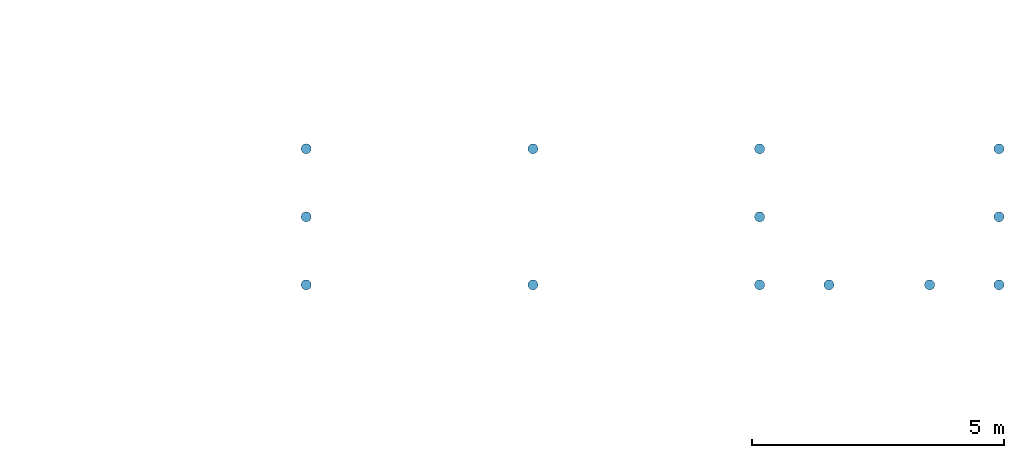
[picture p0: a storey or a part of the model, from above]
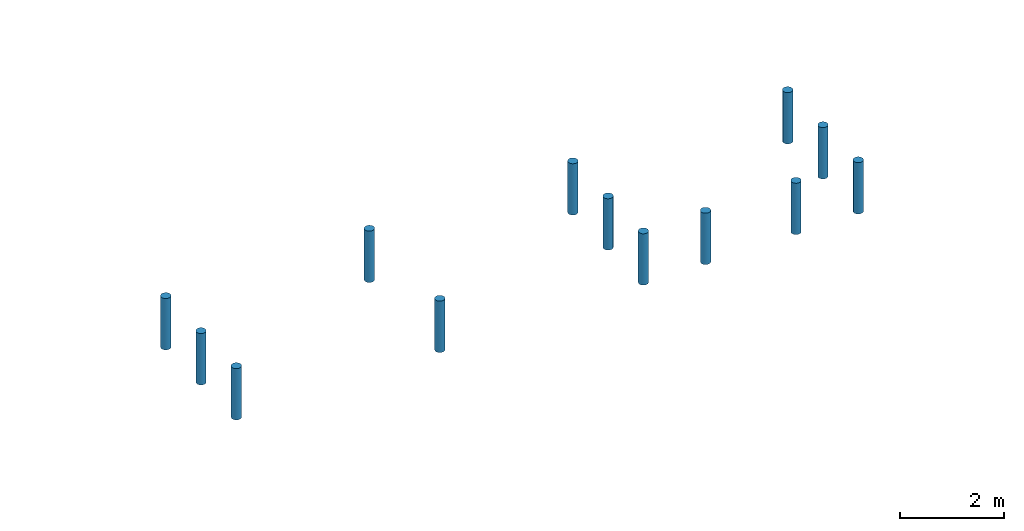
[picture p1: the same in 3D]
Properties of the parts of a building model (IFC2X3), part 1 of 5

# File
Description: ViewDefinition [CoordinationView_V2.0, SpaceBoundary2ndLevelAddOnView], Option [Drawing Scale: 100.000000], Option [Elements to export: Visible elements (on all stories)], Option [Partial Structure Display: Entire Model], Option [IFC Domain: All], Option [Structural Function: All Elements], Option [Convert Grid elements: On], Option [Convert IFC Annotations and ARCHICAD 2D elements: Off], Option [Convert 2D symbols of Doors and Windows: Off], Option [Export geometries that Participates in Collision Detection only: Off], Option [Split complex elements: On], Option [IFC Domain For Space Containment: Custom], Option [Elements in Solid Element Operations: Extruded/revolved], Option [Elements with junctions: Extruded/revolved without junctions], Option [Slabs with slanted edge(s): Extruded], Option [IFC Site Location: At Project Origin], Option [Curtain Wall export mode: Container Element], Option [Railing export mode: Container Element], Option [Stair export mode: Container Element], Option [Properties To Export: All properties], Option [Space containment: Off], Option [Bounding Box: Off], Option [Geometry to type objects: Off], Option [Element Properties: Visible Only], Option [Building Material Properties: Off], Option [Element Parameters: Off], Option [Component Parameters: Off], Option [IFC Base Quantities: Off], Option [Door Window Parameters: On], Option [IFC Space boundaries: On], Option [ARCHICAD Zone Categories as IFC Space classification data: Off], Option [Element Classifications: On]
File name: Z:\03. EHITUSPROJEKTID\2023_355_Paldiski mnt 245 projekteerimine\09-Projektid\3_PÕHIPROJEKT\02-Arhitektuur-TP\IFC\355_TP_AR.ifc
Time: 2023-11-21T12:02:21
Author: Raido Roosnurm (allikirjastatud digitaalselt)
Organization: Building Designer Office
Written by: The EXPRESS Data Manager Version 5.02.0100.09 : 26 Sep 2013
Made in: IFC file generated by GRAPHISOFT ARCHICAD 23.0.0 INT FULL Windows version (IFC add-on version: 7000 INT FULL).
Authorization: Raido Roosnurm (allikirjastatud digitaalselt)

# IfcProject, Ilmavaatlusjaama peahoone rekonstrueerimine
Description: Arhitektuur; Phase: Tööprojekt

# IfcSite, Paldiski mnt 245/1, Tallinn, Harjumaa
Description: Ühiskondlike ehitiste maa 100%; RefLatitude: 59, 26, 0, 0; RefLongitude: 24, 45, 0, 0; RefElevation: 0 mm; Classification: 1.0.1 IfcSite (kinnistu); C Existing site/buildings/services (CAWS)
AR_Kinnistu - 010_Katastritunnus: 78406:605:0160; 020_Pindala: 24079 m2; 025_Max_kõrgus: 8600 mm; 015_Ehitatav_pindala: 1045.7 m2

# IfcBuilding, RKAS Hoone üldnimetus (kasutust iseloomustav) -> IFC Project Manager -> SOLIBRI
Classification: 1.0.2 IfcBuilding (hoone)
AR_Hoone - 035_Sprinkler: no; 001_Nimetus: 12201 Büroohoone; 030_Hoone_aadress: Paldiski mnt 245/1 (katastriüksuse tunnus 78406:605:0160 ), Haabersti linnaosa, Tallinn, Eesti Vabariik; 040_Kõrgus: 8600 mm; ?: 1004.1 m2; 050_Neto_pindala: 1090.4 m2; 055_Neto_ruumala: 5563.9 m3

# IfcBuildingStorey (4)
In: RKAS Hoone üldnimetus (kasutust iseloomustav) -> IFC Project Manager -> SOLIBRI
Name | Elevation (mm) | Classification
Vundament | -1200 | 1.0.3 IfcBuildingStorey (korrus) (RKAS BIM + ARCHICAD Classification 25 + v 2.0)
Esimene korrus | 0 | 1.0.3 IfcBuildingStorey (korrus) (RKAS BIM + ARCHICAD Classification 25 + v 2.0)
Teine korrus | 3300 | 1.0.3 IfcBuildingStorey (korrus) (RKAS BIM + ARCHICAD Classification 25 + v 2.0)
Katusekorrus | 6240

# IfcSpace: Elamise ja puhkealad (2)
In: Teine korrus
InteriorOrExteriorSpace: INTERNAL; Classification: 1.21 IfcSpaceType (ruum) (RKAS BIM + ARCHICAD Classification)
Pset_SpaceCommon - Reference: Korruse avatud netopind; Category: Elamise ja puhkealad
AR_Ruum - 115_Kategooria: Elamise ja puhkealad; 110_Tüüp: Korruse avatud netopind; 125_Turvatsoon: Undefined
AC_Pset_RenovationAndPhasing - Renovation Status: New
Name | LongName = 100_Nimi | 105_Number | 120_Pindala (m2)
204 | PUHKERUUM | 204 | 33.1481
208 | MAGAMISRUUM | 208 | 26.2499

# IfcSpace: Haridus & Kultuur (2)
In: Esimene korrus
LongName: VÄLJAPANEKUD; InteriorOrExteriorSpace: INTERNAL; Classification: 1.21 IfcSpaceType (ruum) (RKAS BIM + ARCHICAD Classification)
Pset_SpaceCommon - Reference: Korruse avatud netopind; Category: Haridus & Kultuur
AR_Ruum - 100_Nimi: VÄLJAPANEKUD; 115_Kategooria: Haridus & Kultuur; 110_Tüüp: Korruse avatud netopind; 125_Turvatsoon: Undefined
AC_Pset_RenovationAndPhasing - Renovation Status: New
Name | 105_Number | 120_Pindala (m2)
127 | 127 | 66.1922
128 | 128 | 32.1546

# IfcSpace: Kontor (10)
InteriorOrExteriorSpace: INTERNAL; Classification: 1.21 IfcSpaceType (ruum) (RKAS BIM + ARCHICAD Classification)
Pset_SpaceCommon - Reference: Korruse avatud netopind; Category: Kontor
AR_Ruum - 115_Kategooria: Kontor; 110_Tüüp: Korruse avatud netopind; 125_Turvatsoon: Undefined
Name | In | LongName = 100_Nimi | 105_Number | 120_Pindala (m2) | Renovation Status
106 | Esimene korrus | KABINET | 106 | 12.4553 | New
105 | Esimene korrus | KABINET | 105 | 12.3328 | New
104 | Esimene korrus | KABINET | 104 | 12.8259 | New
137 | Esimene korrus | KABINET | 137 | 12.2724 | Existing
136 | Esimene korrus | KABINET | 136 | 12.5438 | Existing
214 | Teine korrus | KABINET | 214 | 22.6734 | New
213 | Teine korrus | KABINET | 213 | 23.5477 | New
212 | Teine korrus | KABINET | 212 | 23.9219 | New
211 | Teine korrus | KABINET | 211 | 50.2572 | New
207 | Teine korrus | NÕUPIDAMINE (30 in.) | 207 | 60.7451 | New

# IfcSpace: Ladustamine & Müük (6)
In: Esimene korrus
InteriorOrExteriorSpace: INTERNAL; Classification: 1.21 IfcSpaceType (ruum) (RKAS BIM + ARCHICAD Classification)
Pset_SpaceCommon - Reference: Korruse avatud netopind; Category: Ladustamine & Müük
AR_Ruum - 115_Kategooria: Ladustamine & Müük; 110_Tüüp: Korruse avatud netopind; 125_Turvatsoon: Undefined
AC_Pset_RenovationAndPhasing - Renovation Status: New
Name | LongName = 100_Nimi | 105_Number | 120_Pindala (m2)
107 | LADU | 107 | 36.1465
126 | GARAAZ | 126 | 68.6563
125 | GARAAZ | 125 | 68.3974
121 | LADU (AKUD) | 121 | 7.95556
108 | LADU | 108 | 75.1071
109 | LADU | 109 | 35.0688

# IfcSpace: Muu kasutus (17)
InteriorOrExteriorSpace: INTERNAL; Classification: 1.21 IfcSpaceType (ruum) (RKAS BIM + ARCHICAD Classification)
Pset_SpaceCommon - Category: Muu kasutus
AR_Ruum - 115_Kategooria: Muu kasutus; 125_Turvatsoon: Undefined
Name | In | LongName = 100_Nimi | Reference = 110_Tüüp | 105_Number | 120_Pindala (m2) | Renovation Status
118 | Esimene korrus | WC | Undefined | 118 | 1.76756 | New
111 | Esimene korrus | KORISTAJA | Korruse avatud netopind | 111 | 6.391 | New
132 | Esimene korrus | GARDEROOB | Korruse avatud netopind | 132 | 6.45011 | New
116 | Esimene korrus | DUŠIRUUM | Korruse avatud netopind | 116 | 8.84436 | New
114.1 | Esimene korrus | RIIETUS/HOOLDUSRUUM | Korruse avatud netopind | 114.1 | 30.479 | New
110 | Esimene korrus | INVA WC | Korruse avatud netopind | 110 | 6.38677 | New
130.1 | Esimene korrus | WC | Korruse avatud netopind | 130.1 | 3.36477 | New
130.3 | Esimene korrus | WC | Korruse avatud netopind | 130.3 | 1.12567 | Existing
130.2 | Esimene korrus | WC | Korruse avatud netopind | 130.2 | 1.14087 | Existing
 | Esimene korrus | PRÜGIMAJA | Undefined |  | 11.8508 | New
 | Esimene korrus | JALGRATASTE HOIDLA | Undefined |  | 24.1807 | New
114.3 | Esimene korrus | RIIETUSBOKS | Korruse avatud netopind | 114.3 | 1.35 | Existing
114.2 | Esimene korrus | RIIETUSBOKS | Korruse avatud netopind | 114.2 | 1.25 | Existing
209 | Teine korrus | DUSS/WC | Korruse avatud netopind | 209 | 5.80168 | New
206 | Teine korrus | WC | Korruse avatud netopind | 206 | 3.17635 | New
205 | Teine korrus | WC | Korruse avatud netopind | 205 | 3.04617 | New
210 | Teine korrus | KORISTAJA | Korruse avatud netopind | 210 | 2.58193 | New

# IfcSpace: Tehnoseadmed (3)
InteriorOrExteriorSpace: INTERNAL; Classification: 1.21 IfcSpaceType (ruum) (RKAS BIM + ARCHICAD Classification)
Pset_SpaceCommon - Reference: Tehnopind; Category: Tehnoseadmed
AR_Ruum - 115_Kategooria: Tehnoseadmed; 110_Tüüp: Tehnopind; 125_Turvatsoon: Undefined
AC_Pset_RenovationAndPhasing - Renovation Status: New
Name | In | LongName = 100_Nimi | 105_Number | 120_Pindala (m2)
129 | Esimene korrus | GENERAATOR | 129 | 8.20989
119 | Esimene korrus | TEH. RUUM (el.kilp, vent, sooja- ja veesõlm) | 119 | 43.453
203 | Teine korrus | RADAR | 203 | 16.8812

# IfcSpace: Tootmine & Teadus (3)
In: Esimene korrus
LongName: KALIBREERIMISLABOR; InteriorOrExteriorSpace: INTERNAL; Classification: 1.21 IfcSpaceType (ruum) (RKAS BIM + ARCHICAD Classification)
Pset_SpaceCommon - Reference: Tehnopind; Category: Tootmine & Teadus
AR_Ruum - 100_Nimi: KALIBREERIMISLABOR; 115_Kategooria: Tootmine & Teadus; 110_Tüüp: Tehnopind; 125_Turvatsoon: Undefined
AC_Pset_RenovationAndPhasing - Renovation Status: New
Name | 105_Number | 120_Pindala (m2)
123 | 123 | 5.81406
122 | 122 | 9.8359
124 | 124 | 31.0494

# IfcSpace: Üldine (14)
InteriorOrExteriorSpace: INTERNAL; Classification: 1.21 IfcSpaceType (ruum) (RKAS BIM + ARCHICAD Classification)
Pset_SpaceCommon - Category: Üldine
AR_Ruum - 115_Kategooria: Üldine; 125_Turvatsoon: Undefined
Name | In | LongName = 100_Nimi | Reference = 110_Tüüp | 105_Number | 120_Pindala (m2) | Renovation Status
101 | Esimene korrus | FUAJEE | Korruse avatud netopind | 101 | 34.5309 | New
133 | Esimene korrus | TUULEKODA | Korruse avatud netopind | 133 | 7.69125 | New
120 | Esimene korrus | TUULEKODA | Undefined | 120 | 6.195 | New
117 | Esimene korrus | LEILIRUUM | Undefined | 117 | 4.89433 | New
112 | Esimene korrus | PANIPAIK | Undefined | 112 | 4.02908 | New
103 | Esimene korrus | KORIDOR | Korruse avatud netopind | 103 | 21.3865 | New
113 | Esimene korrus | KORIDOR | Korruse avatud netopind | 113 | 12.2933 | New
115 | Esimene korrus | TUULEKODA | Korruse avatud netopind | 115 | 3.75255 | New
131 | Esimene korrus | KORISTAJA | Korruse avatud netopind | 131 | 3.29858 | New
102 | Esimene korrus | TREPIKODA | Vertikaalsete ühendusteede pind | 102 | 11.8965 | New
135 | Esimene korrus | GARDEROOB | Undefined | 135 | 4.71122 | Existing
134 | Esimene korrus | ÕHUVÕTUKAMBER | Undefined | 134 | 1.53 | New
201 | Teine korrus | TREPIKODA | Vertikaalsete ühendusteede pind | 201 | 18.1173 | New
202 | Teine korrus | KORIDOR | Korruse avatud netopind | 202 | 44.7589 | New

# IfcBeam: CFRHS50X50X5 50 x 50 (7)
In: Esimene korrus
Type - PredefinedType: BEAM
Classification: 1.01 IfcBeamType (tala) (RKAS BIM + ARCHICAD Classification); Material: VKR-04_Tellis
Pset_BeamCommon - Slope: 0 deg; LoadBearing: yes; IsExternal: no; Reference: CFRHS50X50X5 50 x 50
AC_Pset_RenovationAndPhasing - Renovation Status: Existing

# IfcBeam: Laudis esiprofiil_01 21 x 622 (2)
In: Esimene korrus
Type - PredefinedType: BEAM
Classification: 1.01 IfcBeamType (tala) (RKAS BIM + ARCHICAD Classification)
Pset_BeamCommon - Slope: 0 deg; LoadBearing: no; IsExternal: yes; Reference: Laudis esiprofiil_01 21 x 622
AC_Pset_RenovationAndPhasing - Renovation Status: New

# IfcBeam: Laudis kaldprofiil_01 895 x 903 (2)
In: Esimene korrus
Type - PredefinedType: BEAM
Classification: 1.01 IfcBeamType (tala) (RKAS BIM + ARCHICAD Classification)
Pset_BeamCommon - Slope: 0 deg; LoadBearing: no; IsExternal: yes; Reference: Laudis kaldprofiil_01 895 x 903
AC_Pset_RenovationAndPhasing - Renovation Status: New

# IfcBeam: Olemasolev raudbetoontala 320 x 280 (3)
In: Esimene korrus
Type - PredefinedType: BEAM
Classification: 1.01 IfcBeamType (tala) (RKAS BIM + ARCHICAD Classification); Material: Olemasolev raudbetoontala
Pset_BeamCommon - Slope: 0 deg; LoadBearing: yes; IsExternal: no; Reference: Olemasolev raudbetoontala 320 x 280
AC_Pset_RenovationAndPhasing - Renovation Status: Existing

# IfcBeam: Olemasolev raudbetoontala 400 x 260 (7)
In: Teine korrus
Type - PredefinedType: BEAM
Classification: 1.01 IfcBeamType (tala) (RKAS BIM + ARCHICAD Classification); Material: Olemasolev raudbetoontala
Pset_BeamCommon - Slope: 0 deg; LoadBearing: yes; IsExternal: no; Reference: Olemasolev raudbetoontala 400 x 260
AC_Pset_RenovationAndPhasing - Renovation Status: Existing

# IfcBeam: Olemasolev raudbetoontala 400 x 280 (4)
In: Esimene korrus
Type - PredefinedType: BEAM
Classification: 1.01 IfcBeamType (tala) (RKAS BIM + ARCHICAD Classification); Material: Olemasolev raudbetoontala
Pset_BeamCommon - Slope: 0 deg; LoadBearing: yes; IsExternal: no; Reference: Olemasolev raudbetoontala 400 x 280
AC_Pset_RenovationAndPhasing - Renovation Status: Existing

# IfcBeam: Olemasolev raudbetoontala 430 x 310, TALA
In: Esimene korrus
Type - PredefinedType: BEAM
Classification: 1.01 IfcBeamType (tala) (RKAS BIM + ARCHICAD Classification); Material: Olemasolev raudbetoontala
Pset_BeamCommon - Slope: 0 deg; LoadBearing: yes; IsExternal: no; Reference: Olemasolev raudbetoontala 430 x 310
AC_Pset_RenovationAndPhasing - Renovation Status: Existing

# IfcBeam: Olemasolev raudbetoontala 440 x 310, TALA
In: Teine korrus
Type - PredefinedType: BEAM
Classification: 1.01 IfcBeamType (tala) (RKAS BIM + ARCHICAD Classification); Material: Olemasolev raudbetoontala
Pset_BeamCommon - Slope: 0 deg; LoadBearing: yes; IsExternal: no; Reference: Olemasolev raudbetoontala 440 x 310
AC_Pset_RenovationAndPhasing - Renovation Status: Existing

# IfcBeam: Olemasolev raudbetoontala 480 x 370, TALA
In: Teine korrus
Type - PredefinedType: BEAM
Classification: 1.01 IfcBeamType (tala) (RKAS BIM + ARCHICAD Classification); Material: Olemasolev raudbetoontala
Pset_BeamCommon - Slope: 0 deg; LoadBearing: yes; IsExternal: no; Reference: Olemasolev raudbetoontala 480 x 370
AC_Pset_RenovationAndPhasing - Renovation Status: Existing

# IfcBeam: Olemasolev raudbetoontala 530 x 300, TALA
In: Teine korrus
Type - PredefinedType: BEAM
Classification: 1.01 IfcBeamType (tala) (RKAS BIM + ARCHICAD Classification); Material: Olemasolev raudbetoontala
Pset_BeamCommon - Slope: 0 deg; LoadBearing: yes; IsExternal: no; Reference: Olemasolev raudbetoontala 530 x 300
AC_Pset_RenovationAndPhasing - Renovation Status: Existing

# IfcBeam: Olemasolev raudbetoontala 550, Tala
In: Esimene korrus
Type - PredefinedType: BEAM
Classification: 1.01 IfcBeamType (tala) (RKAS BIM + ARCHICAD Classification); Material: Olemasolev raudbetoontala
AC_Pset_RenovationAndPhasing - Renovation Status: Existing
Pset_BeamCommon - LoadBearing: yes; IsExternal: no

# IfcBeam: Olemasolev raudbetoontala 550 x 370, TALA
In: Teine korrus
Type - PredefinedType: BEAM
Classification: 1.01 IfcBeamType (tala) (RKAS BIM + ARCHICAD Classification); Material: Olemasolev raudbetoontala
Pset_BeamCommon - Slope: 0 deg; LoadBearing: yes; IsExternal: no; Reference: Olemasolev raudbetoontala 550 x 370
AC_Pset_RenovationAndPhasing - Renovation Status: Existing

# IfcBeam: TORN_KONST_2 136 x 130 (12)
In: Katusekorrus
Type - PredefinedType: BEAM
Classification: 1.01 IfcBeamType (tala) (RKAS BIM + ARCHICAD Classification); Material: SV-03_Plaat - Põrand
Pset_BeamCommon - Slope: 0 deg; Reference: TORN_KONST_2 136 x 130
AC_Pset_RenovationAndPhasing - Renovation Status: Existing

# IfcBeam: TORN_KONST_3 155 x 165 (4)
In: Katusekorrus
Type - PredefinedType: BEAM
Classification: 1.01 IfcBeamType (tala) (RKAS BIM + ARCHICAD Classification); Material: SV-03_Plaat - Põrand
Pset_BeamCommon - Slope: 0 deg; Reference: TORN_KONST_3 155 x 165
AC_Pset_RenovationAndPhasing - Renovation Status: Existing

# IfcBeam: TORN_KONST_4 175 x 155 (4)
In: Katusekorrus
Type - PredefinedType: BEAM
Classification: 1.01 IfcBeamType (tala) (RKAS BIM + ARCHICAD Classification); Material: SV-03_Plaat - Põrand
Pset_BeamCommon - Slope: 0 deg; Reference: TORN_KONST_4 175 x 155
AC_Pset_RenovationAndPhasing - Renovation Status: Existing

# IfcBeam: TORN_KONST_5 70 x 70 (31)
Type - PredefinedType: BEAM
Classification: 1.01 IfcBeamType (tala) (RKAS BIM + ARCHICAD Classification); Material: SV-03_Plaat - Põrand
Pset_BeamCommon - Reference: TORN_KONST_5 70 x 70
AC_Pset_RenovationAndPhasing - Renovation Status: Existing
Name | In | Slope (deg)
7 x TALA | Esimene korrus | 27.3757
4 x TALA | Teine korrus | 32.8702
4 x TALA | Teine korrus | 32.6354
4 x TALA | Katusekorrus | 39.1421
4 x TALA | Katusekorrus | 36.9819
4 x TALA | Katusekorrus | 37.0505
4 x TALA | Katusekorrus | 39.1317

# IfcBeam: TORN_KONST_6 60 x 130 (4)
In: Teine korrus
Type - PredefinedType: BEAM
Classification: 1.01 IfcBeamType (tala) (RKAS BIM + ARCHICAD Classification); Material: SV-03_Plaat - Põrand
Pset_BeamCommon - Slope: 0 deg; LoadBearing: yes; IsExternal: yes; Reference: TORN_KONST_6 60 x 130
AC_Pset_RenovationAndPhasing - Renovation Status: Existing

# IfcBuildingElementPart (1711)
Name | In | Material
28 x Võõphüdroisolatsioon | Vundament | Võõphüdroisolatsioon
28 x EPS 120 Perimeeter | Vundament | EPS 120 Perimeeter
28 x Krohvisüsteem Weber vms | Vundament | Krohvisüsteem Weber vms
43 x Cembrit_C040 | Esimene korrus | Cembrit_C040
88 x VKR-06_Õhkvahe | Esimene korrus | VKR-06_Õhkvahe
90 x Kingspan Kooltherm | Esimene korrus | Kingspan Kooltherm
26 x EPS 200 | Esimene korrus | EPS 200
13 x Visqueen radoonikile | Esimene korrus | Visqueen radoonikile
13 x Kiudbetoon | Esimene korrus | Kiudbetoon
6 x SOJ-04_Soojustus - Mineraal Kõva | Esimene korrus | SOJ-04_Soojustus - Mineraal Kõva
38 x SKR-01_Õhkvahe - Raam | Esimene korrus | SKR-01_Õhkvahe - Raam
19 x Cembrit_C060 | Esimene korrus | Cembrit_C060
9 x Tasanduskrohv | Esimene korrus | Tasanduskrohv
21 x Cembrit_C020 | Esimene korrus | Cembrit_C020
6 x BAUROC CLASSIC 3 MPa kergplokk | Esimene korrus | BAUROC CLASSIC 3 MPa kergplokk
54 x Krohv | Esimene korrus | Krohv
27 x FIBO 5 | Esimene korrus | FIBO 5
6 x Isover Premium 33 | Esimene korrus | Isover Premium 33
6 x Isover Sauna | Esimene korrus | Isover Sauna
6 x Õhkvahe/horisontpuitroov | Esimene korrus | Õhkvahe/horisontpuitroov
6 x Õhkvahe/vertpuitroov | Esimene korrus | Õhkvahe/vertpuitroov
6 x Sauna puitlaudis | Esimene korrus | Sauna puitlaudis
8 x SKR-04_Puitplaat | Esimene korrus | SKR-04_Puitplaat
2 x SOJ-03_Soojustus - Mineraal Pehme | Esimene korrus | SOJ-03_Soojustus - Mineraal Pehme
16 x Kipsplaat Knauf GKF vm | Esimene korrus | Kipsplaat Knauf GKF vm
SV-05_Plaat - Sein | Esimene korrus | SV-05_Plaat - Sein
169 x Laudis 5072 Honka 45 horisontaalne raastas | Esimene korrus | Laudis 5072 Honka 45 horisontaalne raastas
4 x OSB plaat | Esimene korrus | OSB plaat
3 x Isover Acoustic | Esimene korrus | Isover Acoustic
5 x Kaldu lõigatud soojustus, EPS60 Silver | Esimene korrus | Kaldu lõigatud soojustus, EPS60 Silver
5 x Põhisoojustus, Eurothane Silver E 120 mm | Esimene korrus | Põhisoojustus, Eurothane Silver E 120 mm
5 x Katusekate PVC 1,6 mm, PROTAN SE | Esimene korrus | Katusekate PVC 1,6 mm, PROTAN SE
5 x Puit - Konstruktsioon | Esimene korrus | Puit - Konstruktsioon
16 x RAL7016 | Esimene korrus | RAL7016
5 x PVC | Esimene korrus | PVC
5 x Veekindel vineer 24 mm | Esimene korrus | Veekindel vineer 24 mm
88 x Laudis 5072 Honka 45 horisontaalne | Esimene korrus | Laudis 5072 Honka 45 horisontaalne
10 x Teras - Konstruktsioon | Esimene korrus | Teras - Konstruktsioon
4 x VV-00_GENEERILINE - VÄLINE VOODER | Esimene korrus | VV-00_GENEERILINE - VÄLINE VOODER
4 x ET-03_Raud | Esimene korrus | ET-03_Raud
6 x Voodrilaud UYS 21x120mm | Esimene korrus | Voodrilaud UYS 21x120mm
3 x Puitkarkass 150x150 ja 50x150 mm/õhuvahe | Esimene korrus | Puitkarkass 150x150 ja 50x150 mm/õhuvahe
2 x VKK-02_Liiv | Esimene korrus | VKK-02_Liiv
VKK-03_Killustik | Esimene korrus | VKK-03_Killustik
VKR-03_Betoon Plokk - Krunt | Esimene korrus | VKR-03_Betoon Plokk - Krunt
Aurutõke SBS | Esimene korrus | Aurutõke SBS
EPS 60 Silver | Esimene korrus | EPS 60 Silver
VKR-05_Klaas | Esimene korrus | VKR-05_Klaas
2 x Jäik vahtpolüstüreenplaat, EPS80 | Teine korrus | Jäik vahtpolüstüreenplaat, EPS80
2 x Sammumüra isolatsioon (Isover FLO, Paroc SSB1 vm) | Teine korrus | Sammumüra isolatsioon (Isover FLO, Paroc SSB1 vm)
2 x Polüetüleenkile | Teine korrus | Polüetüleenkile
2 x Raudbetoon põrandaplaat | Teine korrus | Raudbetoon põrandaplaat
11 x Cembrit_C020 | Teine korrus | Cembrit_C020
54 x VKR-06_Õhkvahe | Teine korrus | VKR-06_Õhkvahe
31 x Kingspan Kooltherm | Teine korrus | Kingspan Kooltherm
33 x Cembrit_C040 | Teine korrus | Cembrit_C040
40 x Kipsplaat Knauf GKF vm | Teine korrus | Kipsplaat Knauf GKF vm
37 x OSB plaat | Teine korrus | OSB plaat
34 x Isover Acoustic | Teine korrus | Isover Acoustic
3 x SKR-01_Õhkvahe - Raam | Teine korrus | SKR-01_Õhkvahe - Raam
3 x SKR-04_Puitplaat | Teine korrus | SKR-04_Puitplaat
5 x Cembrit_C060 | Teine korrus | Cembrit_C060
6 x ET-01_Puit - Konstruktsioon | Teine korrus | ET-01_Puit - Konstruktsioon
3 x Õhkvahe - Raam | Teine korrus | Õhkvahe - Raam
BAUROC CLASSIC 3 MPa kergplokk | Teine korrus | BAUROC CLASSIC 3 MPa kergplokk
2 x SOJ-03_Soojustus - Mineraal Pehme | Teine korrus | SOJ-03_Soojustus - Mineraal Pehme
2 x PVC | Teine korrus | PVC
44 x Laudis 5072 Honka 45 horisontaalne raastas | Teine korrus | Laudis 5072 Honka 45 horisontaalne raastas
VMR-03_Membraan - Veekindel | Teine korrus | VMR-03_Membraan - Veekindel
14 x Kaldu lõigatud soojustus, EPS60 Silver | Teine korrus | Kaldu lõigatud soojustus, EPS60 Silver
13 x Põhisoojustus, Eurothane Silver E 120 mm | Teine korrus | Põhisoojustus, Eurothane Silver E 120 mm
16 x Katusekate PVC 1,6 mm, PROTAN SE | Teine korrus | Katusekate PVC 1,6 mm, PROTAN SE
Veekindel vineer 24 mm | Teine korrus | Veekindel vineer 24 mm
Tasanduskiht tsementmört | Teine korrus | Tasanduskiht tsementmört
Aurutõke SBS | Teine korrus | Aurutõke SBS
4 x EPS 60 Silver | Teine korrus | EPS 60 Silver
Olemasolev silikaltsiitpaneel | Teine korrus | Olemasolev silikaltsiitpaneel
Olemasolev silikaltsiitplokk | Teine korrus | Olemasolev silikaltsiitplokk
35 x Veekindel vineer 24 mm | Katusekorrus | Veekindel vineer 24 mm
207 x Laudis 5072 Honka 45 horisontaalne raastas | Katusekorrus | Laudis 5072 Honka 45 horisontaalne raastas
21 x SOJ-04_Soojustus - Mineraal Kõva | Katusekorrus | SOJ-04_Soojustus - Mineraal Kõva
27 x PVC | Katusekorrus | PVC
24 x RAL7016 | Katusekorrus | RAL7016
14 x ET-01_Puit - Konstruktsioon | Katusekorrus | ET-01_Puit - Konstruktsioon
3 x Õhkvahe - Raam | Katusekorrus | Õhkvahe - Raam
2 x EPS 60 Silver | Katusekorrus | EPS 60 Silver
15 x Katusekate PVC 1,6 mm, PROTAN SE | Katusekorrus | Katusekate PVC 1,6 mm, PROTAN SE
3 x Puit - Konstruktsioon | Katusekorrus | Puit - Konstruktsioon
2 x Raudbetoon kandev 220 mm | Katusekorrus | Raudbetoon kandev 220 mm
3 x Tasanduskiht tsementmört | Katusekorrus | Tasanduskiht tsementmört
3 x Aurutõke SBS | Katusekorrus | Aurutõke SBS
12 x Kaldu lõigatud soojustus, EPS60 Silver | Katusekorrus | Kaldu lõigatud soojustus, EPS60 Silver
9 x Põhisoojustus, Eurothane Silver E 120 mm | Katusekorrus | Põhisoojustus, Eurothane Silver E 120 mm
10 x SKR-05_Vineer | Katusekorrus | SKR-05_Vineer
13 x SOJ-03_Soojustus - Mineraal Pehme | Katusekorrus | SOJ-03_Soojustus - Mineraal Pehme

# IfcBuildingElementProxy: AP-02 pealiskihid 222 (4)
In: Esimene korrus
AC_Pset_RenovationAndPhasing - Renovation Status: New

# IfcBuildingElementProxy: Cembrit_C060 8 (5)
Classification: 1.14 IfcOpeningElement (avaelement) (RKAS BIM + ARCHICAD Classification); Material: Cembrit_C060
Pset_BuildingElementProxyCommon - Reference: Cembrit C060
AC_Pset_RenovationAndPhasing - Renovation Status: New
Name | In
3 x Cembrit C060 | Esimene korrus
2 x Cembrit C060 | Teine korrus

# IfcBuildingElementProxy: Conoid 23 (3)
In: Katusekorrus
Classification: 1.02 IfcBuildingElementProxyType (objekt) (RKAS BIM + ARCHICAD Classification)
Pset_ManufacturerTypeInformation - Manufacturer: LOROWERK K.H. Vahlbrauk GmbH & Co. KG
Pset_DistributionFlowElementCommon - Reference: LOROWERK 01390-100X
Abhängigkeiten - Basisbauteil: Ebene : Ebene 1; Ebene: Ebene: Ebene 1; Versatz: 0 mm
Abmessungen - Fläche: 0.306423 m2; Volumen: 0.0277664 m3; CONNECTOR0_DIAMETER_dZ_0r: 100 mm; CONNECTOR0_dZ_00: 14 mm; CONNECTOR0_dZ_01: 14.7937 mm; CONNECTOR0_ref_dZ: 14.7937 mm; CONNECTOR1_DIAMETER_dNBN0_0r: 100 mm; CONNECTOR1_dNBN0_00: 213.222 mm; CONNECTOR1_dNBN0_01: 287.222 mm; CONNECTOR1_ref_dNBN0: 213.222 mm; CONNECTOR1_ref_dNBN1: 54.042 mm
HLS - Systemklassifizierung: Nicht definiert
ID-Daten - Kennzeichen: 19; Beschreibung: LORO-RAINSTAR Attikaabläufe, Serie 88, Attika-Distant, ohne Aufkantung; DATANORM: 01390.100X; GTIN: 4038088074183; HAN: 01390.100X; Hersteller: LOROWERK K.H. Vahlbrauk GmbH & Co. KG; Typname: LOROWERK 01390-100X; VDIBSN: 0020090000020010000010020010010000000030020000000300000001
Phasen - Phase erstellt: Neue Konstruktion
Sonstige - Familie: LOROWERK 01390-100X: LOROWERK 01390-100X; Familie und Typ: LOROWERK 01390-100X: LOROWERK 01390-100X; Kategorie: Sanitärinstallationen; Typ: LOROWERK 01390-100X: LOROWERK 01390-100X; Typ-ID: LOROWERK 01390-100X: LOROWERK 01390-100X; Familienname: LOROWERK 01390-100X
Allgemein - Abdichtvarianten: mit Klemmflansch; Abflussstutzen Ausführung: waagerecht; Ablaufanschluss: 1; Art der Nenn-/Betriebsspannung: nicht zutreffend; BIM: https://media.stage.bim.site/t/eyJhbGciOiJIUzI1NiIsInR5cCI6IkpXVCJ9.eyJjdCI6MSwidGYiOiJwdWJsaWMvbG9yb3dlcmsta2gtdmFobGJyYXVrLWdtYmgtY28ta2cvZDMwZTRjMS9QQVJUMzhfTG9yb18yMDE5MDcwMV8xLlZESSIsImNpZCI6IjMyNzdjYzIzLTgxYTktNGVlMy1hOTBhLWI0N2JiNGMwYjYxNiIsInJpZCI6IjdkOWE3MDg4NDgxYTBhMzQzMWY0N2FlZTliODFlOTc5IiwicGlkIjoiZTMxM2E5NGFhMTA2ZDA4MmExMTY3YzRlYTMwOTYyMjU2M2I5ZmY5YyIsInNpZCI6IjY2MzI1IiwidXQiOjUsImlhdCI6MTU2NTA5MjQwMSwiaXNzIjoiaHR0cHM6Ly9hcGkubGl2ZS5iaW0uc2l0ZSIsInN1YiI6ImFkbWluQGJpbXNpdGUuZGV2In0.Jl98j6UJM8vCRfjiMgs0gIMvvY09N5LGU-t2YxvX5b0/PART38_Loro_20190701_1.VDI; elektrischer Anschluss: nein; Feuerwiderstandsklasse: keine Feuerwiderstandsklasse; Feuerwiderstandsklasse nachrüstbar: nein; Gehäuseanschlussarten: Ablauf punktförmig; Geruchsverschluss: ohne Geruchsverschluss; Heizung: ohne Heizung; Ist System: no; Ist Zubehör: no; Kommentar: Serie 88, Attika-Distant, ohne Aufkantung; Nenndruck: 422; Nenndrucksystem: 270; Nennweitensystem: PN; Potenzialausgleich (Erdungsanschluss) vorhanden: ja; Produktbezeichnung: LORO-RAINSTAR 88 Attikaablauf, ohne Aufkant., Edelst., Klemmfl., Freispiegel, DN100; Produktklassifikation: Attikaablauf; Produktname: LORO-RAINSTAR 88 Attikaablauf, ohne Aufkant., Edelst., Klemmfl., Freispiegel, DN100; Produktvideo: https://media.stage.bim.site/t/eyJhbGciOiJIUzI1NiIsInR5cCI6IkpXVCJ9.eyJjdCI6MiwidHUiOiJodHRwOi8vd3d3Lmxvcm8uZGUvaW5kZXgucGhwP2lkPTIzM1x1MDAyNmFydGlrZWxucj0wMTM5MC4xMDBYIiwiY2lkIjoiMzI3N2NjMjMtODFhOS00ZWUzLWE5MGEtYjQ3YmI0YzBiNjE2IiwicmlkIjoiN2Q5YTcwODg0ODFhMGEzNDMxZjQ3YWVlOWI4MWU5NzkiLCJwaWQiOiJlMzEzYTk0YWExMDZkMDgyYTExNjdjNGVhMzA5NjIyNTYzYjlmZjljIiwic2lkIjoiNjYzMjUiLCJ1dCI6MiwiaWF0IjoxNTY1MDkyNDAxLCJpc3MiOiJodHRwczovL2FwaS5saXZlLmJpbS5zaXRlIiwic3ViIjoiYWRtaW5AYmltc2l0ZS5kZXYifQ._1ocKl-vpR0muEJ6-8qR1rfxTU_H0VxG05urxzZZrKM; Wärmedämmung: ohne Wärmedämmung; Werkstoff des Ablaufkörpers: nicht rostender Stahl
Daten - 38.710.01.13: seitlich; 38.710.01.5: DN; Bestellmenge (Multiplikator): 1; Einbaubreite [m]: 0.24; Einbautiefe [m]: 0; Sperrwasserhöhe [m]: 0
Pset_BuildingElementProxyCommon - Reference: LOROWERK 01390-100X:LOROWERK 01390-100X:259572
AC_Pset_RenovationAndPhasing - Renovation Status: New

# IfcBuildingElementProxy: Cube 23 (2)
In: Esimene korrus
Classification: 1.02.1 IfcBuildingElementProxyType (reeper) (RKAS BIM + ARCHICAD Classification)
AR_Reeper - 01_X-(L-EST): 3000; 02_Y-(L-EST): 1000; 03_Z-(EH2000): 7000; 04_Nurk(◦): 0
AC_Pset_RenovationAndPhasing - Renovation Status: New

# IfcBuildingElementProxy: Downspout 23 (26)
Classification: 1.02 IfcBuildingElementProxyType (objekt) (RKAS BIM + ARCHICAD Classification)
AC_Pset_RenovationAndPhasing - Renovation Status: New
Name | In | Reference
2 x Vihmaveetoru | Esimene korrus | Vihmaveetoru
12 x Vihmaveetoru 100x100 mm | Teine korrus | Vihmaveetoru 100x100 mm
12 x Vihmaveetoru 100x100 mm | Katusekorrus | Vihmaveetoru 100x100 mm

# IfcBuildingElementProxy: Downspout Elbow 23 (10)
Classification: 1.02 IfcBuildingElementProxyType (objekt) (RKAS BIM + ARCHICAD Classification)
AC_Pset_RenovationAndPhasing - Renovation Status: New
Name | In | Reference
2 x Vihmaveetoru | Esimene korrus | Vihmaveetoru
4 x Vihmaveetoru 100x100 mm | Teine korrus | Vihmaveetoru 100x100 mm
4 x Vihmaveetoru 100x100 mm | Katusekorrus | Vihmaveetoru 100x100 mm

# IfcBuildingElementProxy: ET-01_Puit - Konstruktsioon 1004 (22)
In: Teine korrus
Classification: 1.02 IfcBuildingElementProxyType (objekt) (RKAS BIM + ARCHICAD Classification); Material: ET-01_Puit - Konstruktsioon
Pset_BuildingElementProxyCommon - Reference: Varikatus
AC_Pset_RenovationAndPhasing - Renovation Status: New

# IfcBuildingElementProxy: ET-01_Puit - Konstruktsioon 1005 (22)
In: Teine korrus
Classification: 1.02 IfcBuildingElementProxyType (objekt) (RKAS BIM + ARCHICAD Classification); Material: ET-01_Puit - Konstruktsioon
Pset_BuildingElementProxyCommon - Reference: Varikatus
AC_Pset_RenovationAndPhasing - Renovation Status: New

# IfcBuildingElementProxy: ET-01_Puit - Konstruktsioon 2280 (25)
In: Esimene korrus
Classification: 1.02 IfcBuildingElementProxyType (objekt) (RKAS BIM + ARCHICAD Classification); Material: ET-01_Puit - Konstruktsioon
Pset_BuildingElementProxyCommon - Reference: Varikatus
AC_Pset_RenovationAndPhasing - Renovation Status: New

# IfcBuildingElementProxy: ET-01_Puit - Konstruktsioon 2560 (54)
In: Esimene korrus
Classification: 1.02 IfcBuildingElementProxyType (objekt) (RKAS BIM + ARCHICAD Classification); Material: ET-01_Puit - Konstruktsioon
Pset_BuildingElementProxyCommon - Reference: Varikatus
AC_Pset_RenovationAndPhasing - Renovation Status: New

# IfcBuildingElementProxy: ET-01_Puit - Konstruktsioon 280 (88)
In: Teine korrus
Classification: 1.02 IfcBuildingElementProxyType (objekt) (RKAS BIM + ARCHICAD Classification); Material: ET-01_Puit - Konstruktsioon
Pset_BuildingElementProxyCommon - Reference: Varikatus
AC_Pset_RenovationAndPhasing - Renovation Status: New

# IfcBuildingElementProxy: ET-01_Puit - Konstruktsioon 2982 (2)
In: Esimene korrus
Classification: 1.02 IfcBuildingElementProxyType (objekt) (RKAS BIM + ARCHICAD Classification); Material: ET-01_Puit - Konstruktsioon
Pset_BuildingElementProxyCommon - Reference: Varikatus
AC_Pset_RenovationAndPhasing - Renovation Status: New

# IfcBuildingElementProxy: ET-01_Puit - Konstruktsioon 3222 (40)
In: Esimene korrus
Classification: 1.02 IfcBuildingElementProxyType (objekt) (RKAS BIM + ARCHICAD Classification); Material: ET-01_Puit - Konstruktsioon
Pset_BuildingElementProxyCommon - Reference: Varikatus
AC_Pset_RenovationAndPhasing - Renovation Status: New

# IfcBuildingElementProxy: ET-01_Puit - Konstruktsioon 3284 (2)
In: Esimene korrus
Classification: 1.02 IfcBuildingElementProxyType (objekt) (RKAS BIM + ARCHICAD Classification); Material: ET-01_Puit - Konstruktsioon
Pset_BuildingElementProxyCommon - Reference: Varikatus
AC_Pset_RenovationAndPhasing - Renovation Status: New

# IfcBuildingElementProxy: ET-01_Puit - Konstruktsioon 3285 (2)
In: Esimene korrus
Classification: 1.02 IfcBuildingElementProxyType (objekt) (RKAS BIM + ARCHICAD Classification); Material: ET-01_Puit - Konstruktsioon
Pset_BuildingElementProxyCommon - Reference: Varikatus
AC_Pset_RenovationAndPhasing - Renovation Status: New

# IfcBuildingElementProxy: ET-01_Puit - Konstruktsioon 3460 (48)
In: Esimene korrus
Classification: 1.02 IfcBuildingElementProxyType (objekt) (RKAS BIM + ARCHICAD Classification); Material: ET-01_Puit - Konstruktsioon
Pset_BuildingElementProxyCommon - Reference: Varikatus
AC_Pset_RenovationAndPhasing - Renovation Status: New

# IfcBuildingElementProxy: ET-01_Puit - Konstruktsioon 4084 (56)
In: Esimene korrus
Classification: 1.02 IfcBuildingElementProxyType (objekt) (RKAS BIM + ARCHICAD Classification); Material: ET-01_Puit - Konstruktsioon
Pset_BuildingElementProxyCommon - Reference: Varikatus
AC_Pset_RenovationAndPhasing - Renovation Status: New

# IfcBuildingElementProxy: ET-01_Puit - Konstruktsioon 722 (46)
In: Teine korrus
Classification: 1.02 IfcBuildingElementProxyType (objekt) (RKAS BIM + ARCHICAD Classification); Material: ET-01_Puit - Konstruktsioon
Pset_BuildingElementProxyCommon - Reference: Varikatus
AC_Pset_RenovationAndPhasing - Renovation Status: New

# IfcBuildingElementProxy: ET-03_Raud D100 (3)
In: Esimene korrus
Classification: 1.02 IfcBuildingElementProxyType (objekt) (RKAS BIM + ARCHICAD Classification)
Pset_BuildingElementProxyCommon - Reference: Pollar
AC_Pset_RenovationAndPhasing - Renovation Status: New

# IfcBuildingElementProxy: ET-03_Raud D170, Pollar
In: Esimene korrus
Classification: 1.02 IfcBuildingElementProxyType (objekt) (RKAS BIM + ARCHICAD Classification)
Pset_BuildingElementProxyCommon - Reference: Pollar
AC_Pset_RenovationAndPhasing - Renovation Status: New

# IfcBuildingElementProxy: ET-03_Raud D30 (13)
In: Esimene korrus
Material: ET-03_Raud
AC_Pset_RenovationAndPhasing - Renovation Status: New

# IfcBuildingElementProxy: ET-07_Teras - Roostevaba D10 (68)
In: Esimene korrus
Material: ET-07_Teras - Roostevaba
AC_Pset_RenovationAndPhasing - Renovation Status: New

# IfcBuildingElementProxy: GENERIC - STRUCTURAL 125 x 450 (6)
In: Teine korrus
Material: GENERIC - STRUCTURAL
AC_Pset_RenovationAndPhasing - Renovation Status: New

# IfcBuildingElementProxy: GENERIC - STRUCTURAL 150 x 50 (8)
In: Esimene korrus
Material: GENERIC - STRUCTURAL
AC_Pset_RenovationAndPhasing - Renovation Status: New

# IfcBuildingElementProxy: Gutter 23 (6)
Classification: 1.02 IfcBuildingElementProxyType (objekt) (RKAS BIM + ARCHICAD Classification)
AC_Pset_RenovationAndPhasing - Renovation Status: New
Name | In | Reference
2 x Vihmaveerenn | Teine korrus | Vihmaveerenn
4 x Vihmaveetoru 100x100 mm | Katusekorrus | Vihmaveetoru 100x100 mm

# IfcBuildingElementProxy: IfcBuildingElementProxy (369)
In: Esimene korrus
Name | Material | Renovation Status
13 x HANDRAIL END - 002 | Teras - Konstruktsioon | New
5 x PIIRDE POST - 001 | RAL7016 | New
2 x HANDRAIL CONNECTION - 001 | Teras - Konstruktsioon | New
2 x HANDRAIL CONNECTION - 002 | Teras - Konstruktsioon | New
7 x ÜL PIIRDE ÜHENDUS - 001 | RAL7016 | New
30 x KÄSIPUU - 001 | Teras - Konstruktsioon | New
8 x ÜL PIIRE - 001 | RAL7016 | New
134 x BALUSTER - 001 | RAL7016 | New
6 x HANDRAIL END - 001 | Teras - Konstruktsioon | New
134 x SISEPOST - 001 | RAL7016 | New
2 x HANDRAIL END - 002 | ET-07_Teras - Roostevaba | New
5 x ÜL PIIRDE OTS - 001 | RAL7016 | New
10 x ÜL PIIRE - 001 |  | New
11 x SISEPOST - 001 | RAL7016 | Existing

# IfcBuildingElementProxy: Jalatsipuhastusrest (6)
In: Esimene korrus
Classification: 1.02 IfcBuildingElementProxyType (objekt) (RKAS BIM + ARCHICAD Classification); Material: Raud
Pset_BuildingElementProxyCommon - Reference: Jalatsipuhastusrest
AC_Pset_RenovationAndPhasing - Renovation Status: New

# IfcBuildingElementProxy: KON-00_GENEERILINE - KONSTRUKTSIOON 70 x 70 (16)
In: Katusekorrus
Material: KON-00_GENEERILINE - KONSTRUKTSIOON
AC_Pset_RenovationAndPhasing - Renovation Status: Existing
Name
8 x TALA
8 x POST

# IfcBuildingElementProxy: Katus_vineer+PVC 26, Veekindel vineer 24 mm
In: Teine korrus
AC_Pset_RenovationAndPhasing - Renovation Status: New

# IfcBuildingElementProxy: Laudis 5072 Honka 45 horisontaalne 20 (2)
In: Esimene korrus
Material: Laudis 5072 Honka 45 horisontaalne
AC_Pset_RenovationAndPhasing - Renovation Status: New

# IfcBuildingElementProxy: Laudis UYS 20x120 mm_valge 20 (2)
In: Teine korrus
Material: Laudis UYS 20x120 mm_valge
AC_Pset_RenovationAndPhasing - Renovation Status: New

# IfcBuildingElementProxy: Laudis ava ulemine serv_02 2213 x 21 (2)
In: Esimene korrus
Classification: 1.02 IfcBuildingElementProxyType (objekt) (RKAS BIM + ARCHICAD Classification)
AR_Sein - 500_Kandev: yes
Pset_BuildingElementProxyCommon - Reference: Varikatus
AC_Pset_RenovationAndPhasing - Renovation Status: New

# IfcBuildingElementProxy: Laudis ava ülemine serv_01 2200 x 21 (2)
In: Esimene korrus
Classification: 1.02 IfcBuildingElementProxyType (objekt) (RKAS BIM + ARCHICAD Classification)
AR_Sein - 500_Kandev: yes
Pset_BuildingElementProxyCommon - Reference: Varikatus
AC_Pset_RenovationAndPhasing - Renovation Status: New

# IfcBuildingElementProxy: Laudis esiprofiil_01 21 x 622 (4)
In: Esimene korrus
Classification: 1.02 IfcBuildingElementProxyType (objekt) (RKAS BIM + ARCHICAD Classification)
Pset_BuildingElementProxyCommon - Reference: Varikatus
AC_Pset_RenovationAndPhasing - Renovation Status: New

# IfcBuildingElementProxy: Puit - Konstruktsioon 100 (7)
In: Esimene korrus
Classification: 1.02 IfcBuildingElementProxyType (objekt) (RKAS BIM + ARCHICAD Classification); Material: Puit - Konstruktsioon
AC_Pset_RenovationAndPhasing - Renovation Status: New
Name | Reference
5 x SM-3 | SM-3
SS-63 | SS-63
SS-59 | SS-59

# IfcBuildingElementProxy: Puit konstruktsioon 150 x 150 (3)
In: Esimene korrus
Material: Puit konstruktsioon
AC_Pset_RenovationAndPhasing - Renovation Status: New

# IfcBuildingElementProxy: Puit konstruktsioon 150 x 50, Puitpruss 150x50 mm
In: Esimene korrus
Material: Puit konstruktsioon
AC_Pset_RenovationAndPhasing - Renovation Status: New

# IfcBuildingElementProxy: Puit konstruktsioon 25 x 75 (179)
In: Esimene korrus
Material: Puit konstruktsioon
AC_Pset_RenovationAndPhasing - Renovation Status: New

# IfcBuildingElementProxy: Puit konstruktsioon 50 x 150 (63)
Material: Puit konstruktsioon
AC_Pset_RenovationAndPhasing - Renovation Status: New
Name | In
6 x Puitraam 50x150 mm | Esimene korrus
14 x Puitpruss 150x50 mm | Esimene korrus
10 x Puitpruss 50x150mm | Esimene korrus
4 x Puitraam 50x150mm | Esimene korrus
4 x Puitpruss 50x150 mm | Esimene korrus
25 x Puittala 50x150 mm | Teine korrus

# IfcBuildingElementProxy: Pürgimaja_varjualuse_välissein 190 (3)
In: Esimene korrus
AC_Pset_RenovationAndPhasing - Renovation Status: New

# IfcBuildingElementProxy: RAL 7011 Tumehall 50 (68)
In: Esimene korrus
Material: RAL 7011 Tumehall
AC_Pset_RenovationAndPhasing - Renovation Status: New

# IfcBuildingElementProxy: Railing Type (9)
In: Esimene korrus
Name | Renovation Status
4 x Trepipiire | New
5 x Trepipiire | Existing

# IfcBuildingElementProxy: Solar Photovoltaic Panel 23 (80)
In: Teine korrus
Classification: 1.02 IfcBuildingElementProxyType (objekt) (RKAS BIM + ARCHICAD Classification)
Pset_BuildingElementProxyCommon - Reference: Päikesepaneel
AC_Pset_RenovationAndPhasing - Renovation Status: New

# IfcBuildingElementProxy: Solar Shade Straight 17 (43)
Classification: 1.02 IfcBuildingElementProxyType (objekt) (RKAS BIM + ARCHICAD Classification)
Pset_BuildingElementProxyCommon - Reference: Päikesezalusii
AC_Pset_RenovationAndPhasing - Renovation Status: New
Name | In
30 x Päikesezalusii | Esimene korrus
13 x Päikesezalusii | Teine korrus

# IfcBuildingElementProxy: Tube 23 (8)
Classification: 1.02 IfcBuildingElementProxyType (objekt) (RKAS BIM + ARCHICAD Classification)
Pset_ManufacturerTypeInformation - Manufacturer: LOROWERK K.H. Vahlbrauk GmbH & Co. KG
Pset_DistributionFlowElementCommon - Reference: LOROWERK 01390-100X
Abhängigkeiten - Basisbauteil: Ebene : Ebene 1; Ebene: Ebene: Ebene 1; Versatz: 0 mm
Abmessungen - Fläche: 0.306423 m2; Volumen: 0.0277664 m3; CONNECTOR0_DIAMETER_dZ_0r: 100 mm; CONNECTOR0_dZ_00: 14 mm; CONNECTOR0_dZ_01: 14.7937 mm; CONNECTOR0_ref_dZ: 14.7937 mm; CONNECTOR1_DIAMETER_dNBN0_0r: 100 mm; CONNECTOR1_dNBN0_00: 213.222 mm; CONNECTOR1_dNBN0_01: 287.222 mm; CONNECTOR1_ref_dNBN0: 213.222 mm; CONNECTOR1_ref_dNBN1: 54.042 mm
HLS - Systemklassifizierung: Nicht definiert
ID-Daten - Kennzeichen: 19; Beschreibung: LORO-RAINSTAR Attikaabläufe, Serie 88, Attika-Distant, ohne Aufkantung; DATANORM: 01390.100X; GTIN: 4038088074183; HAN: 01390.100X; Hersteller: LOROWERK K.H. Vahlbrauk GmbH & Co. KG; Typname: LOROWERK 01390-100X; VDIBSN: 0020090000020010000010020010010000000030020000000300000001
Phasen - Phase erstellt: Neue Konstruktion
Sonstige - Familie: LOROWERK 01390-100X: LOROWERK 01390-100X; Familie und Typ: LOROWERK 01390-100X: LOROWERK 01390-100X; Kategorie: Sanitärinstallationen; Typ: LOROWERK 01390-100X: LOROWERK 01390-100X; Typ-ID: LOROWERK 01390-100X: LOROWERK 01390-100X; Familienname: LOROWERK 01390-100X
Allgemein - Abdichtvarianten: mit Klemmflansch; Abflussstutzen Ausführung: waagerecht; Ablaufanschluss: 1; Art der Nenn-/Betriebsspannung: nicht zutreffend; BIM: https://media.stage.bim.site/t/eyJhbGciOiJIUzI1NiIsInR5cCI6IkpXVCJ9.eyJjdCI6MSwidGYiOiJwdWJsaWMvbG9yb3dlcmsta2gtdmFobGJyYXVrLWdtYmgtY28ta2cvZDMwZTRjMS9QQVJUMzhfTG9yb18yMDE5MDcwMV8xLlZESSIsImNpZCI6IjMyNzdjYzIzLTgxYTktNGVlMy1hOTBhLWI0N2JiNGMwYjYxNiIsInJpZCI6IjdkOWE3MDg4NDgxYTBhMzQzMWY0N2FlZTliODFlOTc5IiwicGlkIjoiZTMxM2E5NGFhMTA2ZDA4MmExMTY3YzRlYTMwOTYyMjU2M2I5ZmY5YyIsInNpZCI6IjY2MzI1IiwidXQiOjUsImlhdCI6MTU2NTA5MjQwMSwiaXNzIjoiaHR0cHM6Ly9hcGkubGl2ZS5iaW0uc2l0ZSIsInN1YiI6ImFkbWluQGJpbXNpdGUuZGV2In0.Jl98j6UJM8vCRfjiMgs0gIMvvY09N5LGU-t2YxvX5b0/PART38_Loro_20190701_1.VDI; elektrischer Anschluss: nein; Feuerwiderstandsklasse: keine Feuerwiderstandsklasse; Feuerwiderstandsklasse nachrüstbar: nein; Gehäuseanschlussarten: Ablauf punktförmig; Geruchsverschluss: ohne Geruchsverschluss; Heizung: ohne Heizung; Ist System: no; Ist Zubehör: no; Kommentar: Serie 88, Attika-Distant, ohne Aufkantung; Nenndruck: 422; Nenndrucksystem: 270; Nennweitensystem: PN; Potenzialausgleich (Erdungsanschluss) vorhanden: ja; Produktbezeichnung: LORO-RAINSTAR 88 Attikaablauf, ohne Aufkant., Edelst., Klemmfl., Freispiegel, DN100; Produktklassifikation: Attikaablauf; Produktname: LORO-RAINSTAR 88 Attikaablauf, ohne Aufkant., Edelst., Klemmfl., Freispiegel, DN100; Produktvideo: https://media.stage.bim.site/t/eyJhbGciOiJIUzI1NiIsInR5cCI6IkpXVCJ9.eyJjdCI6MiwidHUiOiJodHRwOi8vd3d3Lmxvcm8uZGUvaW5kZXgucGhwP2lkPTIzM1x1MDAyNmFydGlrZWxucj0wMTM5MC4xMDBYIiwiY2lkIjoiMzI3N2NjMjMtODFhOS00ZWUzLWE5MGEtYjQ3YmI0YzBiNjE2IiwicmlkIjoiN2Q5YTcwODg0ODFhMGEzNDMxZjQ3YWVlOWI4MWU5NzkiLCJwaWQiOiJlMzEzYTk0YWExMDZkMDgyYTExNjdjNGVhMzA5NjIyNTYzYjlmZjljIiwic2lkIjoiNjYzMjUiLCJ1dCI6MiwiaWF0IjoxNTY1MDkyNDAxLCJpc3MiOiJodHRwczovL2FwaS5saXZlLmJpbS5zaXRlIiwic3ViIjoiYWRtaW5AYmltc2l0ZS5kZXYifQ._1ocKl-vpR0muEJ6-8qR1rfxTU_H0VxG05urxzZZrKM; Wärmedämmung: ohne Wärmedämmung; Werkstoff des Ablaufkörpers: nicht rostender Stahl
Daten - 38.710.01.13: seitlich; 38.710.01.5: DN; Bestellmenge (Multiplikator): 1; Einbaubreite [m]: 0.24; Einbautiefe [m]: 0; Sperrwasserhöhe [m]: 0
Pset_BuildingElementProxyCommon - Reference: LOROWERK 01390-100X:LOROWERK 01390-100X:259572
AC_Pset_RenovationAndPhasing - Renovation Status: New
Name (LOROWERK 01390-100X:LOROWERK 01390-100X:...) | In
4 x 259572 | Teine korrus
4 x 259572 | Katusekorrus

# IfcBuildingElementProxy: Varikatus_01_02_03_raastas_01_02_03 463 x 518 (8)
Classification: 1.02 IfcBuildingElementProxyType (objekt) (RKAS BIM + ARCHICAD Classification)
AR_Sein - 500_Kandev: yes
Pset_BuildingElementProxyCommon - Reference: Varikatus
AC_Pset_RenovationAndPhasing - Renovation Status: New
Name | In
5 x Varikatus | Esimene korrus
3 x Varikatus | Katusekorrus

# IfcBuildingElementProxy: Varikatus_01_lagi laudis_01 2220 x 21, Varikatus
In: Esimene korrus
Classification: 1.02 IfcBuildingElementProxyType (objekt) (RKAS BIM + ARCHICAD Classification)
AR_Sein - 500_Kandev: yes
Pset_BuildingElementProxyCommon - Reference: Varikatus
AC_Pset_RenovationAndPhasing - Renovation Status: New

# IfcBuildingElementProxy: Varikatus_02_03_lagi laudis_02_03 1800 x 21 (2)
In: Esimene korrus
Classification: 1.02 IfcBuildingElementProxyType (objekt) (RKAS BIM + ARCHICAD Classification)
AR_Sein - 500_Kandev: yes
Pset_BuildingElementProxyCommon - Reference: Varikatus
AC_Pset_RenovationAndPhasing - Renovation Status: New

# IfcBuildingElementProxy: Varikatus_ees_lagi laudis_01 4680 x 21, Varikatus
In: Teine korrus
Classification: 1.02 IfcBuildingElementProxyType (objekt) (RKAS BIM + ARCHICAD Classification)
AR_Sein - 500_Kandev: yes
Pset_BuildingElementProxyCommon - Reference: Varikatus
AC_Pset_RenovationAndPhasing - Renovation Status: New

# IfcBuildingElementProxy: Varikatus_taga_ lagi laudis_01 2517 x 21, Varikatus
In: Esimene korrus
Classification: 1.02 IfcBuildingElementProxyType (objekt) (RKAS BIM + ARCHICAD Classification)
AR_Sein - 500_Kandev: yes
Pset_BuildingElementProxyCommon - Reference: Varikatus
AC_Pset_RenovationAndPhasing - Renovation Status: New

# IfcBuildingElementProxy: Varikatuse_sein 400 (8)
In: Esimene korrus
Classification: 1.02 IfcBuildingElementProxyType (objekt) (RKAS BIM + ARCHICAD Classification)
AR_Sein - 500_Kandev: yes
Pset_BuildingElementProxyCommon - Reference: Varikatus
AC_Pset_RenovationAndPhasing - Renovation Status: New

# IfcBuildingElementProxy: Varikatuse_sein ots 50 (8)
In: Esimene korrus
Classification: 1.02 IfcBuildingElementProxyType (objekt) (RKAS BIM + ARCHICAD Classification); Material: SKR-01_Õhkvahe - Raam
AR_Sein - 500_Kandev: yes
Pset_BuildingElementProxyCommon - Reference: Varikatus
AC_Pset_RenovationAndPhasing - Renovation Status: New

# IfcBuildingElementProxy: Varikatuse_sein ots soojustatud 75 (6)
In: Esimene korrus
Classification: 1.02 IfcBuildingElementProxyType (objekt) (RKAS BIM + ARCHICAD Classification)
AR_Sein - 500_Kandev: yes
Pset_BuildingElementProxyCommon - Reference: Varikatus
AC_Pset_RenovationAndPhasing - Renovation Status: New

# IfcBuildingElementProxy: Varikatuse_sein_olemasolev_300mm plokk 300 (2)
In: Esimene korrus
Classification: 1.02 IfcBuildingElementProxyType (objekt) (RKAS BIM + ARCHICAD Classification); Material: Olemasolev silikaltsiitplokk
AR_Sein - 500_Kandev: yes
Pset_BuildingElementProxyCommon - Reference: Varikatus
AC_Pset_RenovationAndPhasing - Renovation Status: Existing

# IfcBuildingElementProxy: Voodrilaud UYS 21x120mm 20 (8)
In: Esimene korrus
Material: Voodrilaud UYS 21x120mm
AC_Pset_RenovationAndPhasing - Renovation Status: New
Name
6 x Välissein_1
2 x Puitlaudis UYS 20x120mm

# IfcBuildingElementProxy: WC-tagasein 68 (7)
Classification: 1.02 IfcBuildingElementProxyType (objekt) (RKAS BIM + ARCHICAD Classification)
AC_Pset_RenovationAndPhasing - Renovation Status: Existing
Name | In | Reference
AP-02 | Esimene korrus | AP-02 | AR - 001_Nimetus: Aluspõrand
AP-05 | Esimene korrus | AP-05 | AR - 001_Nimetus: Aluspõrand
WC-tagasein | Esimene korrus | WC-tagasein
AP-03 | Esimene korrus | AP-03 | AR - 001_Nimetus: Aluspõrand
2 x SM-2_tagasein | Teine korrus | SM-2_tagasein
WC_tagasein | Teine korrus | WC_tagasein

# IfcColumn: CFRHS50X50X5 50 x 50 (7)
In: Esimene korrus
Type - PredefinedType: COLUMN
Classification: 1.03 IfcColumnType (post) (RKAS BIM + ARCHICAD Classification); Material: VKR-04_Tellis
Pset_ColumnCommon - Slope: 90 deg; LoadBearing: yes; IsExternal: yes; Reference: CFRHS50X50X5 50 x 50
AC_Pset_RenovationAndPhasing - Renovation Status: New

# IfcColumn: ET-02_Raudbetoon - Toode D200 (13)
In: Vundament
Type - PredefinedType: COLUMN
Classification: 1.03 IfcColumnType (post) (RKAS BIM + ARCHICAD Classification); Material: ET-02_Raudbetoon - Toode
Pset_ColumnCommon - Slope: 90 deg; LoadBearing: yes; IsExternal: yes; Reference: ET-02_Raudbetoon - Toode D200
AC_Pset_RenovationAndPhasing - Renovation Status: New

# IfcColumn: ET-05_Teras 100 x 100 (5)
In: Esimene korrus
Type - PredefinedType: COLUMN
Classification: 1.03 IfcColumnType (post) (RKAS BIM + ARCHICAD Classification); Material: ET-05_Teras
Pset_ColumnCommon - Slope: 80 deg; LoadBearing: yes; IsExternal: yes; Reference: ET-05_Teras 100 x 100
AC_Pset_RenovationAndPhasing - Renovation Status: New

# IfcColumn: KON-00_GENEERILINE - KONSTRUKTSIOON 260 x 360, POST
In: Esimene korrus
Type - PredefinedType: COLUMN
Classification: 1.03 IfcColumnType (post) (RKAS BIM + ARCHICAD Classification); Material: KON-00_GENEERILINE - KONSTRUKTSIOON
Pset_ColumnCommon - Slope: 90 deg; LoadBearing: yes; IsExternal: yes; Reference: KON-00_GENEERILINE - KONSTRUKTSIOON 260 x 360
AC_Pset_RenovationAndPhasing - Renovation Status: Existing

# IfcColumn: KON-00_GENEERILINE - KONSTRUKTSIOON 300 x 300 (6)
In: Esimene korrus
Type - PredefinedType: COLUMN
Classification: 1.03 IfcColumnType (post) (RKAS BIM + ARCHICAD Classification); Material: KON-00_GENEERILINE - KONSTRUKTSIOON
Pset_ColumnCommon - Slope: 90 deg; LoadBearing: yes; IsExternal: yes; Reference: KON-00_GENEERILINE - KONSTRUKTSIOON 300 x 300
AC_Pset_RenovationAndPhasing - Renovation Status: Existing

# IfcColumn: KON-00_GENEERILINE - KONSTRUKTSIOON 300 x 360 (10)
In: Esimene korrus
Type - PredefinedType: COLUMN
Classification: 1.03 IfcColumnType (post) (RKAS BIM + ARCHICAD Classification); Material: KON-00_GENEERILINE - KONSTRUKTSIOON
Pset_ColumnCommon - Slope: 90 deg; LoadBearing: yes; IsExternal: yes; Reference: KON-00_GENEERILINE - KONSTRUKTSIOON 300 x 360
AC_Pset_RenovationAndPhasing - Renovation Status: Existing

# IfcColumn: KON-00_GENEERILINE - KONSTRUKTSIOON 360 x 300, POST
In: Esimene korrus
Type - PredefinedType: COLUMN
Classification: 1.03 IfcColumnType (post) (RKAS BIM + ARCHICAD Classification); Material: KON-00_GENEERILINE - KONSTRUKTSIOON
Pset_ColumnCommon - Slope: 90 deg; LoadBearing: yes; IsExternal: yes; Reference: KON-00_GENEERILINE - KONSTRUKTSIOON 360 x 300
AC_Pset_RenovationAndPhasing - Renovation Status: Existing

# IfcColumn: KON-00_GENEERILINE - KONSTRUKTSIOON 360 x 360 (2)
In: Esimene korrus
Type - PredefinedType: COLUMN
Classification: 1.03 IfcColumnType (post) (RKAS BIM + ARCHICAD Classification); Material: KON-00_GENEERILINE - KONSTRUKTSIOON
Pset_ColumnCommon - Slope: 90 deg; LoadBearing: yes; IsExternal: yes; Reference: KON-00_GENEERILINE - KONSTRUKTSIOON 360 x 360
AC_Pset_RenovationAndPhasing - Renovation Status: Existing

# IfcColumn: Olemasolev raudbetoonpost 260 x 360, POST
In: Teine korrus
Type - PredefinedType: COLUMN
Classification: 1.03 IfcColumnType (post) (RKAS BIM + ARCHICAD Classification); Material: Olemasolev raudbetoonpost
Pset_ColumnCommon - Slope: 90 deg; LoadBearing: yes; IsExternal: yes; Reference: Olemasolev raudbetoonpost 260 x 360
AC_Pset_RenovationAndPhasing - Renovation Status: Existing

# IfcColumn: Olemasolev raudbetoonpost 300 x 300 (6)
In: Teine korrus
Type - PredefinedType: COLUMN
Classification: 1.03 IfcColumnType (post) (RKAS BIM + ARCHICAD Classification); Material: Olemasolev raudbetoonpost
Pset_ColumnCommon - Slope: 90 deg; LoadBearing: yes; IsExternal: yes; Reference: Olemasolev raudbetoonpost 300 x 300
AC_Pset_RenovationAndPhasing - Renovation Status: Existing

# IfcColumn: Olemasolev raudbetoonpost 300 x 360 (10)
In: Teine korrus
Type - PredefinedType: COLUMN
Classification: 1.03 IfcColumnType (post) (RKAS BIM + ARCHICAD Classification); Material: Olemasolev raudbetoonpost
Pset_ColumnCommon - Slope: 90 deg; LoadBearing: yes; IsExternal: yes; Reference: Olemasolev raudbetoonpost 300 x 360
AC_Pset_RenovationAndPhasing - Renovation Status: Existing

# IfcColumn: Olemasolev raudbetoonpost 360 x 300, POST
In: Teine korrus
Type - PredefinedType: COLUMN
Classification: 1.03 IfcColumnType (post) (RKAS BIM + ARCHICAD Classification); Material: Olemasolev raudbetoonpost
Pset_ColumnCommon - Slope: 90 deg; LoadBearing: yes; IsExternal: yes; Reference: Olemasolev raudbetoonpost 360 x 300
AC_Pset_RenovationAndPhasing - Renovation Status: Existing

# IfcColumn: Olemasolev raudbetoonpost 360 x 360 (2)
In: Teine korrus
Type - PredefinedType: COLUMN
Classification: 1.03 IfcColumnType (post) (RKAS BIM + ARCHICAD Classification); Material: Olemasolev raudbetoonpost
Pset_ColumnCommon - Slope: 90 deg; LoadBearing: yes; IsExternal: yes; Reference: Olemasolev raudbetoonpost 360 x 360
AC_Pset_RenovationAndPhasing - Renovation Status: Existing

# IfcColumn: Puit konstruktsioon 50 x 25 (2)
In: Esimene korrus
Type - PredefinedType: COLUMN
Classification: 1.03 IfcColumnType (post) (RKAS BIM + ARCHICAD Classification); Material: Puit konstruktsioon
Pset_ColumnCommon - Slope: 90 deg; LoadBearing: yes; IsExternal: yes; Reference: Puit konstruktsioon 50 x 25
AC_Pset_RenovationAndPhasing - Renovation Status: Existing

# IfcColumn: Puit konstruktsioon 50 x 50 (6)
In: Esimene korrus
Type - PredefinedType: COLUMN
Classification: 1.03 IfcColumnType (post) (RKAS BIM + ARCHICAD Classification); Material: Puit konstruktsioon
Pset_ColumnCommon - Slope: 90 deg; LoadBearing: yes; IsExternal: yes; Reference: Puit konstruktsioon 50 x 50
AC_Pset_RenovationAndPhasing - Renovation Status: Existing

# IfcColumn: RHS90X50X5 50 x 90 (6)
In: Esimene korrus
Type - PredefinedType: COLUMN
Classification: 1.03 IfcColumnType (post) (RKAS BIM + ARCHICAD Classification); Material: VKR-04_Tellis
Pset_ColumnCommon - Slope: 90 deg; LoadBearing: yes; IsExternal: yes; Reference: RHS90X50X5 50 x 90
AC_Pset_RenovationAndPhasing - Renovation Status: Existing

# IfcColumn: TORN-KONST 283 x 163 (4)
In: Esimene korrus
Type - PredefinedType: COLUMN
Classification: 1.03 IfcColumnType (post) (RKAS BIM + ARCHICAD Classification); Material: SV-03_Plaat - Põrand
Pset_ColumnCommon - Slope: 82 deg; Reference: TORN-KONST 283 x 163
AC_Pset_RenovationAndPhasing - Renovation Status: Existing

# IfcCovering: VS-02_Cembrit_c040 50 (65)
Classification: 1.07 IfcCoveringType (pinnadetailid) (RKAS BIM + ARCHICAD Classification)
AR_Viimistlus - 200_Materjal (MUDELIS): VKR-06_Õhkvahe; Cembrit_C040
AC_Pset_RenovationAndPhasing - Renovation Status: New
Name | In | 500_Kandev
11 x VS-02 | Esimene korrus | yes
21 x VS-02 | Esimene korrus
11 x VS-02 | Teine korrus
22 x VS-02 | Teine korrus | yes

# IfcCurtainWall: Curtain Wall Type, KLF-01
In: Esimene korrus
Classification: 1.08 IfcCurtainWallType (rippfassaad) (RKAS BIM + ARCHICAD Classification)
AR_Rippfassaad - 001_Nimetus: klaasfassaad
AC_Pset_RenovationAndPhasing - Renovation Status: Existing
Pset_CurtainWallCommon - IsExternal: yes

# IfcDiscreteAccessory: Elbow Tube 23 (3)
In: Esimene korrus
Classification: 1.09 IfcDiscreteAccessoryType (tarvik) (RKAS BIM + ARCHICAD Classification)
AR_001-002 - 002_Tüüp: Päikesepaneel
Pset_QuantityTakeOff - Reference: Päikesepaneel
AC_Pset_RenovationAndPhasing - Renovation Status: Existing

# IfcDiscreteAccessory: Fasaadi logo_valgus_taust_valge 100, Logo valguskast
In: Teine korrus
Classification: 1.09 IfcDiscreteAccessoryType (tarvik) (RKAS BIM + ARCHICAD Classification); Material: Fasaadi logo_valgus_taust_valge
AR_Sein - 500_Kandev: yes
AR_001-002 - 002_Tüüp: Logo valguskast
Pset_QuantityTakeOff - Reference: Logo valguskast
AC_Pset_RenovationAndPhasing - Renovation Status: New

# IfcDiscreteAccessory: Fassaadi infotabloo 1007 x 872, Elektrooniline tabloo
In: Teine korrus
Classification: 1.09 IfcDiscreteAccessoryType (tarvik) (RKAS BIM + ARCHICAD Classification); Material: Hoiatuskiri
AR_Sein - 500_Kandev: yes
AR_001-002 - 002_Tüüp: Elektrooniline tabloo
Pset_QuantityTakeOff - Reference: Elektrooniline tabloo
AC_Pset_RenovationAndPhasing - Renovation Status: New

# IfcDiscreteAccessory: Fassaadi logo_1 995 x 1474, Logo
In: Teine korrus
Classification: 1.09 IfcDiscreteAccessoryType (tarvik) (RKAS BIM + ARCHICAD Classification); Material: Uus_fasaadi logo_valgus_taust_RAL9017 copy (16)
AR_Sein - 500_Kandev: yes
AR_001-002 - 002_Tüüp: Logo
Pset_QuantityTakeOff - Reference: Logo
AC_Pset_RenovationAndPhasing - Renovation Status: New

# IfcDiscreteAccessory: Grid 23 (12)
Classification: 1.09 IfcDiscreteAccessoryType (tarvik) (RKAS BIM + ARCHICAD Classification)
AR_001-002 - 002_Tüüp: Trapp
Pset_QuantityTakeOff - Reference: Trapp
Name | In | Renovation Status
9 x Trapp | Esimene korrus | Existing
Trapp | Esimene korrus | New
2 x Trapp | Teine korrus | Existing

# IfcDiscreteAccessory: RAL7016 100, Elektrooniline tabloo
In: Teine korrus
Classification: 1.09 IfcDiscreteAccessoryType (tarvik) (RKAS BIM + ARCHICAD Classification); Material: RAL7016
AR_Sein - 500_Kandev: yes
AR_001-002 - 002_Tüüp: Elektrooniline tabloo
Pset_QuantityTakeOff - Reference: Elektrooniline tabloo
AC_Pset_RenovationAndPhasing - Renovation Status: New

# IfcDiscreteAccessory: Teras 10 (17)
In: Esimene korrus
Classification: 1.09 IfcDiscreteAccessoryType (tarvik) (RKAS BIM + ARCHICAD Classification); Material: Teras
AR_001-002 - 001_Nimetus: katuslagi; 002_Tüüp: Kinnitus
Pset_QuantityTakeOff - Reference: Kinnitus
AC_Pset_RenovationAndPhasing - Renovation Status: Existing

# IfcDiscreteAccessory: Text 3D 23 (6)
In: Teine korrus
Classification: 1.09 IfcDiscreteAccessoryType (tarvik) (RKAS BIM + ARCHICAD Classification)
AC_Pset_RenovationAndPhasing - Renovation Status: New
Name | 002_Tüüp = Reference
4 x Elektrooniline tabloo | Elektrooniline tabloo
2 x Logo | Logo

# IfcDiscreteAccessory: Tube 23 (2)
In: Esimene korrus
Classification: 1.09 IfcDiscreteAccessoryType (tarvik) (RKAS BIM + ARCHICAD Classification)
AR_001-002 - 002_Tüüp: Päikesepaneel
Pset_QuantityTakeOff - Reference: Päikesepaneel
AC_Pset_RenovationAndPhasing - Renovation Status: Existing

# IfcDistributionFlowElement: Rest_1 (7)
In: Esimene korrus
Type - ElementType: Distribution Flow Element; PredefinedType: USERDEFINED
Classification: Distribution Flow Element (RKAS BIM + ARCHICAD Classification); Material: Teras, ET-05_Teras
AC_Pset_RenovationAndPhasing - Renovation Status: Existing

# IfcDistributionFlowElement: Rest_2, Trapp
In: Esimene korrus
Type - ElementType: Distribution Flow Element; PredefinedType: USERDEFINED
Classification: Distribution Flow Element (RKAS BIM + ARCHICAD Classification); Material: Teras
AC_Pset_RenovationAndPhasing - Renovation Status: Existing

# IfcDoor: Door 23, SU-05p
In: Esimene korrus
Type - OperationType: SINGLE_SWING_LEFT; ParameterTakesPrecedence: no; Sizeable: no
Type - Door Lining Properties - LiningDepth: 115 mm; LiningThickness: 40 mm; LiningOffset: 0 mm; CasingThickness: 50 mm; CasingDepth: 19 mm
Type - Door Panel Properties - Panel 1 - PanelDepth: 40 mm; PanelOperation: SWINGING; PanelWidth: 1; PanelPosition: MIDDLE
OverallHeight: 2100 mm; OverallWidth: 1000 mm; Classification: 1.10 IfcDoorStyle (uks) (RKAS BIM + ARCHICAD Classification)
AR_Uks - 340_Soojusläbivus: 0; 001_Nimetus: siseuks; 002_Tähis: SU-05p; 310_Materjal: puit; 315_Avanemine: ; ARCHICAD tüüp: Side Hung; 320_Klaas: klaasistus puudub; 325_Helipidavus: nõudeid ei esitata; 330_Tulekindlus: nõudeid ei esitata; 335_Välispiire: no; 350_Klaaspakett: klaasistus puudub; 355_Pindala: 2.1 m2; 360_Ratastooliga: no; 365_Isesulguv: no; 370_Evakuatsiooniväljapääs: no; 375_Viimistlus_seest: MUDELIS: RAL 7016; RAL 7016; MÄRKUS: RAL 7016; 376_Viimistlus_väljast: MUDELIS: RAL 7016; RAL 7016; MÄRKUS: RAL 7016; 380_Lukustus: ASSA 565; 900_Tootja: Haapsalu uksetehas; 905_Mudel: Sile spoonitud; 910_Tooteinfo: Undefined; 915_Kasutus-ja_hooldusjuhend: Undefined; 379_Käepide: Assa Abloy Scanflex Iceland; 307_Ava_kõrgus: 2 100; 306_Ava_laius: 1 000; 305_Ava_mõõt: 1 000x2 100
Pset_DoorCommon - ThermalTransmittance: 0; IsExternal: no
AC_Pset_RenovationAndPhasing - Renovation Status: New

# IfcDoor: Door 23, TSU-04p
In: Esimene korrus
Type - OperationType: SINGLE_SWING_LEFT; ParameterTakesPrecedence: no; Sizeable: no
Type - Door Lining Properties - LiningDepth: 115 mm; LiningThickness: 40 mm; LiningOffset: 0 mm
Type - Door Panel Properties - Panel 1 - PanelDepth: 40 mm; PanelOperation: SWINGING; PanelWidth: 1; PanelPosition: MIDDLE
OverallHeight: 2150 mm; OverallWidth: 900 mm; Classification: 1.10 IfcDoorStyle (uks) (RKAS BIM + ARCHICAD Classification)
AR_Uks - 340_Soojusläbivus: 0; 001_Nimetus: tuletõkke siseuks; 002_Tähis: TSU-04p; 310_Materjal: teras; 315_Avanemine: ; ARCHICAD tüüp: Side Hung; 320_Klaas: klaasistus puudub; 325_Helipidavus: 30 dB; 330_Tulekindlus: EI30/Sa; 335_Välispiire: no; 350_Klaaspakett: klaasistus puudub; 355_Pindala: 1.935 m2; 360_Ratastooliga: no; 365_Isesulguv: no; 370_Evakuatsiooniväljapääs: no; 375_Viimistlus_seest: MUDELIS: RAL 7016; RAL 7016; MÄRKUS: vt. SA-osa; 376_Viimistlus_väljast: MUDELIS: RAL 7016; RAL 7016; MÄRKUS: vt. SA-osa; 380_Lukustus: ASSA 565; 900_Tootja: Tammer; 905_Mudel: SMU101; 910_Tooteinfo: Undefined; 915_Kasutus-ja_hooldusjuhend: Undefined; 379_Käepide: Assa Abloy Scanflex Iceland; 307_Ava_kõrgus: 2 150; 306_Ava_laius: 900; 305_Ava_mõõt: 900x2 150
Pset_DoorCommon - ThermalTransmittance: 0; IsExternal: no
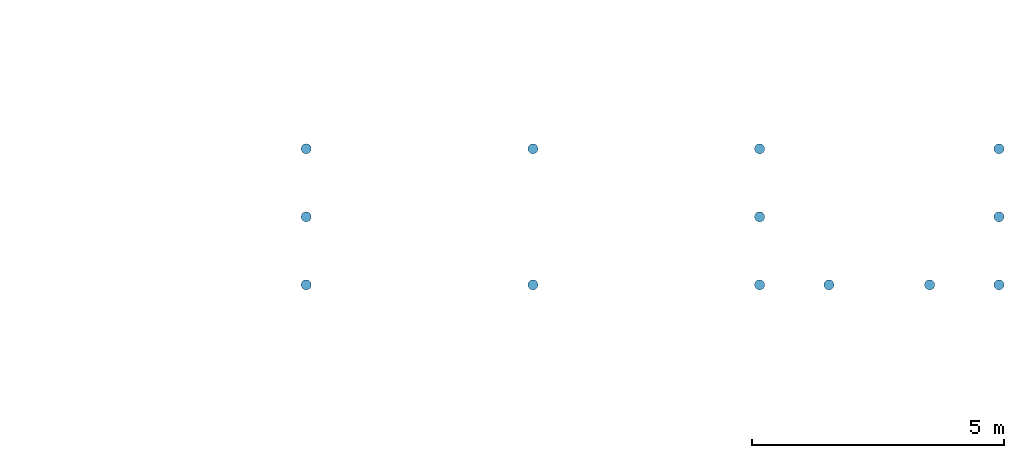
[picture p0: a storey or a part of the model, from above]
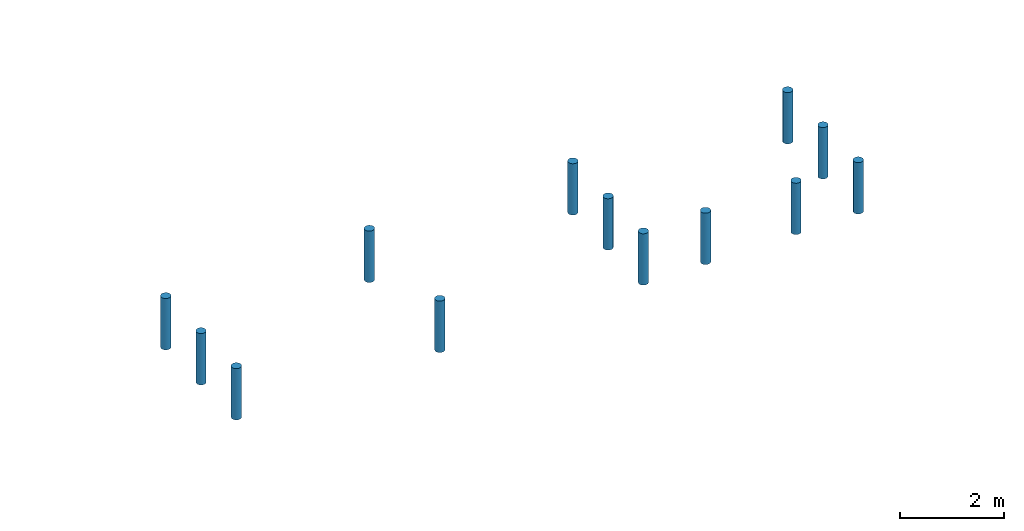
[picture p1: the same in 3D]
Properties of the parts of a building model (IFC2X3), part 2 of 5

# IfcDoor: Door 23, TSU-04p
AC_Pset_RenovationAndPhasing - Renovation Status: New

# IfcDoor: Door 23, SU-05p
In: Teine korrus
Type - OperationType: SINGLE_SWING_LEFT; ParameterTakesPrecedence: no; Sizeable: no
Type - Door Lining Properties - LiningDepth: 115 mm; LiningThickness: 40 mm; LiningOffset: 101 mm; CasingThickness: 50 mm; CasingDepth: 19 mm
Type - Door Panel Properties - Panel 1 - PanelDepth: 40 mm; PanelOperation: SWINGING; PanelWidth: 1; PanelPosition: MIDDLE
OverallHeight: 2100 mm; OverallWidth: 1000 mm; Classification: 1.10 IfcDoorStyle (uks) (RKAS BIM + ARCHICAD Classification)
AR_Uks - 340_Soojusläbivus: 0; 001_Nimetus: siseuks; 002_Tähis: SU-05p; 310_Materjal: puit; 315_Avanemine: ; ARCHICAD tüüp: Side Hung; 320_Klaas: klaasistus puudub; 325_Helipidavus: nõudeid ei esitata; 330_Tulekindlus: nõudeid ei esitata; 335_Välispiire: no; 350_Klaaspakett: klaasistus puudub; 355_Pindala: 2.1 m2; 360_Ratastooliga: no; 365_Isesulguv: no; 370_Evakuatsiooniväljapääs: no; 375_Viimistlus_seest: MUDELIS: RAL 7016; RAL 7016; MÄRKUS: RAL 7016; 376_Viimistlus_väljast: MUDELIS: RAL 7016; RAL 7016; MÄRKUS: RAL 7016; 380_Lukustus: ASSA 565; 900_Tootja: Haapsalu uksetehas; 905_Mudel: Sile spoonitud; 910_Tooteinfo: Undefined; 915_Kasutus-ja_hooldusjuhend: Undefined; 379_Käepide: Assa Abloy Scanflex Iceland; 307_Ava_kõrgus: 2 100; 306_Ava_laius: 1 000; 305_Ava_mõõt: 1 000x2 100
Pset_DoorCommon - ThermalTransmittance: 0; IsExternal: no
AC_Pset_RenovationAndPhasing - Renovation Status: New

# IfcDoor: Door 23, SU-16v
In: Esimene korrus
Type - OperationType: SINGLE_SWING_LEFT; ParameterTakesPrecedence: no; Sizeable: no
Type - Door Lining Properties - LiningDepth: 115 mm; LiningThickness: 40 mm; ThresholdDepth: 75 mm; ThresholdThickness: 20 mm; LiningOffset: 0 mm; ThresholdOffset: 40 mm; CasingThickness: 50 mm; CasingDepth: 19 mm
Type - Door Panel Properties - Panel 1 - PanelDepth: 40 mm; PanelOperation: SWINGING; PanelWidth: 1; PanelPosition: MIDDLE
OverallHeight: 1800 mm; OverallWidth: 600 mm; Classification: 1.10 IfcDoorStyle (uks) (RKAS BIM + ARCHICAD Classification)
AR_Uks - 340_Soojusläbivus: 0; 001_Nimetus: siseuks; 002_Tähis: SU-16v; 310_Materjal: teras soojustatud, U=1,6; 315_Avanemine: ; ARCHICAD tüüp: Side Hung; 320_Klaas: klaasistus puudub; 325_Helipidavus: nõudeid ei esitata; 330_Tulekindlus: nõudeid ei esitata; 335_Välispiire: no; 350_Klaaspakett: klaasistus puudub; 355_Pindala: 1.08 m2; 360_Ratastooliga: no; 365_Isesulguv: no; 370_Evakuatsiooniväljapääs: no; 375_Viimistlus_seest: MUDELIS: RAL 7016; RAL 7016; MÄRKUS: RAL 7016; 376_Viimistlus_väljast: MUDELIS: RAL 7016; RAL 7016; MÄRKUS: RAL 7016; 380_Lukustus: ASSA 565; 900_Tootja: Tammer; 905_Mudel: SMU101; 910_Tooteinfo: Undefined; 915_Kasutus-ja_hooldusjuhend: Undefined; 379_Käepide: Assa Abloy Scanflex Iceland; 307_Ava_kõrgus: 1 800; 306_Ava_laius: 600; 305_Ava_mõõt: 600x1 800
Pset_DoorCommon - ThermalTransmittance: 0; IsExternal: no
AC_Pset_RenovationAndPhasing - Renovation Status: New

# IfcDoor: Door 23 (2)
In: Esimene korrus
Type - OperationType: SINGLE_SWING_LEFT; ParameterTakesPrecedence: no; Sizeable: no
Type - Door Lining Properties - LiningDepth: 115 mm; LiningThickness: 40 mm; ThresholdDepth: 75 mm; ThresholdThickness: 20 mm; LiningOffset: 120 mm; ThresholdOffset: 160 mm
Type - Door Panel Properties - Panel 1 - PanelDepth: 40 mm; PanelOperation: SWINGING; PanelWidth: 1; PanelPosition: MIDDLE
OverallHeight: 2100 mm; OverallWidth: 1250 mm; Classification: 1.10 IfcDoorStyle (uks) (RKAS BIM + ARCHICAD Classification)
AR_Uks - 340_Soojusläbivus: 0; 001_Nimetus: välisuks; 002_Tähis: VU-02p; 310_Materjal: soojustatud teras; 315_Avanemine: ; ARCHICAD tüüp: Side Hung; 320_Klaas: klaasistus puudub; 325_Helipidavus: 34 dB; 330_Tulekindlus: nõudeid ei esitata; 335_Välispiire: yes; 350_Klaaspakett: puudub; 355_Pindala: 2.625 m2; 360_Ratastooliga: no; 365_Isesulguv: no; 370_Evakuatsiooniväljapääs: no; 375_Viimistlus_seest: MUDELIS: RAL 7016; RAL 7016; MÄRKUS: pulbervärvitud RAL7016; 376_Viimistlus_väljast: MUDELIS: RAL 7016; RAL 7016; MÄRKUS: pulbervärvitud RAL7016; 380_Lukustus: EL582 + 411-50; 900_Tootja: Tammer; 905_Mudel: SMU101; 910_Tooteinfo: https://tammer.ee/en/products/smooth-metal-door-smu101-smu201/; 915_Kasutus-ja_hooldusjuhend: Undefined; 379_Käepide: Undefined; 345_Päikesekiirgus_tegur: 0; 307_Ava_kõrgus: 2 100; 306_Ava_laius: 1 250; 305_Ava_mõõt: 1 250x2 100
Pset_DoorCommon - ThermalTransmittance: 0; IsExternal: yes
AC_Pset_RenovationAndPhasing - Renovation Status: New

# IfcDoor: Door 23, TSU-08v
In: Esimene korrus
Type - OperationType: SINGLE_SWING_LEFT; ParameterTakesPrecedence: no; Sizeable: no
Type - Door Lining Properties - LiningDepth: 115 mm; LiningThickness: 40 mm; ThresholdDepth: 75 mm; ThresholdThickness: 20 mm; LiningOffset: 140 mm; ThresholdOffset: 140 mm; CasingThickness: 50 mm; CasingDepth: 19 mm
Type - Door Panel Properties - Panel 1 - PanelDepth: 40 mm; PanelOperation: SWINGING; PanelWidth: 1; PanelPosition: MIDDLE
OverallHeight: 2100 mm; OverallWidth: 800 mm; Classification: 1.10 IfcDoorStyle (uks) (RKAS BIM + ARCHICAD Classification)
AR_Uks - 340_Soojusläbivus: 0; 001_Nimetus: tuletõkke siseuks; 002_Tähis: TSU-08v; 310_Materjal: klaasitud alumiinium; 315_Avanemine: ; ARCHICAD tüüp: Side Hung; 320_Klaas: karastatud; 325_Helipidavus: nõudeid ei esitata; 330_Tulekindlus: EI30/S200; 335_Välispiire: no; 350_Klaaspakett: Polflam 20 EI30 (20 mm); 355_Pindala: 1.68 m2; 360_Ratastooliga: yes; 365_Isesulguv: yes; 370_Evakuatsiooniväljapääs: no; 375_Viimistlus_seest: MUDELIS: RAL 7016; RAL 7016; MÄRKUS: vt. SA-osa; 376_Viimistlus_väljast: MUDELIS: RAL 7016; RAL 7016; MÄRKUS: vt. SA-osa; 380_Lukustus: EL582 + ASSA 851C-50; 900_Tootja: Schüco; 905_Mudel: ADS 80 FR 30; 910_Tooteinfo: Undefined; 915_Kasutus-ja_hooldusjuhend: Undefined; 379_Käepide: Assa Abloy Scanflex Iceland; 307_Ava_kõrgus: 2 100; 306_Ava_laius: 800; 305_Ava_mõõt: 800x2 100
Pset_DoorCommon - ThermalTransmittance: 0; GlazingAreaFraction: 0.963968; IsExternal: no
AC_Pset_RenovationAndPhasing - Renovation Status: New

# IfcDoor: Door 23, SU-11p
In: Esimene korrus
Type - OperationType: SINGLE_SWING_LEFT; ParameterTakesPrecedence: no; Sizeable: no
Type - Door Lining Properties - LiningDepth: 115 mm; LiningThickness: 40 mm; ThresholdDepth: 75 mm; ThresholdThickness: 20 mm; LiningOffset: 170 mm; ThresholdOffset: 210 mm; CasingThickness: 50 mm; CasingDepth: 19 mm
Type - Door Panel Properties - Panel 1 - PanelDepth: 40 mm; PanelOperation: SWINGING; PanelWidth: 1; PanelPosition: MIDDLE
OverallHeight: 2100 mm; OverallWidth: 1000 mm; Classification: 1.10 IfcDoorStyle (uks) (RKAS BIM + ARCHICAD Classification)
AR_Uks - 340_Soojusläbivus: 0; 001_Nimetus: siseuks; 002_Tähis: SU-11p; 310_Materjal: teras; 315_Avanemine: ; ARCHICAD tüüp: Side Hung; 320_Klaas: klaasistus puudub; 325_Helipidavus: 30 dB; 330_Tulekindlus: nõudeid ei esitata; 335_Välispiire: no; 350_Klaaspakett: klaasistus puudub; 355_Pindala: 2.1 m2; 360_Ratastooliga: no; 365_Isesulguv: no; 370_Evakuatsiooniväljapääs: no; 375_Viimistlus_seest: MUDELIS: RAL 7016; RAL 7016; MÄRKUS: RAL 7016; 376_Viimistlus_väljast: MUDELIS: RAL 7016; RAL 7016; MÄRKUS: RAL 7016; 380_Lukustus: EL580; 900_Tootja: Tammer; 905_Mudel: SMU101; 910_Tooteinfo: Undefined; 915_Kasutus-ja_hooldusjuhend: Undefined; 379_Käepide: Assa Abloy Scanflex Iceland; 307_Ava_kõrgus: 2 100; 306_Ava_laius: 1 000; 305_Ava_mõõt: 1 000x2 100
Pset_DoorCommon - ThermalTransmittance: 0; IsExternal: no
AC_Pset_RenovationAndPhasing - Renovation Status: New

# IfcDoor: Door 23, SU-14p
In: Teine korrus
Type - OperationType: SINGLE_SWING_LEFT; ParameterTakesPrecedence: no; Sizeable: no
Type - Door Lining Properties - LiningDepth: 115 mm; LiningThickness: 40 mm; ThresholdDepth: 75 mm; ThresholdThickness: 20 mm; LiningOffset: 200 mm; ThresholdOffset: 240 mm; CasingThickness: 50 mm; CasingDepth: 19 mm
Type - Door Panel Properties - Panel 1 - PanelDepth: 40 mm; PanelOperation: SWINGING; PanelWidth: 1; PanelPosition: MIDDLE
OverallHeight: 2200 mm; OverallWidth: 800 mm; Classification: 1.10 IfcDoorStyle (uks) (RKAS BIM + ARCHICAD Classification)
AR_Uks - 340_Soojusläbivus: 0; 001_Nimetus: siseuks; 002_Tähis: SU-14p; 310_Materjal: puit niiskuskindel; 315_Avanemine: ; ARCHICAD tüüp: Side Hung; 320_Klaas: klaasistus puudub; 325_Helipidavus: 30dB; 330_Tulekindlus: nõudeid ei esitata; 335_Välispiire: no; 350_Klaaspakett: klaasistus puudub; 355_Pindala: 1.76 m2; 360_Ratastooliga: no; 365_Isesulguv: no; 370_Evakuatsiooniväljapääs: no; 375_Viimistlus_seest: MUDELIS: RAL 7016; RAL 7016; MÄRKUS: Abet laminati 1801 giallo ocra; 376_Viimistlus_väljast: MUDELIS: RAL 7016; RAL 7016; MÄRKUS: Abet laminati 1801 giallo ocra; 380_Lukustus: ASSA 565; 900_Tootja: Haaplsau uksetehas; 905_Mudel: Niiskuskindel siseuks; 910_Tooteinfo: Undefined; 915_Kasutus-ja_hooldusjuhend: Undefined; 379_Käepide: Assa Abloy Scanflex Iceland; 307_Ava_kõrgus: 2 200; 306_Ava_laius: 800; 305_Ava_mõõt: 800x2 200
Pset_DoorCommon - ThermalTransmittance: 0; IsExternal: no
AC_Pset_RenovationAndPhasing - Renovation Status: New

# IfcDoor: Door 23, TSU-05p
In: Esimene korrus
Type - OperationType: SINGLE_SWING_LEFT; ParameterTakesPrecedence: no; Sizeable: no
Type - Door Lining Properties - LiningDepth: 115 mm; LiningThickness: 40 mm; ThresholdDepth: 75 mm; ThresholdThickness: 20 mm; LiningOffset: 380 mm; ThresholdOffset: 420 mm
Type - Door Panel Properties - Panel 1 - PanelDepth: 40 mm; PanelOperation: SWINGING; PanelWidth: 1; PanelPosition: MIDDLE
OverallHeight: 2150 mm; OverallWidth: 850 mm; Classification: 1.10 IfcDoorStyle (uks) (RKAS BIM + ARCHICAD Classification)
AR_Uks - 340_Soojusläbivus: 0; 001_Nimetus: tuletõkke siseuks; 002_Tähis: TSU-05p; 310_Materjal: teras; 315_Avanemine: ; ARCHICAD tüüp: Side Hung; 320_Klaas: klaasistus puudub; 325_Helipidavus: 30 dB; 330_Tulekindlus: EI30/Sa; 335_Välispiire: no; 350_Klaaspakett: klaasistus puudub; 355_Pindala: 1.8275 m2; 360_Ratastooliga: no; 365_Isesulguv: no; 370_Evakuatsiooniväljapääs: no; 375_Viimistlus_seest: MUDELIS: RAL 7016; RAL 7016; MÄRKUS: vt. SA-osa; 376_Viimistlus_väljast: MUDELIS: RAL 7016; RAL 7016; MÄRKUS: vt. SA-osa; 380_Lukustus: ASSA 565; 900_Tootja: Tammer; 905_Mudel: SMU101; 910_Tooteinfo: Undefined; 915_Kasutus-ja_hooldusjuhend: Undefined; 379_Käepide: Assa Abloy Scanflex Iceland; 307_Ava_kõrgus: 2 150; 306_Ava_laius: 850; 305_Ava_mõõt: 850x2 150
Pset_DoorCommon - ThermalTransmittance: 0; IsExternal: no
AC_Pset_RenovationAndPhasing - Renovation Status: New

# IfcDoor: Door 23, SU-05p
In: Esimene korrus
Type - OperationType: SINGLE_SWING_LEFT; ParameterTakesPrecedence: no; Sizeable: no
Type - Door Lining Properties - LiningDepth: 95 mm; LiningThickness: 40 mm; LiningOffset: -65 mm; CasingThickness: 50 mm; CasingDepth: 19 mm
Type - Door Panel Properties - Panel 1 - PanelDepth: 40 mm; PanelOperation: SWINGING; PanelWidth: 1; PanelPosition: MIDDLE
OverallHeight: 2100 mm; OverallWidth: 1000 mm; Classification: 1.10 IfcDoorStyle (uks) (RKAS BIM + ARCHICAD Classification)
AR_Uks - 340_Soojusläbivus: 0; 001_Nimetus: siseuks; 002_Tähis: SU-05p; 310_Materjal: puit; 315_Avanemine: ; ARCHICAD tüüp: Side Hung; 320_Klaas: klaasistus puudub; 325_Helipidavus: nõudeid ei esitata; 330_Tulekindlus: nõudeid ei esitata; 335_Välispiire: no; 350_Klaaspakett: klaasistus puudub; 355_Pindala: 2.1 m2; 360_Ratastooliga: no; 365_Isesulguv: no; 370_Evakuatsiooniväljapääs: no; 375_Viimistlus_seest: MUDELIS: RAL 7016; RAL 7016; MÄRKUS: RAL 7016; 376_Viimistlus_väljast: MUDELIS: RAL 7016; RAL 7016; MÄRKUS: RAL 7016; 380_Lukustus: ASSA 565; 900_Tootja: Haapsalu uksetehas; 905_Mudel: Sile spoonitud; 910_Tooteinfo: Undefined; 915_Kasutus-ja_hooldusjuhend: Undefined; 379_Käepide: Assa Abloy Scanflex Iceland; 307_Ava_kõrgus: 2 100; 306_Ava_laius: 1 000; 305_Ava_mõõt: 1 000x2 100
Pset_DoorCommon - ThermalTransmittance: 0; IsExternal: no
AC_Pset_RenovationAndPhasing - Renovation Status: New

# IfcDoor: Door 23, TSU-07p
In: Teine korrus
Type - OperationType: SINGLE_SWING_LEFT; ParameterTakesPrecedence: no; Sizeable: no
Type - Door Lining Properties - LiningDepth: 95 mm; LiningThickness: 40 mm; ThresholdDepth: 33 mm; ThresholdThickness: 20 mm; LiningOffset: 101 mm; ThresholdOffset: 101 mm; CasingThickness: 70 mm; CasingDepth: 19 mm
Type - Door Panel Properties - Panel 1 - PanelDepth: 62 mm; PanelOperation: SWINGING; PanelWidth: 1; PanelPosition: MIDDLE
OverallHeight: 2100 mm; OverallWidth: 1000 mm; Classification: 1.10 IfcDoorStyle (uks) (RKAS BIM + ARCHICAD Classification)
AR_Uks - 340_Soojusläbivus: 0; 001_Nimetus: tuletõkke siseuks; 002_Tähis: TSU-07p; 310_Materjal: teras; 315_Avanemine: ; ARCHICAD tüüp: Side Hung; 320_Klaas: klaasistus puudub; 325_Helipidavus: 30 dB; 330_Tulekindlus: EI30/Sa; 335_Välispiire: no; 350_Klaaspakett: klaaistus puudub; 355_Pindala: 2.1 m2; 360_Ratastooliga: no; 365_Isesulguv: yes; 370_Evakuatsiooniväljapääs: no; 375_Viimistlus_seest: MUDELIS: RAL 7016; RAL 7016; MÄRKUS: vt. SA-osa; 376_Viimistlus_väljast: MUDELIS: RAL 7016; RAL 7016; MÄRKUS: vt. SA-osa; 380_Lukustus: EL480; 900_Tootja: Tammer; 905_Mudel: SMU101; 910_Tooteinfo: Undefined; 915_Kasutus-ja_hooldusjuhend: Undefined; 379_Käepide: Assa Abloy Scanflex Iceland; 307_Ava_kõrgus: 2 100; 306_Ava_laius: 1 000; 305_Ava_mõõt: 1 000x2 100
Pset_DoorCommon - ThermalTransmittance: 0; IsExternal: no
AC_Pset_RenovationAndPhasing - Renovation Status: New

# IfcDoor: Door 23, SU-01p
In: Esimene korrus
Type - OperationType: SINGLE_SWING_LEFT; ParameterTakesPrecedence: no; Sizeable: no
Type - Door Lining Properties - LiningDepth: 95 mm; LiningThickness: 40 mm; ThresholdDepth: 55 mm; ThresholdThickness: 20 mm; LiningOffset: -10 mm; ThresholdOffset: -10 mm
Type - Door Panel Properties - Panel 1 - PanelDepth: 40 mm; PanelOperation: SWINGING; PanelWidth: 1; PanelPosition: MIDDLE
OverallHeight: 2100 mm; OverallWidth: 1250 mm; Classification: 1.10 IfcDoorStyle (uks) (RKAS BIM + ARCHICAD Classification)
AR_Uks - 340_Soojusläbivus: 0; 001_Nimetus: Siseuks; 002_Tähis: SU-01p; 310_Materjal: klaasitud alumiinium; 315_Avanemine: ; ARCHICAD tüüp: Side Hung; 320_Klaas: karastatud; 325_Helipidavus: 30 dB; 330_Tulekindlus: nõudeid ei esitata; 335_Välispiire: no; 350_Klaaspakett: SGG SECURIT 4; 355_Pindala: 2.625 m2; 360_Ratastooliga: no; 365_Isesulguv: yes; 370_Evakuatsiooniväljapääs: no; 375_Viimistlus_seest: MUDELIS: RAL 7016; RAL 7016; MÄRKUS: RAL 7016; 376_Viimistlus_väljast: MUDELIS: RAL 7016; RAL 7016; MÄRKUS: RAL 7016; 380_Lukustus: EL580; 900_Tootja: Schüco; 905_Mudel: ADS 65.NI; 910_Tooteinfo: Undefined; 915_Kasutus-ja_hooldusjuhend: Undefined; 379_Käepide: Assa Abloy Scanflex Iceland; 307_Ava_kõrgus: 2 100; 306_Ava_laius: 1 250; 305_Ava_mõõt: 1 250x2 100
Pset_DoorCommon - ThermalTransmittance: 0; GlazingAreaFraction: 1.71619; IsExternal: no
AC_Pset_RenovationAndPhasing - Renovation Status: New

# IfcDoor: Door 23, SU-17p
In: Esimene korrus
Type - OperationType: SINGLE_SWING_LEFT; ParameterTakesPrecedence: no; Sizeable: no
Type - Door Lining Properties - LiningDepth: 95 mm; LiningThickness: 40 mm; ThresholdDepth: 55 mm; ThresholdThickness: 20 mm; LiningOffset: -5 mm; ThresholdOffset: -5 mm; CasingThickness: 50 mm; CasingDepth: 19 mm
Type - Door Panel Properties - Panel 1 - PanelDepth: 40 mm; PanelOperation: SWINGING; PanelWidth: 1; PanelPosition: MIDDLE
OverallHeight: 2100 mm; OverallWidth: 700 mm; Classification: 1.10 IfcDoorStyle (uks) (RKAS BIM + ARCHICAD Classification)
AR_Uks - 340_Soojusläbivus: 0; 001_Nimetus: siseuks; 002_Tähis: SU-17p; 310_Materjal: puit; 315_Avanemine: ; ARCHICAD tüüp: Side Hung; 320_Klaas: klaasistus puudub; 325_Helipidavus: 30dB; 330_Tulekindlus: nõudeid ei esitata; 335_Välispiire: no; 350_Klaaspakett: klaasistus puudub; 355_Pindala: 1.47 m2; 360_Ratastooliga: no; 365_Isesulguv: no; 370_Evakuatsiooniväljapääs: no; 375_Viimistlus_seest: MUDELIS: Abet Laminati 478; Abet Laminati 478; MÄRKUS: Abet laminati 478 grigio chiaro; 376_Viimistlus_väljast: MUDELIS: Abet Laminati 478; Abet Laminati 478; MÄRKUS: Abet laminati 478 grigio chiaro; 380_Lukustus: ASSA 565; 900_Tootja: Haapsalu uksetehas; 905_Mudel: Sile spoonitud; 910_Tooteinfo: Undefined; 915_Kasutus-ja_hooldusjuhend: Undefined; 379_Käepide: Assa Abloy Scanflex Iceland; 307_Ava_kõrgus: 2 100; 306_Ava_laius: 700; 305_Ava_mõõt: 700x2 100
Pset_DoorCommon - ThermalTransmittance: 0; IsExternal: no
AC_Pset_RenovationAndPhasing - Renovation Status: New

# IfcDoor: Door 23, SU-04p
In: Esimene korrus
Type - OperationType: SINGLE_SWING_LEFT; ParameterTakesPrecedence: no; Sizeable: no
Type - Door Lining Properties - LiningDepth: 95 mm; LiningThickness: 40 mm; ThresholdDepth: 55 mm; ThresholdThickness: 20 mm; LiningOffset: -65 mm; ThresholdOffset: -25 mm; CasingThickness: 50 mm; CasingDepth: 19 mm
Type - Door Panel Properties - Panel 1 - PanelDepth: 40 mm; PanelOperation: SWINGING; PanelWidth: 1; PanelPosition: MIDDLE
OverallHeight: 2100 mm; OverallWidth: 1200 mm; Classification: 1.10 IfcDoorStyle (uks) (RKAS BIM + ARCHICAD Classification)
AR_Uks - 340_Soojusläbivus: 0; 001_Nimetus: siseuks inva; 002_Tähis: SU-04p; 310_Materjal: puit; 315_Avanemine: ; ARCHICAD tüüp: Side Hung; 320_Klaas: klaasistus puudub; 325_Helipidavus: 30dB; 330_Tulekindlus: nõudeid ei esitata; 335_Välispiire: no; 350_Klaaspakett: klaasistus puudub; 355_Pindala: 2.52 m2; 360_Ratastooliga: yes; 365_Isesulguv: no; 370_Evakuatsiooniväljapääs: no; 375_Viimistlus_seest: MUDELIS: RAL 7016; RAL 7016; MÄRKUS: RAL 7016; 376_Viimistlus_väljast: MUDELIS: RAL 7016; RAL 7016; MÄRKUS: RAL 7016; 380_Lukustus: ASSA 565; 900_Tootja: Haapsalu uksetehas; 905_Mudel: Sile spoonitud; 910_Tooteinfo: Undefined; 915_Kasutus-ja_hooldusjuhend: Undefined; 379_Käepide: Assa Abloy Scanflex Iceland; 307_Ava_kõrgus: 2 100; 306_Ava_laius: 1 200; 305_Ava_mõõt: 1 200x2 100
Pset_DoorCommon - ThermalTransmittance: 0; IsExternal: no
AC_Pset_RenovationAndPhasing - Renovation Status: New

# IfcDoor: Door 23 (5)
In: Teine korrus
Type - OperationType: SINGLE_SWING_LEFT; ParameterTakesPrecedence: no; Sizeable: no
Type - Door Lining Properties - LiningDepth: 95 mm; LiningThickness: 40 mm; ThresholdDepth: 55 mm; ThresholdThickness: 20 mm; LiningOffset: 101 mm; ThresholdOffset: 101 mm; CasingThickness: 70 mm; CasingDepth: 19 mm
Type - Door Panel Properties - Panel 1 - PanelDepth: 40 mm; PanelOperation: SWINGING; PanelWidth: 1; PanelPosition: MIDDLE
OverallHeight: 2100 mm; OverallWidth: 1000 mm; Classification: 1.10 IfcDoorStyle (uks) (RKAS BIM + ARCHICAD Classification)
Pset_DoorCommon - ThermalTransmittance: 0; GlazingAreaFraction: 1.31837; IsExternal: no
AR_Uks - 001_Nimetus: siseuks; 002_Tähis: SU-02p; 310_Materjal: klaasitud puit; 315_Avanemine: ; ARCHICAD tüüp: Side Hung; 320_Klaas: karastatud; 325_Helipidavus: 30 dB; 330_Tulekindlus: nõudeid ei esitata; 335_Välispiire: no; 350_Klaaspakett: SGG SECURIT 4; 355_Pindala: 2.1 m2; 360_Ratastooliga: no; 365_Isesulguv: no; 370_Evakuatsiooniväljapääs: no; 375_Viimistlus_seest: MUDELIS: RAL 7016; RAL 7016; MÄRKUS: RAL 7016; 376_Viimistlus_väljast: MUDELIS: RAL 7016; RAL 7016; MÄRKUS: RAL 7016; 380_Lukustus: EL580; 900_Tootja: Haapsalu uksetehas; 905_Mudel: Sile spoonitud 1A; 910_Tooteinfo: Undefined; 915_Kasutus-ja_hooldusjuhend: Undefined; 378_Lävepakk: Tammepuidust, 20mm; 379_Käepide: Assa Abloy Scanflex Iceland; 307_Ava_kõrgus: 2 100; 306_Ava_laius: 1 000; 305_Ava_mõõt: 1 000x2 100
AC_Pset_RenovationAndPhasing - Renovation Status: New

# IfcDoor: Door 23, TSU-01p
In: Esimene korrus
Type - OperationType: SINGLE_SWING_LEFT; ParameterTakesPrecedence: no; Sizeable: no
Type - Door Lining Properties - LiningDepth: 95 mm; LiningThickness: 40 mm; ThresholdDepth: 55 mm; ThresholdThickness: 20 mm; LiningOffset: 105 mm; ThresholdOffset: 145 mm; CasingThickness: 50 mm; CasingDepth: 19 mm
Type - Door Panel Properties - Panel 1 - PanelDepth: 40 mm; PanelOperation: SWINGING; PanelWidth: 1; PanelPosition: MIDDLE
OverallHeight: 2100 mm; OverallWidth: 1250 mm; Classification: 1.10 IfcDoorStyle (uks) (RKAS BIM + ARCHICAD Classification)
AR_Uks - 340_Soojusläbivus: 0; 001_Nimetus: tuletõkke siseuks; 002_Tähis: TSU-01p; 310_Materjal: klaasitud alumiinium; 315_Avanemine: ; ARCHICAD tüüp: Side Hung; 320_Klaas: karastatud; 325_Helipidavus: 30 dB; 330_Tulekindlus: EI30/S200; 335_Välispiire: no; 350_Klaaspakett: Polflam 20 EI30 (20 mm); 355_Pindala: 2.625 m2; 360_Ratastooliga: yes; 365_Isesulguv: yes; 370_Evakuatsiooniväljapääs: no; 375_Viimistlus_seest: MUDELIS: RAL 7016; RAL 7016; MÄRKUS: vt. SA-osa; 376_Viimistlus_väljast: MUDELIS: RAL 7016; RAL 7016; MÄRKUS: vt. SA-osa; 380_Lukustus: EL582 + ASSA 851C-50; 900_Tootja: Schüco; 905_Mudel: ADS 80 FR 30; 910_Tooteinfo: Undefined; 915_Kasutus-ja_hooldusjuhend: Undefined; 379_Käepide: Assa Abloy Scanflex Iceland; 307_Ava_kõrgus: 2 100; 306_Ava_laius: 1 250; 305_Ava_mõõt: 1 250x2 100
Pset_DoorCommon - ThermalTransmittance: 0; GlazingAreaFraction: 1.71619; IsExternal: no
AC_Pset_RenovationAndPhasing - Renovation Status: New

# IfcDoor: Door 23, SU-02v
In: Teine korrus
Type - OperationType: SINGLE_SWING_LEFT; ParameterTakesPrecedence: no; Sizeable: no
Type - Door Lining Properties - LiningDepth: 95 mm; LiningThickness: 40 mm; ThresholdDepth: 55 mm; ThresholdThickness: 20 mm; LiningOffset: 108 mm; ThresholdOffset: 108 mm; CasingThickness: 70 mm; CasingDepth: 19 mm
Type - Door Panel Properties - Panel 1 - PanelDepth: 40 mm; PanelOperation: SWINGING; PanelWidth: 1; PanelPosition: MIDDLE
OverallHeight: 2100 mm; OverallWidth: 1000 mm; Classification: 1.10 IfcDoorStyle (uks) (RKAS BIM + ARCHICAD Classification)
Pset_DoorCommon - ThermalTransmittance: 0; GlazingAreaFraction: 1.31837; IsExternal: no
AR_Uks - 001_Nimetus: siseuks; 002_Tähis: SU-02v; 310_Materjal: klaasitud puit; 315_Avanemine: ; ARCHICAD tüüp: Side Hung; 320_Klaas: karastatud; 325_Helipidavus: 30 dB; 330_Tulekindlus: nõudeid ei esitata; 335_Välispiire: no; 350_Klaaspakett: SGG SECURIT 4; 355_Pindala: 2.1 m2; 360_Ratastooliga: no; 365_Isesulguv: no; 370_Evakuatsiooniväljapääs: no; 375_Viimistlus_seest: MUDELIS: RAL 7016; RAL 7016; MÄRKUS: RAL 7016; 376_Viimistlus_väljast: MUDELIS: RAL 7016; RAL 7016; MÄRKUS: RAL 7016; 380_Lukustus: EL580; 900_Tootja: Haapsalu uksetehas; 905_Mudel: Sile spoonitud 1A; 910_Tooteinfo: Undefined; 915_Kasutus-ja_hooldusjuhend: Undefined; 378_Lävepakk: Tammepuidust, 20mm; 379_Käepide: Assa Abloy Scanflex Iceland; 307_Ava_kõrgus: 2 100; 306_Ava_laius: 1 000; 305_Ava_mõõt: 1 000x2 100
AC_Pset_RenovationAndPhasing - Renovation Status: New

# IfcDoor: Door 23, SU-09v
In: Esimene korrus
Type - OperationType: SINGLE_SWING_RIGHT; ParameterTakesPrecedence: no; Sizeable: no
Type - Door Lining Properties - LiningDepth: 115 mm; LiningThickness: 40 mm; LiningOffset: -180 mm
Type - Door Panel Properties - Panel 1 - PanelDepth: 40 mm; PanelOperation: SWINGING; PanelWidth: 1; PanelPosition: MIDDLE
OverallHeight: 2100 mm; OverallWidth: 800 mm; Classification: 1.10 IfcDoorStyle (uks) (RKAS BIM + ARCHICAD Classification)
AR_Uks - 340_Soojusläbivus: 0; 001_Nimetus: sauna siseuks; 002_Tähis: SU-09v; 310_Materjal: klaas; 315_Avanemine: ; ARCHICAD tüüp: Side Hung; 320_Klaas: kuumakindel karastatud; 325_Helipidavus: nõudeid esitata; 330_Tulekindlus: nõudeid ei esitata; 335_Välispiire: no; 350_Klaaspakett: kuumakindel karastatud; 355_Pindala: 1.68 m2; 360_Ratastooliga: no; 365_Isesulguv: no; 370_Evakuatsiooniväljapääs: no; 375_Viimistlus_seest: MUDELIS: Wood - Pine Grained Horizontal; Glass - Clear Fast; MÄRKUS: RAL 7016; 376_Viimistlus_väljast: MUDELIS: Wood - Pine Grained Horizontal; Glass - Clear Fast; MÄRKUS: RAL 7016; 380_Lukustus: vt. märkused; 900_Tootja: Haapsalu uksetehas; 905_Mudel: Täisklaasuks; 910_Tooteinfo: Undefined; 915_Kasutus-ja_hooldusjuhend: Undefined; 379_Käepide: Assa Abloy Scanflex Iceland; 307_Ava_kõrgus: 2 100; 306_Ava_laius: 800; 305_Ava_mõõt: 800x2 100
Pset_DoorCommon - ThermalTransmittance: 0; IsExternal: no
AC_Pset_RenovationAndPhasing - Renovation Status: New

# IfcDoor: Door 23, SU-12v
In: Esimene korrus
Type - OperationType: SINGLE_SWING_RIGHT; ParameterTakesPrecedence: no; Sizeable: no
Type - Door Lining Properties - LiningDepth: 115 mm; LiningThickness: 40 mm; ThresholdDepth: 75 mm; ThresholdThickness: 20 mm; LiningOffset: 0 mm; ThresholdOffset: 40 mm; CasingThickness: 50 mm; CasingDepth: 19 mm
Type - Door Panel Properties - Panel 1 - PanelDepth: 40 mm; PanelOperation: SWINGING; PanelWidth: 1; PanelPosition: MIDDLE
OverallHeight: 2100 mm; OverallWidth: 1250 mm; Classification: 1.10 IfcDoorStyle (uks) (RKAS BIM + ARCHICAD Classification)
AR_Uks - 340_Soojusläbivus: 0; 001_Nimetus: siseuks; 002_Tähis: SU-12v; 310_Materjal: klaasitud alumiinium; 315_Avanemine: ; ARCHICAD tüüp: Side Hung; 320_Klaas: karastatud; 325_Helipidavus: 30 dB; 330_Tulekindlus: nõudeid ei esitata; 335_Välispiire: no; 350_Klaaspakett: SGG SECURIT 4; 355_Pindala: 2.625 m2; 360_Ratastooliga: yes; 365_Isesulguv: yes; 370_Evakuatsiooniväljapääs: no; 375_Viimistlus_seest: MUDELIS: RAL 7016; RAL 7016; MÄRKUS: RAL 7016; 376_Viimistlus_väljast: MUDELIS: RAL 7016; RAL 7016; MÄRKUS: RAL 7016; 380_Lukustus: EL580; 900_Tootja: Schüco; 905_Mudel: ADS 65.NI; 910_Tooteinfo: Undefined; 915_Kasutus-ja_hooldusjuhend: Undefined; 379_Käepide: Assa Abloy Scanflex Iceland; 307_Ava_kõrgus: 2 100; 306_Ava_laius: 1 250; 305_Ava_mõõt: 1 250x2 100
Pset_DoorCommon - ThermalTransmittance: 0; GlazingAreaFraction: 1.71619; IsExternal: no
AC_Pset_RenovationAndPhasing - Renovation Status: New

# IfcDoor: Door 23, VU-03v
In: Esimene korrus
Type - OperationType: SINGLE_SWING_RIGHT; ParameterTakesPrecedence: no; Sizeable: no
Type - Door Lining Properties - LiningDepth: 115 mm; LiningThickness: 40 mm; ThresholdDepth: 75 mm; ThresholdThickness: 20 mm; LiningOffset: 115 mm; ThresholdOffset: 115 mm
Type - Door Panel Properties - Panel 1 - PanelDepth: 40 mm; PanelOperation: SWINGING; PanelWidth: 1; PanelPosition: MIDDLE
OverallHeight: 2200 mm; OverallWidth: 1250 mm; Classification: 1.10 IfcDoorStyle (uks) (RKAS BIM + ARCHICAD Classification)
AR_Uks - 340_Soojusläbivus: 0; 001_Nimetus: välisuks; 002_Tähis: VU-03v; 310_Materjal: klaasitud alumiinium; 315_Avanemine: ; ARCHICAD tüüp: Side Hung; 320_Klaas: energiasäästu- ja päikesekaitseklaasiga pakett; 325_Helipidavus: 33 dB; 330_Tulekindlus: nõudeid ei esitata; 335_Välispiire: yes; 350_Klaaspakett: SGG CLIMATOP ONE* 4PlthOne-12-4-12-4Plth-One (õhk täidisega); 355_Pindala: 2.75 m2; 360_Ratastooliga: no; 365_Isesulguv: no; 370_Evakuatsiooniväljapääs: no; 375_Viimistlus_seest: MUDELIS: RAL 7016; RAL 7016; MÄRKUS: pulbervärvitud RAL7016; 376_Viimistlus_väljast: MUDELIS: RAL 7016; RAL 7016; MÄRKUS: pulbervärvitud RAL7016; 380_Lukustus: EL582 + ASSA 851C-50; 900_Tootja: Schüco; 905_Mudel: ADS 70.HI; 910_Tooteinfo: https://www.schueco.com/ee/architects/products/doors/aluminium/ads-70-hi#Accordion-173980; 915_Kasutus-ja_hooldusjuhend: Undefined; 379_Käepide: Undefined; 345_Päikesekiirgus_tegur: 0.38; 307_Ava_kõrgus: 2 200; 306_Ava_laius: 1 250; 305_Ava_mõõt: 1 250x2 200
Pset_DoorCommon - ThermalTransmittance: 0; GlazingAreaFraction: 1.86077; IsExternal: yes
AC_Pset_RenovationAndPhasing - Renovation Status: New

# IfcDoor: Door 23 (2)
In: Esimene korrus
Type - OperationType: SINGLE_SWING_RIGHT; ParameterTakesPrecedence: no; Sizeable: no
Type - Door Lining Properties - LiningDepth: 115 mm; LiningThickness: 40 mm; ThresholdDepth: 75 mm; ThresholdThickness: 20 mm; LiningOffset: 115 mm; ThresholdOffset: 155 mm; CasingThickness: 70 mm; CasingDepth: 19 mm
Type - Door Panel Properties - Panel 1 - PanelDepth: 40 mm; PanelOperation: SWINGING; PanelWidth: 1; PanelPosition: MIDDLE
OverallHeight: 2100 mm; OverallWidth: 800 mm; Classification: 1.10 IfcDoorStyle (uks) (RKAS BIM + ARCHICAD Classification)
AR_Uks - 340_Soojusläbivus: 0; 315_Avanemine: ; ARCHICAD tüüp: Side Hung; 320_Klaas: klaasistus puudub; 335_Välispiire: no; 350_Klaaspakett: klaasistus puudub; 355_Pindala: 1.68 m2; 360_Ratastooliga: no; 365_Isesulguv: no; 370_Evakuatsiooniväljapääs: no; 380_Lukustus: ASSA 565; 910_Tooteinfo: Undefined; 915_Kasutus-ja_hooldusjuhend: Undefined; 379_Käepide: Assa Abloy Scanflex Iceland; 307_Ava_kõrgus: 2 100; 306_Ava_laius: 800; 305_Ava_mõõt: 800x2 100
Pset_DoorCommon - ThermalTransmittance: 0; IsExternal: no
AC_Pset_RenovationAndPhasing - Renovation Status: New
Name | 001_Nimetus | 002_Tähis | 310_Materjal | 325_Helipidavus | 330_Tulekindlus | 375_Viimistlus_seest = 376_Viimistlus_väljast | 900_Tootja | 905_Mudel
SU-08v | siseuks | SU-08v | puit | nõudeid ei esitata | nõudeid ei esitata | MUDELIS: RAL 7016; RAL 7016; MÄRKUS: RAL 7016 | Haapsalu uksetehas | Sile spoonitud
TSU-03v | tuletõkke siseuks | TSU-03v | teras niiskuskindel | nõudeid esitata | EI30/Sa | MUDELIS: RAL 7016; RAL 7016; MÄRKUS: vt. SA-osa | Tammer | SMU101

# IfcDoor: Door 23, SU-10v
In: Esimene korrus
Type - OperationType: SINGLE_SWING_RIGHT; ParameterTakesPrecedence: no; Sizeable: no
Type - Door Lining Properties - LiningDepth: 115 mm; LiningThickness: 40 mm; ThresholdDepth: 75 mm; ThresholdThickness: 20 mm; LiningOffset: 170 mm; ThresholdOffset: 210 mm
Type - Door Panel Properties - Panel 1 - PanelDepth: 40 mm; PanelOperation: SWINGING; PanelWidth: 1; PanelPosition: MIDDLE
OverallHeight: 2100 mm; OverallWidth: 1250 mm; Classification: 1.10 IfcDoorStyle (uks) (RKAS BIM + ARCHICAD Classification)
AR_Uks - 340_Soojusläbivus: 0; 001_Nimetus: Siseuks; 002_Tähis: SU-10v; 310_Materjal: klaasitud alumiinium; 315_Avanemine: ; ARCHICAD tüüp: Side Hung; 320_Klaas: karastatud; 325_Helipidavus: 30 dB; 330_Tulekindlus: nõudeid ei esitata; 335_Välispiire: no; 350_Klaaspakett: SGG SECURIT 4; 355_Pindala: 2.625 m2; 360_Ratastooliga: no; 365_Isesulguv: yes; 370_Evakuatsiooniväljapääs: no; 375_Viimistlus_seest: MUDELIS: RAL 7016; RAL 7016; MÄRKUS: RAL 7016; 376_Viimistlus_väljast: MUDELIS: RAL 7016; RAL 7016; MÄRKUS: RAL 7016; 380_Lukustus: EL580; 900_Tootja: Schüco; 905_Mudel: ADS 65.NI; 910_Tooteinfo: Undefined; 915_Kasutus-ja_hooldusjuhend: Undefined; 379_Käepide: Assa Abloy Scanflex Iceland; 307_Ava_kõrgus: 2 100; 306_Ava_laius: 1 250; 305_Ava_mõõt: 1 250x2 100
Pset_DoorCommon - ThermalTransmittance: 0; GlazingAreaFraction: 1.71619; IsExternal: no
AC_Pset_RenovationAndPhasing - Renovation Status: New

# IfcDoor: Door 23, SU-12v
In: Esimene korrus
Type - OperationType: SINGLE_SWING_RIGHT; ParameterTakesPrecedence: no; Sizeable: no
Type - Door Lining Properties - LiningDepth: 115 mm; LiningThickness: 40 mm; ThresholdDepth: 75 mm; ThresholdThickness: 20 mm; LiningOffset: 200 mm; ThresholdOffset: 240 mm; CasingThickness: 50 mm; CasingDepth: 19 mm
Type - Door Panel Properties - Panel 1 - PanelDepth: 40 mm; PanelOperation: SWINGING; PanelWidth: 1; PanelPosition: MIDDLE
OverallHeight: 2100 mm; OverallWidth: 1250 mm; Classification: 1.10 IfcDoorStyle (uks) (RKAS BIM + ARCHICAD Classification)
AR_Uks - 340_Soojusläbivus: 0; 001_Nimetus: siseuks; 002_Tähis: SU-12v; 310_Materjal: klaasitud alumiinium; 315_Avanemine: ; ARCHICAD tüüp: Side Hung; 320_Klaas: karastatud; 325_Helipidavus: 30 dB; 330_Tulekindlus: nõudeid ei esitata; 335_Välispiire: no; 350_Klaaspakett: SGG SECURIT 4; 355_Pindala: 2.625 m2; 360_Ratastooliga: yes; 365_Isesulguv: yes; 370_Evakuatsiooniväljapääs: no; 375_Viimistlus_seest: MUDELIS: RAL 7016; RAL 7016; MÄRKUS: RAL 7016; 376_Viimistlus_väljast: MUDELIS: RAL 7016; RAL 7016; MÄRKUS: RAL 7016; 380_Lukustus: EL580; 900_Tootja: Schüco; 905_Mudel: ADS 65.NI; 910_Tooteinfo: Undefined; 915_Kasutus-ja_hooldusjuhend: Undefined; 379_Käepide: Assa Abloy Scanflex Iceland; 307_Ava_kõrgus: 2 100; 306_Ava_laius: 1 250; 305_Ava_mõõt: 1 250x2 100
Pset_DoorCommon - ThermalTransmittance: 0; GlazingAreaFraction: 1.71619; IsExternal: no
AC_Pset_RenovationAndPhasing - Renovation Status: New

# IfcDoor: Door 23, TSU-02v
In: Esimene korrus
Type - OperationType: SINGLE_SWING_RIGHT; ParameterTakesPrecedence: no; Sizeable: no
Type - Door Lining Properties - LiningDepth: 95 mm; LiningThickness: 40 mm; ThresholdDepth: 55 mm; ThresholdThickness: 20 mm; LiningOffset: -10 mm; ThresholdOffset: -10 mm; CasingThickness: 70 mm; CasingDepth: 19 mm
Type - Door Panel Properties - Panel 1 - PanelDepth: 40 mm; PanelOperation: SWINGING; PanelWidth: 1; PanelPosition: MIDDLE
OverallHeight: 2100 mm; OverallWidth: 1250 mm; Classification: 1.10 IfcDoorStyle (uks) (RKAS BIM + ARCHICAD Classification)
Pset_DoorCommon - ThermalTransmittance: 0; IsExternal: no
AR_Uks - 001_Nimetus: tuletõkke siseuks; 002_Tähis: TSU-02v; 310_Materjal: teras; 315_Avanemine: ; ARCHICAD tüüp: Side Hung; 320_Klaas: klaasistus puudub; 325_Helipidavus: 30 dB; 330_Tulekindlus: EI30/Sa; 335_Välispiire: no; 350_Klaaspakett: klaasistus puudub; 355_Pindala: 2.625 m2; 360_Ratastooliga: no; 365_Isesulguv: yes; 370_Evakuatsiooniväljapääs: no; 375_Viimistlus_seest: MUDELIS: RAL 7016; RAL 7016; MÄRKUS: vt. SA-osa; 376_Viimistlus_väljast: MUDELIS: RAL 7016; RAL 7016; MÄRKUS: vt. SA-osa; 380_Lukustus: EL480; 900_Tootja: Tammer; 905_Mudel: SMU101; 910_Tooteinfo: Undefined; 915_Kasutus-ja_hooldusjuhend: Undefined; 378_Lävepakk: Roostevaba teras, 20mm; 379_Käepide: Assa Abloy Scanflex Iceland; 307_Ava_kõrgus: 2 100; 306_Ava_laius: 1 250; 305_Ava_mõõt: 1 250x2 100
AC_Pset_RenovationAndPhasing - Renovation Status: New

# IfcDoor: Door 23, SU-17v
In: Esimene korrus
Type - OperationType: SINGLE_SWING_RIGHT; ParameterTakesPrecedence: no; Sizeable: no
Type - Door Lining Properties - LiningDepth: 95 mm; LiningThickness: 40 mm; ThresholdDepth: 55 mm; ThresholdThickness: 20 mm; LiningOffset: -5 mm; ThresholdOffset: -5 mm; CasingThickness: 50 mm; CasingDepth: 19 mm
Type - Door Panel Properties - Panel 1 - PanelDepth: 40 mm; PanelOperation: SWINGING; PanelWidth: 1; PanelPosition: MIDDLE
OverallHeight: 2100 mm; OverallWidth: 700 mm; Classification: 1.10 IfcDoorStyle (uks) (RKAS BIM + ARCHICAD Classification)
AR_Uks - 340_Soojusläbivus: 0; 001_Nimetus: siseuks; 002_Tähis: SU-17v; 310_Materjal: puit; 315_Avanemine: ; ARCHICAD tüüp: Side Hung; 320_Klaas: klaasistus puudub; 325_Helipidavus: 30dB; 330_Tulekindlus: nõudeid ei esitata; 335_Välispiire: no; 350_Klaaspakett: klaasistus puudub; 355_Pindala: 1.47 m2; 360_Ratastooliga: no; 365_Isesulguv: no; 370_Evakuatsiooniväljapääs: no; 375_Viimistlus_seest: MUDELIS: Abet Laminati 478; Abet Laminati 478; MÄRKUS: Abet laminati 478 grigio chiaro; 376_Viimistlus_väljast: MUDELIS: Abet Laminati 478; Abet Laminati 478; MÄRKUS: Abet laminati 478 grigio chiaro; 380_Lukustus: ASSA 565; 900_Tootja: Haapsalu uksetehas; 905_Mudel: Sile spoonitud; 910_Tooteinfo: Undefined; 915_Kasutus-ja_hooldusjuhend: Undefined; 379_Käepide: Assa Abloy Scanflex Iceland; 307_Ava_kõrgus: 2 100; 306_Ava_laius: 700; 305_Ava_mõõt: 700x2 100
Pset_DoorCommon - ThermalTransmittance: 0; IsExternal: no
AC_Pset_RenovationAndPhasing - Renovation Status: New

# IfcDoor: Door 23, SU-15v
In: Teine korrus
Type - OperationType: SINGLE_SWING_RIGHT; ParameterTakesPrecedence: no; Sizeable: no
Type - Door Lining Properties - LiningDepth: 95 mm; LiningThickness: 40 mm; ThresholdDepth: 55 mm; ThresholdThickness: 20 mm; LiningOffset: 101 mm; ThresholdOffset: 101 mm; CasingThickness: 70 mm; CasingDepth: 19 mm
Type - Door Panel Properties - Panel 1 - PanelDepth: 40 mm; PanelOperation: SWINGING; PanelWidth: 1; PanelPosition: MIDDLE
OverallHeight: 2100 mm; OverallWidth: 1000 mm; Classification: 1.10 IfcDoorStyle (uks) (RKAS BIM + ARCHICAD Classification)
Pset_DoorCommon - ThermalTransmittance: 0; IsExternal: no
AR_Uks - 001_Nimetus: Siseuks; 002_Tähis: SU-15v; 310_Materjal: puit; 315_Avanemine: ; ARCHICAD tüüp: Side Hung; 320_Klaas: klaasistus puudub; 325_Helipidavus: 30 dB; 330_Tulekindlus: nõudeid ei esitata; 335_Välispiire: no; 350_Klaaspakett: klaasistus puudub; 355_Pindala: 2.1 m2; 360_Ratastooliga: no; 365_Isesulguv: no; 370_Evakuatsiooniväljapääs: no; 375_Viimistlus_seest: MUDELIS: RAL 7016; RAL 7016; MÄRKUS: RAL 7016; 376_Viimistlus_väljast: MUDELIS: RAL 7016; RAL 7016; MÄRKUS: RAL 7016; 380_Lukustus: EL580; 900_Tootja: Haapsalu uksetehas; 905_Mudel: Sile spoonitud; 910_Tooteinfo: Undefined; 915_Kasutus-ja_hooldusjuhend: Undefined; 378_Lävepakk: Tammepuidust, 20mm; 379_Käepide: Assa Abloy Scanflex Iceland; 307_Ava_kõrgus: 2 100; 306_Ava_laius: 1 000; 305_Ava_mõõt: 1 000x2 100
AC_Pset_RenovationAndPhasing - Renovation Status: New

# IfcDoor: Door 23, TSU-01v
In: Esimene korrus
Type - OperationType: SINGLE_SWING_RIGHT; ParameterTakesPrecedence: no; Sizeable: no
Type - Door Lining Properties - LiningDepth: 95 mm; LiningThickness: 40 mm; ThresholdDepth: 55 mm; ThresholdThickness: 20 mm; LiningOffset: 160 mm; ThresholdOffset: 160 mm; CasingThickness: 50 mm; CasingDepth: 19 mm
Type - Door Panel Properties - Panel 1 - PanelDepth: 40 mm; PanelOperation: SWINGING; PanelWidth: 1; PanelPosition: MIDDLE
OverallHeight: 2100 mm; OverallWidth: 1250 mm; Classification: 1.10 IfcDoorStyle (uks) (RKAS BIM + ARCHICAD Classification)
AR_Uks - 340_Soojusläbivus: 0; 001_Nimetus: tuletõkke siseuks; 002_Tähis: TSU-01v; 310_Materjal: klaasitud alumiinium; 315_Avanemine: ; ARCHICAD tüüp: Side Hung; 320_Klaas: karastatud; 325_Helipidavus: 30 dB; 330_Tulekindlus: EI30/S200; 335_Välispiire: no; 350_Klaaspakett: Polflam 20 EI30 (20 mm); 355_Pindala: 2.625 m2; 360_Ratastooliga: yes; 365_Isesulguv: yes; 370_Evakuatsiooniväljapääs: no; 375_Viimistlus_seest: MUDELIS: RAL 7016; RAL 7016; MÄRKUS: vt. SA-osa; 376_Viimistlus_väljast: MUDELIS: RAL 7016; RAL 7016; MÄRKUS: vt. SA-osa; 380_Lukustus: EL582 + ASSA 851C-50; 900_Tootja: Schüco; 905_Mudel: ADS 80 FR 30; 910_Tooteinfo: Undefined; 915_Kasutus-ja_hooldusjuhend: Undefined; 379_Käepide: Assa Abloy Scanflex Iceland; 307_Ava_kõrgus: 2 100; 306_Ava_laius: 1 250; 305_Ava_mõõt: 1 250x2 100
Pset_DoorCommon - ThermalTransmittance: 0; GlazingAreaFraction: 1.71619; IsExternal: no
AC_Pset_RenovationAndPhasing - Renovation Status: New

# IfcDoor: Door 23 (5)
In: Esimene korrus
Type - OperationType: SINGLE_SWING_RIGHT; ParameterTakesPrecedence: no; Sizeable: no
Type - Door Lining Properties - LiningDepth: 95 mm; LiningThickness: 40 mm; ThresholdDepth: 55 mm; ThresholdThickness: 20 mm; LiningOffset: 160 mm; ThresholdOffset: 160 mm; CasingThickness: 70 mm; CasingDepth: 19 mm
Type - Door Panel Properties - Panel 1 - PanelDepth: 40 mm; PanelOperation: SWINGING; PanelWidth: 1; PanelPosition: MIDDLE
OverallHeight: 2100 mm; Classification: 1.10 IfcDoorStyle (uks) (RKAS BIM + ARCHICAD Classification)
AR_Uks - 001_Nimetus: siseuks; 310_Materjal: klaasitud puit; 315_Avanemine: ; ARCHICAD tüüp: Side Hung; 320_Klaas: karastatud; 325_Helipidavus: 30 dB; 330_Tulekindlus: nõudeid ei esitata; 335_Välispiire: no; 350_Klaaspakett: SGG SECURIT 4; 365_Isesulguv: no; 370_Evakuatsiooniväljapääs: no; 375_Viimistlus_seest: MUDELIS: RAL 7016; RAL 7016; MÄRKUS: RAL 7016; 376_Viimistlus_väljast: MUDELIS: RAL 7016; RAL 7016; MÄRKUS: RAL 7016; 380_Lukustus: EL580; 900_Tootja: Haapsalu uksetehas; 905_Mudel: Sile spoonitud 1A; 910_Tooteinfo: Undefined; 915_Kasutus-ja_hooldusjuhend: Undefined; 379_Käepide: Assa Abloy Scanflex Iceland; 307_Ava_kõrgus: 2 100
Pset_DoorCommon - ThermalTransmittance: 0; IsExternal: no
AC_Pset_RenovationAndPhasing - Renovation Status: New
Name | OverallWidth (mm) | 340_Soojusläbivus | 002_Tähis | 355_Pindala (m2) | 360_Ratastooliga | 306_Ava_laius | 305_Ava_mõõt | GlazingAreaFraction
SU-01v | 1200 | 0 | SU-01v | 2.52 | yes | 1 200 | 1 200x2 100 | 1.62809
2 x SU-02v | 1000 | 0 | SU-02v | 2.1 | no | 1 000 | 1 000x2 100 | 1.27569
2 x SU-02v | 1000 |  | SU-02v | 2.1 | no | 1 000 | 1 000x2 100 | 1.27569 | AR_Uks - 378_Lävepakk: Tammepuidust, madaldatud

# IfcDoor: Door 23, SU-07v
In: Esimene korrus
Type - OperationType: SINGLE_SWING_RIGHT; ParameterTakesPrecedence: no; Sizeable: no
Type - Door Lining Properties - LiningDepth: 95 mm; LiningThickness: 40 mm; ThresholdDepth: 55 mm; ThresholdThickness: 20 mm; LiningOffset: 250 mm; ThresholdOffset: 250 mm; CasingThickness: 70 mm; CasingDepth: 19 mm
Type - Door Panel Properties - Panel 1 - PanelDepth: 40 mm; PanelOperation: SWINGING; PanelWidth: 1; PanelPosition: MIDDLE
OverallHeight: 2100 mm; OverallWidth: 950 mm; Classification: 1.10 IfcDoorStyle (uks) (RKAS BIM + ARCHICAD Classification)
AR_Uks - 340_Soojusläbivus: 0; 001_Nimetus: siseuks; 002_Tähis: SU-07v; 310_Materjal: teras; 315_Avanemine: ; ARCHICAD tüüp: Side Hung; 320_Klaas: klaasistus puudub; 325_Helipidavus: nõudeid ei esitata; 330_Tulekindlus: nõudeid ei esitata; 335_Välispiire: no; 350_Klaaspakett: klaasistus puudub; 355_Pindala: 1.995 m2; 360_Ratastooliga: no; 365_Isesulguv: no; 370_Evakuatsiooniväljapääs: no; 375_Viimistlus_seest: MUDELIS: RAL 7016; RAL 7016; MÄRKUS: RAL 7016; 376_Viimistlus_väljast: MUDELIS: RAL 7016; RAL 7016; MÄRKUS: RAL 7016; 380_Lukustus: ASSA 565; 900_Tootja: Tammer; 905_Mudel: SMU101; 910_Tooteinfo: Undefined; 915_Kasutus-ja_hooldusjuhend: Undefined; 379_Käepide: Assa Abloy Scanflex Iceland; 307_Ava_kõrgus: 2 100; 306_Ava_laius: 950; 305_Ava_mõõt: 950x2 100
Pset_DoorCommon - ThermalTransmittance: 0; IsExternal: no
AC_Pset_RenovationAndPhasing - Renovation Status: New

# IfcDoor: Door 23 (2)
In: Teine korrus
Type - OperationType: SINGLE_SWING_RIGHT; ParameterTakesPrecedence: no; Sizeable: no
Type - Door Lining Properties - LiningDepth: 95 mm; LiningThickness: 40 mm; ThresholdDepth: 55 mm; ThresholdThickness: 20 mm; LiningOffset: 305 mm; ThresholdOffset: 345 mm; CasingThickness: 70 mm; CasingDepth: 100 mm
Type - Door Panel Properties - Panel 1 - PanelDepth: 40 mm; PanelOperation: SWINGING; PanelWidth: 1; PanelPosition: MIDDLE
OverallHeight: 2100 mm; OverallWidth: 900 mm; Classification: 1.10 IfcDoorStyle (uks) (RKAS BIM + ARCHICAD Classification)
AR_Uks - 340_Soojusläbivus: 0; 001_Nimetus: siseuks; 310_Materjal: puit; 315_Avanemine: ; ARCHICAD tüüp: Side Hung; 320_Klaas: klaasistus puudub; 325_Helipidavus: 30dB; 330_Tulekindlus: nõudeid ei esitata; 335_Välispiire: no; 350_Klaaspakett: klaasistus puudub; 355_Pindala: 1.89 m2; 360_Ratastooliga: no; 365_Isesulguv: no; 370_Evakuatsiooniväljapääs: no; 380_Lukustus: ASSA 565; 900_Tootja: Haapsalu uksetehas; 905_Mudel: Sile spoonitud; 910_Tooteinfo: Undefined; 915_Kasutus-ja_hooldusjuhend: Undefined; 379_Käepide: Assa Abloy Scanflex Iceland; 307_Ava_kõrgus: 2 100; 306_Ava_laius: 900; 305_Ava_mõõt: 900x2 100
Pset_DoorCommon - ThermalTransmittance: 0; IsExternal: no
AC_Pset_RenovationAndPhasing - Renovation Status: New
Name | 002_Tähis | 375_Viimistlus_seest = 376_Viimistlus_väljast
SU-13p | SU-13p | MUDELIS: Abet Laminati 1801; Abet Laminati 1801; MÄRKUS: RAL 7016
SU-13v | SU-13v | MUDELIS: Abet Laminati 1801; Abet Laminati 1801; MÄRKUS: Abet laminati 1801 giallo ocra

# IfcDoor: Double Door Asymmetric 23, TSU-06p
In: Teine korrus
Type - OperationType: DOUBLE_DOOR_SINGLE_SWING; ParameterTakesPrecedence: no; Sizeable: no
Type - Door Lining Properties - LiningDepth: 115 mm; LiningThickness: 40 mm; ThresholdDepth: 53 mm; ThresholdThickness: 20 mm; LiningOffset: 250 mm; ThresholdOffset: 312 mm; CasingThickness: 70 mm; CasingDepth: 19 mm
Type - Door Panel Properties - Panel 1 - PanelDepth: 62 mm; PanelOperation: SWINGING; PanelWidth: 0.332394; PanelPosition: RIGHT
Type - Door Panel Properties - Panel 2 - PanelDepth: 62 mm; PanelOperation: SWINGING; PanelWidth: 0.684507; PanelPosition: LEFT
OverallHeight: 2100 mm; OverallWidth: 1500 mm; Classification: 1.10 IfcDoorStyle (uks) (RKAS BIM + ARCHICAD Classification)
AR_Uks - 340_Soojusläbivus: 0; 001_Nimetus: tuletõkke siseuks; 002_Tähis: TSU-06p; 310_Materjal: klaasitud alumiinium; 315_Avanemine: ; ARCHICAD tüüp: Side Hung; 320_Klaas: karastatud; 325_Helipidavus: 30 dB; 330_Tulekindlus: EI30/S200; 335_Välispiire: no; 350_Klaaspakett: Polflam 20 EI30 (20 mm); 355_Pindala: 3.15 m2; 360_Ratastooliga: no; 365_Isesulguv: yes; 370_Evakuatsiooniväljapääs: no; 375_Viimistlus_seest: MUDELIS: RAL 7016; RAL 7016; MÄRKUS: vt. SA-osa; 376_Viimistlus_väljast: MUDELIS: RAL 7016; RAL 7016; MÄRKUS: vt. SA-osa; 380_Lukustus: EL582 + ASSA 851C-50; 900_Tootja: Schüco; 905_Mudel: ADS 80 FR 30; 910_Tooteinfo: Undefined; 915_Kasutus-ja_hooldusjuhend: Undefined; 379_Käepide: Assa Abloy Scanflex Iceland; 307_Ava_kõrgus: 2 100; 306_Ava_laius: 1 500; 305_Ava_mõõt: 1 500x2 100
Pset_DoorCommon - ThermalTransmittance: 0; GlazingAreaFraction: 1.84997; IsExternal: no
AC_Pset_RenovationAndPhasing - Renovation Status: New

# IfcDoor: Double Door Asymmetric 23, VU-05v
In: Esimene korrus
Type - OperationType: DOUBLE_DOOR_SINGLE_SWING; ParameterTakesPrecedence: no; Sizeable: no
Type - Door Lining Properties - LiningDepth: 115 mm; LiningThickness: 40 mm; ThresholdDepth: 75 mm; ThresholdThickness: 20 mm; LiningOffset: 115 mm; ThresholdOffset: 115 mm
Type - Door Panel Properties - Panel 1 - PanelDepth: 40 mm; PanelOperation: SWINGING; PanelWidth: 0.332394; PanelPosition: LEFT
Type - Door Panel Properties - Panel 2 - PanelDepth: 40 mm; PanelOperation: SWINGING; PanelWidth: 0.684507; PanelPosition: RIGHT
OverallHeight: 2100 mm; OverallWidth: 1500 mm; Classification: 1.10 IfcDoorStyle (uks) (RKAS BIM + ARCHICAD Classification)
AR_Uks - 340_Soojusläbivus: 0; 001_Nimetus: välisuks; 002_Tähis: VU-05v; 310_Materjal: klaasitud alumiinium; 315_Avanemine: ; ARCHICAD tüüp: Side Hung; 320_Klaas: energiasäästu- ja päikesekaitseklaasiga pakett; 325_Helipidavus: 33 dB; 330_Tulekindlus: nõudeid ei esitata; 335_Välispiire: yes; 350_Klaaspakett: SGG CLIMATOP ONE* 4PlthOne-12-4-12-4Plth-One (õhk täidisega); 355_Pindala: 3.15 m2; 360_Ratastooliga: yes; 365_Isesulguv: no; 370_Evakuatsiooniväljapääs: no; 375_Viimistlus_seest: MUDELIS: RAL 7016; RAL 7016; MÄRKUS: pulbervärvitud RAL7016; 376_Viimistlus_väljast: MUDELIS: RAL 7016; RAL 7016; MÄRKUS: pulbervärvitud RAL7016; 380_Lukustus: EL582 + ASSA 851C-50; 900_Tootja: Schüco; 905_Mudel: ADS 70.HI; 910_Tooteinfo: https://www.schueco.com/ee/architects/products/doors/aluminium/ads-70-hi#Accordion-173980; 915_Kasutus-ja_hooldusjuhend: Undefined; 379_Käepide: Undefined; 345_Päikesekiirgus_tegur: 0.38; 307_Ava_kõrgus: 2 100; 306_Ava_laius: 1 500; 305_Ava_mõõt: 1 500x2 100
Pset_DoorCommon - ThermalTransmittance: 0; GlazingAreaFraction: 1.84997; IsExternal: yes
AC_Pset_RenovationAndPhasing - Renovation Status: New

# IfcDoor: Double Door Asymmetric 23, VU-04p
In: Esimene korrus
Type - OperationType: DOUBLE_DOOR_SINGLE_SWING; ParameterTakesPrecedence: no; Sizeable: no
Type - Door Lining Properties - LiningDepth: 115 mm; LiningThickness: 40 mm; ThresholdDepth: 75 mm; ThresholdThickness: 20 mm; LiningOffset: 115 mm; ThresholdOffset: 115 mm
Type - Door Panel Properties - Panel 1 - PanelDepth: 40 mm; PanelOperation: SWINGING; PanelWidth: 0.332394; PanelPosition: RIGHT
Type - Door Panel Properties - Panel 2 - PanelDepth: 40 mm; PanelOperation: SWINGING; PanelWidth: 0.684507; PanelPosition: LEFT
OverallHeight: 2100 mm; OverallWidth: 1500 mm; Classification: 1.10 IfcDoorStyle (uks) (RKAS BIM + ARCHICAD Classification)
AR_Uks - 340_Soojusläbivus: 0; 001_Nimetus: välisuks; 002_Tähis: VU-04p; 310_Materjal: soojustatud teras; 315_Avanemine: ; ARCHICAD tüüp: Side Hung; 320_Klaas: klaasistus puudub; 325_Helipidavus: 34 dB; 330_Tulekindlus: nõudeid ei esitata; 335_Välispiire: yes; 350_Klaaspakett: puudub; 355_Pindala: 3.15 m2; 360_Ratastooliga: no; 365_Isesulguv: no; 370_Evakuatsiooniväljapääs: no; 375_Viimistlus_seest: MUDELIS: RAL 7016; RAL 7016; MÄRKUS: pulbervärvitud RAL7016; 376_Viimistlus_väljast: MUDELIS: RAL 7016; RAL 7016; MÄRKUS: pulbervärvitud RAL7016; 380_Lukustus: EL582 + 411-50; 900_Tootja: Tammer; 905_Mudel: SMU201; 910_Tooteinfo: https://tammer.ee/en/products/smooth-metal-door-smu101-smu201/; 915_Kasutus-ja_hooldusjuhend: Undefined; 379_Käepide: Undefined; 345_Päikesekiirgus_tegur: 0; 307_Ava_kõrgus: 2 100; 306_Ava_laius: 1 500; 305_Ava_mõõt: 1 500x2 100
Pset_DoorCommon - ThermalTransmittance: 0; IsExternal: yes
AC_Pset_RenovationAndPhasing - Renovation Status: New

# IfcDoor: Double Door Asymmetric 23, SU-03v
In: Esimene korrus
Type - OperationType: DOUBLE_DOOR_SINGLE_SWING; ParameterTakesPrecedence: no; Sizeable: no
Type - Door Lining Properties - LiningDepth: 95 mm; LiningThickness: 40 mm; LiningOffset: -10 mm; CasingThickness: 50 mm; CasingDepth: 19 mm
Type - Door Panel Properties - Panel 1 - PanelDepth: 40 mm; PanelOperation: SWINGING; PanelWidth: 0.421429; PanelPosition: LEFT
Type - Door Panel Properties - Panel 2 - PanelDepth: 40 mm; PanelOperation: SWINGING; PanelWidth: 0.595714; PanelPosition: RIGHT
OverallHeight: 2200 mm; OverallWidth: 1500 mm; Classification: 1.10 IfcDoorStyle (uks) (RKAS BIM + ARCHICAD Classification)
AR_Uks - 340_Soojusläbivus: 0; 001_Nimetus: siseuks; 002_Tähis: SU-03v; 310_Materjal: teras; 315_Avanemine: ; ARCHICAD tüüp: Side Hung; 320_Klaas: klaasistus puudub; 325_Helipidavus: nõudeid ei esitata; 330_Tulekindlus: nõudeid ei esitata; 335_Välispiire: no; 350_Klaaspakett: klaasistus puudub; 355_Pindala: 3.3 m2; 360_Ratastooliga: no; 365_Isesulguv: no; 370_Evakuatsiooniväljapääs: no; 375_Viimistlus_seest: MUDELIS: RAL 7016; RAL 7016; MÄRKUS: vt. SA-osa; 376_Viimistlus_väljast: MUDELIS: RAL 7016; RAL 7016; MÄRKUS: vt. SA-osa; 380_Lukustus: ASSA 565; 900_Tootja: Tammer; 905_Mudel: SMU201; 910_Tooteinfo: Undefined; 915_Kasutus-ja_hooldusjuhend: Undefined; 379_Käepide: Assa Abloy Scanflex Iceland; 307_Ava_kõrgus: 2 200; 306_Ava_laius: 1 500; 305_Ava_mõõt: 1 500x2 200
Pset_DoorCommon - ThermalTransmittance: 0; IsExternal: no
AC_Pset_RenovationAndPhasing - Renovation Status: New

# IfcDoor: Double Door Asymmetric 23, SU-03p
In: Esimene korrus
Type - OperationType: DOUBLE_DOOR_SINGLE_SWING; ParameterTakesPrecedence: no; Sizeable: no
Type - Door Lining Properties - LiningDepth: 95 mm; LiningThickness: 40 mm; LiningOffset: -10 mm; CasingThickness: 50 mm; CasingDepth: 19 mm
Type - Door Panel Properties - Panel 1 - PanelDepth: 40 mm; PanelOperation: SWINGING; PanelWidth: 0.421429; PanelPosition: RIGHT
Type - Door Panel Properties - Panel 2 - PanelDepth: 40 mm; PanelOperation: SWINGING; PanelWidth: 0.595714; PanelPosition: LEFT
OverallHeight: 2200 mm; OverallWidth: 1500 mm; Classification: 1.10 IfcDoorStyle (uks) (RKAS BIM + ARCHICAD Classification)
AR_Uks - 340_Soojusläbivus: 0; 001_Nimetus: siseuks; 002_Tähis: SU-03p; 310_Materjal: teras; 315_Avanemine: ; ARCHICAD tüüp: Side Hung; 320_Klaas: klaasistus puudub; 325_Helipidavus: nõudeid ei esitata; 330_Tulekindlus: nõudeid ei esitata; 335_Välispiire: no; 350_Klaaspakett: klaasistus puudub; 355_Pindala: 3.3 m2; 360_Ratastooliga: no; 365_Isesulguv: no; 370_Evakuatsiooniväljapääs: no; 375_Viimistlus_seest: MUDELIS: RAL 7016; RAL 7016; MÄRKUS: RAL 7016; 376_Viimistlus_väljast: MUDELIS: RAL 7016; RAL 7016; MÄRKUS: RAL 7016; 380_Lukustus: ASSA 565; 900_Tootja: Tammer; 905_Mudel: SMU201; 910_Tooteinfo: Undefined; 915_Kasutus-ja_hooldusjuhend: Undefined; 379_Käepide: Assa Abloy Scanflex Iceland; 307_Ava_kõrgus: 2 200; 306_Ava_laius: 1 500; 305_Ava_mõõt: 1 500x2 200
Pset_DoorCommon - ThermalTransmittance: 0; IsExternal: no
AC_Pset_RenovationAndPhasing - Renovation Status: New

# IfcDoor: Double Door with 2 Sidelights, Transom 23, VU-01
In: Esimene korrus
Type - OperationType: USERDEFINED; ParameterTakesPrecedence: no; Sizeable: no
OverallHeight: 2550 mm; OverallWidth: 2430 mm; Classification: 1.10 IfcDoorStyle (uks) (RKAS BIM + ARCHICAD Classification)
AR_Uks - 340_Soojusläbivus: 0; 001_Nimetus: välisuks; 002_Tähis: VU-01; 310_Materjal: klaasitud alumiinium; 315_Avanemine: ; ARCHICAD tüüp: Side Hung; 320_Klaas: mürasummutus kolmekordne klaaspakett; 325_Helipidavus: 41 dB; 330_Tulekindlus: nõudeid ei esitata; 335_Välispiire: yes; 350_Klaaspakett: SGG CLIMATOP ACOUSTIC 44.2-12Ar-4-15Ar-6PlthXN (argoon 90% täidisega); 355_Pindala: 6.1965 m2; 360_Ratastooliga: yes; 365_Isesulguv: yes; 370_Evakuatsiooniväljapääs: no; 375_Viimistlus_seest: MUDELIS: RAL 7016; RAL 7016; MÄRKUS: pulbervärvitud RAL 7016; 376_Viimistlus_väljast: MUDELIS: RAL 7016; RAL 7016; MÄRKUS: pulbervärvitud RAL 7016; 380_Lukustus: EL582 + ASSA 851C-50; 900_Tootja: Schüco; 905_Mudel: ADS 70.HI; 910_Tooteinfo: https://www.schueco.com/ee/architects/products/doors/aluminium/ads-70-hi#Accordion-173980; 915_Kasutus-ja_hooldusjuhend: Undefined; 379_Käepide: Undefined; 345_Päikesekiirgus_tegur: 0.64; 307_Ava_kõrgus: 2 550; 306_Ava_laius: 2 430; 305_Ava_mõõt: 2 430x2 550
Pset_DoorCommon - ThermalTransmittance: 0; GlazingAreaFraction: 4.3561; IsExternal: yes
AC_Pset_RenovationAndPhasing - Renovation Status: New

# IfcDoor: Double Door with Transom 23, VU-06v
In: Teine korrus
Type - OperationType: DOUBLE_DOOR_SINGLE_SWING; ParameterTakesPrecedence: no; Sizeable: no
Type - Door Lining Properties - LiningDepth: 115 mm; LiningThickness: 40 mm; ThresholdDepth: 75 mm; ThresholdThickness: 20 mm; TransomThickness: 40 mm; TransomOffset: 2100 mm; LiningOffset: 120 mm; ThresholdOffset: 160 mm
Type - Door Panel Properties - Panel 1 - PanelDepth: 40 mm; PanelOperation: SWINGING; PanelWidth: 0.281818; PanelPosition: LEFT
Type - Door Panel Properties - Panel 2 - PanelDepth: 40 mm; PanelOperation: SWINGING; PanelWidth: 0.736364; PanelPosition: RIGHT
OverallHeight: 2580 mm; OverallWidth: 1400 mm; Classification: 1.10 IfcDoorStyle (uks) (RKAS BIM + ARCHICAD Classification)
AR_Uks - 340_Soojusläbivus: 0; 001_Nimetus: välisuks; 002_Tähis: VU-06v; 310_Materjal: klaasitud alumiinium; 315_Avanemine: ; ARCHICAD tüüp: Side Hung; 320_Klaas: energiasäästu- ja päikesekaitseklaasiga pakett; 325_Helipidavus: 33 dB; 330_Tulekindlus: nõudeid ei esitata; 335_Välispiire: yes; 350_Klaaspakett: SGG CLIMATOP ONE* 4PlthOne-12-4-12-4Plth-One (õhk täidisega); 355_Pindala: 3.612 m2; 360_Ratastooliga: no; 365_Isesulguv: yes; 370_Evakuatsiooniväljapääs: no; 375_Viimistlus_seest: MUDELIS: RAL 7016; RAL 7016; MÄRKUS: pulbervärvitud RAL7016; 376_Viimistlus_väljast: MUDELIS: RAL 7016; RAL 7016; MÄRKUS: pulbervärvitud RAL7016; 380_Lukustus: EL582 + ASSA 851C-50; 900_Tootja: Schüco; 905_Mudel: ADS 70.HI; 910_Tooteinfo: https://www.schueco.com/ee/architects/products/doors/aluminium/ads-70-hi#Accordion-173980; 915_Kasutus-ja_hooldusjuhend: Undefined; 379_Käepide: Undefined; 345_Päikesekiirgus_tegur: 0.38; 307_Ava_kõrgus: 2 580; 306_Ava_laius: 1 400; 305_Ava_mõõt: 1 400x2 580
Pset_DoorCommon - ThermalTransmittance: 0; GlazingAreaFraction: 2.23853; IsExternal: yes
AC_Pset_RenovationAndPhasing - Renovation Status: New

# IfcDoor: Nassau 9000 nosto-ovi (3)
In: Esimene korrus
Type - ParameterTakesPrecedence: no; Sizeable: no
Classification: 1.10 IfcDoorStyle (uks) (RKAS BIM + ARCHICAD Classification)
AR_Uks - 340_Soojusläbivus: 0; 001_Nimetus: välis tõstuks; 310_Materjal: soojustatud alumiinium; 320_Klaas: klaasistus puudub; 325_Helipidavus: nõudeid ei esitata; 330_Tulekindlus: nõudeid ei esitata; 335_Välispiire: yes; 350_Klaaspakett: puudub; 360_Ratastooliga: no; 365_Isesulguv: no; 370_Evakuatsiooniväljapääs: no; 375_Viimistlus_seest: pulbervärvitud RAL7016; 376_Viimistlus_väljast: MUDELIS: 0; 0; MÄRKUS: pulbervärvitud RAL7016; 380_Lukustus: vastavalt tootele; 900_Tootja: Nassau; 905_Mudel: Nassau 9000 F; 910_Tooteinfo: https://nassaudoor.com/industrial-doors/sectional-doors/nassau-9000f-2/; 915_Kasutus-ja_hooldusjuhend: Undefined; 379_Käepide: Undefined; 345_Päikesekiirgus_tegur: 0
AC_Pset_RenovationAndPhasing - Renovation Status: New
Pset_DoorCommon - IsExternal: yes
Name | OverallHeight (mm) | OverallWidth (mm) | 002_Tähis | 355_Pindala (m2) | 307_Ava_kõrgus | 306_Ava_laius | 305_Ava_mõõt
2 x VU-08 | 2600 | 2980 | VU-08 | 7.748 | 2 600 | 2 980 | 2 980x2 600
VU-07 | 2560 | 2650 | VU-07 | 6.784 | 2 560 | 2 650 | 2 650x2 560

# IfcDoor: Sliding Door 23, SU-04v
In: Teine korrus
Type - OperationType: USERDEFINED; ParameterTakesPrecedence: no; Sizeable: no
OverallHeight: 2100 mm; OverallWidth: 3102 mm; Classification: 1.10 IfcDoorStyle (uks) (RKAS BIM + ARCHICAD Classification)
Pset_DoorCommon - ThermalTransmittance: 0; GlazingAreaFraction: 3.91072; IsExternal: no
AR_Uks - 001_Nimetus: siseuks; 002_Tähis: SU-04v; 310_Materjal: klaasitud puit; 315_Avanemine: ; ARCHICAD tüüp: 4 Leaves 3 Sliding; 320_Klaas: karastatud; 325_Helipidavus: 30 dB; 330_Tulekindlus: nõudeid ei esitata; 335_Välispiire: no; 350_Klaaspakett: SGG SECURIT 4; 355_Pindala: 6.5142 m2; 360_Ratastooliga: no; 365_Isesulguv: no; 370_Evakuatsiooniväljapääs: no; 375_Viimistlus_seest: MUDELIS: Wood - Pine Grained Horizontal; Wood - Pine Grained Horizontal; MÄRKUS: vt. SA-osa; 376_Viimistlus_väljast: MUDELIS: Wood - Pine Grained Horizontal; Wood - Pine Grained Horizontal; MÄRKUS: vt. SA-osa; 380_Lukustus: EL580; 900_Tootja: Haapsalu uksetehas; 905_Mudel: Sile spoonitud 1A; 910_Tooteinfo: Undefined; 915_Kasutus-ja_hooldusjuhend: Undefined; 378_Lävepakk: Tammepuidust, 20mm; 379_Käepide: Assa Abloy Scanflex Iceland; 307_Ava_kõrgus: 2 100; 306_Ava_laius: 3 102; 305_Ava_mõõt: 3 102x2 100
AC_Pset_RenovationAndPhasing - Renovation Status: New

# IfcFlowTerminal: Model Element 1 (7)
Type - ElementType: Flow Terminal; PredefinedType: USERDEFINED
Classification: Flow Terminal (RKAS BIM + ARCHICAD Classification); Material: IFC Building Material
Pset_ManufacturerTypeInformation - Manufacturer: LOROWERK K.H. Vahlbrauk GmbH & Co. KG
Pset_DistributionFlowElementCommon - Reference: LOROWERK 01390-100X
Abhängigkeiten - Basisbauteil: Ebene : Ebene 1; Ebene: Ebene: Ebene 1; Versatz: 0 mm
Abmessungen - Fläche: 0.306423 m2; Volumen: 0.0277664 m3; CONNECTOR0_DIAMETER_dZ_0r: 100 mm; CONNECTOR0_dZ_00: 14 mm; CONNECTOR0_dZ_01: 14.7937 mm; CONNECTOR0_ref_dZ: 14.7937 mm; CONNECTOR1_DIAMETER_dNBN0_0r: 100 mm; CONNECTOR1_dNBN0_00: 213.222 mm; CONNECTOR1_dNBN0_01: 287.222 mm; CONNECTOR1_ref_dNBN0: 213.222 mm; CONNECTOR1_ref_dNBN1: 54.042 mm
HLS - Systemklassifizierung: Nicht definiert
ID-Daten - Kennzeichen: 19; Beschreibung: LORO-RAINSTAR Attikaabläufe, Serie 88, Attika-Distant, ohne Aufkantung; DATANORM: 01390.100X; GTIN: 4038088074183; HAN: 01390.100X; Hersteller: LOROWERK K.H. Vahlbrauk GmbH & Co. KG; Typname: LOROWERK 01390-100X; VDIBSN: 0020090000020010000010020010010000000030020000000300000001
Phasen - Phase erstellt: Neue Konstruktion
Sonstige - Familie: LOROWERK 01390-100X: LOROWERK 01390-100X; Familie und Typ: LOROWERK 01390-100X: LOROWERK 01390-100X; Kategorie: Sanitärinstallationen; Typ: LOROWERK 01390-100X: LOROWERK 01390-100X; Typ-ID: LOROWERK 01390-100X: LOROWERK 01390-100X; Familienname: LOROWERK 01390-100X
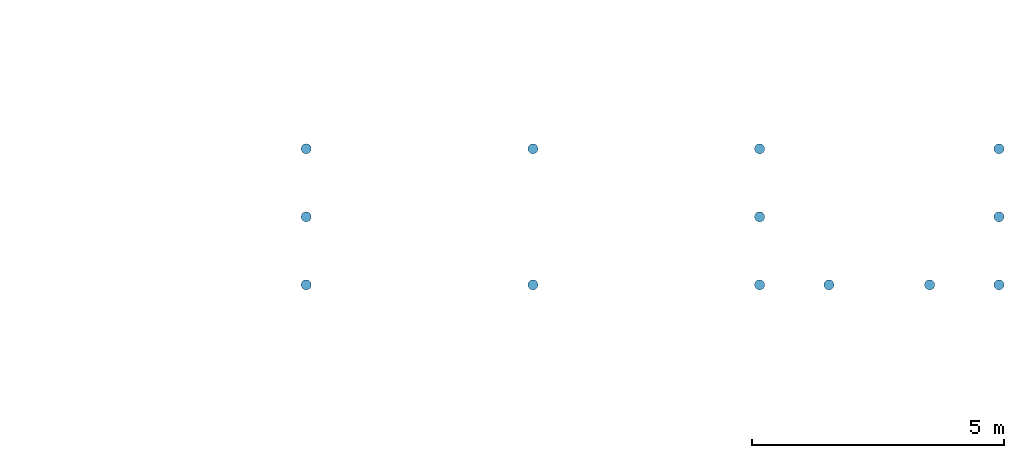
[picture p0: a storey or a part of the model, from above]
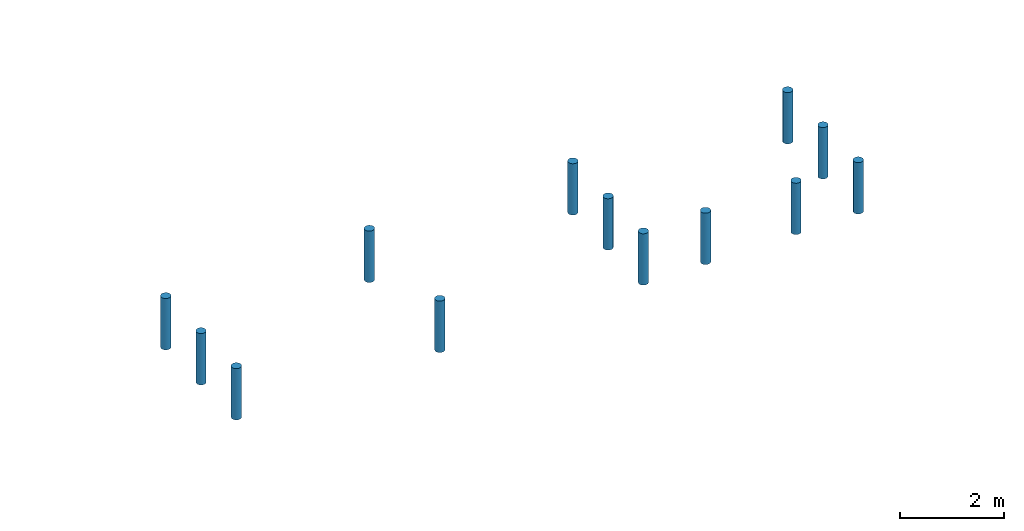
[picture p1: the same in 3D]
Properties of the parts of a building model (IFC2X3), part 3 of 5

# IfcFlowTerminal: Model Element 1 (7)
Allgemein - Abdichtvarianten: mit Klemmflansch; Abflussstutzen Ausführung: waagerecht; Ablaufanschluss: 1; Art der Nenn-/Betriebsspannung: nicht zutreffend; BIM: https://media.stage.bim.site/t/eyJhbGciOiJIUzI1NiIsInR5cCI6IkpXVCJ9.eyJjdCI6MSwidGYiOiJwdWJsaWMvbG9yb3dlcmsta2gtdmFobGJyYXVrLWdtYmgtY28ta2cvZDMwZTRjMS9QQVJUMzhfTG9yb18yMDE5MDcwMV8xLlZESSIsImNpZCI6IjMyNzdjYzIzLTgxYTktNGVlMy1hOTBhLWI0N2JiNGMwYjYxNiIsInJpZCI6IjdkOWE3MDg4NDgxYTBhMzQzMWY0N2FlZTliODFlOTc5IiwicGlkIjoiZTMxM2E5NGFhMTA2ZDA4MmExMTY3YzRlYTMwOTYyMjU2M2I5ZmY5YyIsInNpZCI6IjY2MzI1IiwidXQiOjUsImlhdCI6MTU2NTA5MjQwMSwiaXNzIjoiaHR0cHM6Ly9hcGkubGl2ZS5iaW0uc2l0ZSIsInN1YiI6ImFkbWluQGJpbXNpdGUuZGV2In0.Jl98j6UJM8vCRfjiMgs0gIMvvY09N5LGU-t2YxvX5b0/PART38_Loro_20190701_1.VDI; elektrischer Anschluss: nein; Feuerwiderstandsklasse: keine Feuerwiderstandsklasse; Feuerwiderstandsklasse nachrüstbar: nein; Gehäuseanschlussarten: Ablauf punktförmig; Geruchsverschluss: ohne Geruchsverschluss; Heizung: ohne Heizung; Ist System: no; Ist Zubehör: no; Kommentar: Serie 88, Attika-Distant, ohne Aufkantung; Nenndruck: 422; Nenndrucksystem: 270; Nennweitensystem: PN; Potenzialausgleich (Erdungsanschluss) vorhanden: ja; Produktbezeichnung: LORO-RAINSTAR 88 Attikaablauf, ohne Aufkant., Edelst., Klemmfl., Freispiegel, DN100; Produktklassifikation: Attikaablauf; Produktname: LORO-RAINSTAR 88 Attikaablauf, ohne Aufkant., Edelst., Klemmfl., Freispiegel, DN100; Produktvideo: https://media.stage.bim.site/t/eyJhbGciOiJIUzI1NiIsInR5cCI6IkpXVCJ9.eyJjdCI6MiwidHUiOiJodHRwOi8vd3d3Lmxvcm8uZGUvaW5kZXgucGhwP2lkPTIzM1x1MDAyNmFydGlrZWxucj0wMTM5MC4xMDBYIiwiY2lkIjoiMzI3N2NjMjMtODFhOS00ZWUzLWE5MGEtYjQ3YmI0YzBiNjE2IiwicmlkIjoiN2Q5YTcwODg0ODFhMGEzNDMxZjQ3YWVlOWI4MWU5NzkiLCJwaWQiOiJlMzEzYTk0YWExMDZkMDgyYTExNjdjNGVhMzA5NjIyNTYzYjlmZjljIiwic2lkIjoiNjYzMjUiLCJ1dCI6MiwiaWF0IjoxNTY1MDkyNDAxLCJpc3MiOiJodHRwczovL2FwaS5saXZlLmJpbS5zaXRlIiwic3ViIjoiYWRtaW5AYmltc2l0ZS5kZXYifQ._1ocKl-vpR0muEJ6-8qR1rfxTU_H0VxG05urxzZZrKM; Wärmedämmung: ohne Wärmedämmung; Werkstoff des Ablaufkörpers: nicht rostender Stahl
Daten - 38.710.01.13: seitlich; 38.710.01.5: DN; Bestellmenge (Multiplikator): 1; Einbaubreite [m]: 0.24; Einbautiefe [m]: 0; Sperrwasserhöhe [m]: 0
AR_Valgusti - 002_Tähis: LOROWERK 01390-100X:LOROWERK 01390-100X:259572; 900_Tootja: Undefined; 905_Mudel: Undefined; 910_Tooteinfo: Undefined; 915_Kasutus-ja_hooldusjuhend: Undefined; 400_Võimsus: 0,00; 405_Paigaldusviis: Undefined; 410_IP_Klass: Undefined
AR_Santehnika - 002_Tähis: LOROWERK 01390-100X:LOROWERK 01390-100X:259572; 455_Eriomadused: Undefined; 900_Tootja: Undefined; 905_Mudel: Undefined; 910_Tooteinfo: Undefined; 915_Kasutus-ja_hooldusjuhend: Undefined
AC_Pset_RenovationAndPhasing - Renovation Status: New
Name (LOROWERK 01390-100X:LOROWERK 01390-100X:...) | In
4 x 259572 | Teine korrus
3 x 259572 | Katusekorrus

# IfcFlowTerminal: RAL7016 120 (31)
Type - AR_Valgusti - 400_Võimsus: 60,00; 405_Paigaldusviis: Seina; 410_IP_Klass: 54; 900_Tootja: Ideal; 905_Mudel: GUN AP2 Big Antracite
Classification: 1.12 IfcLightFixtureType (valgusti) (RKAS BIM + ARCHICAD Classification); Material: RAL7016
AR_Valgusti - 002_Tähis: Välisvalgusti; 910_Tooteinfo: Undefined; 915_Kasutus-ja_hooldusjuhend: Undefined
AR_Santehnika - 002_Tähis: Välisvalgusti; 900_Tootja: Ideal; 905_Mudel: GUN AP2 Big Antracite; 910_Tooteinfo: Undefined; 915_Kasutus-ja_hooldusjuhend: Undefined
Pset_DistributionFlowElementCommon - Reference: Välisvalgusti
AC_Pset_RenovationAndPhasing - Renovation Status: New
Name | In
17 x Välisvalgusti | Esimene korrus
14 x Välisvalgusti | Teine korrus

# IfcFlowTerminal: RAL7016 180 (43)
Type - AR_Valgusti - 400_Võimsus: 60,00; 405_Paigaldusviis: Seina; 410_IP_Klass: 54; 900_Tootja: Ideal; 905_Mudel: GUN AP2 Big Antracite
Classification: 1.12 IfcLightFixtureType (valgusti) (RKAS BIM + ARCHICAD Classification); Material: RAL7016
AR_Valgusti - 002_Tähis: Välisvalgusti; 910_Tooteinfo: Undefined; 915_Kasutus-ja_hooldusjuhend: Undefined
AR_Santehnika - 002_Tähis: Välisvalgusti; 900_Tootja: Ideal; 905_Mudel: GUN AP2 Big Antracite; 910_Tooteinfo: Undefined; 915_Kasutus-ja_hooldusjuhend: Undefined
Pset_DistributionFlowElementCommon - Reference: Välisvalgusti
AC_Pset_RenovationAndPhasing - Renovation Status: New
Name | In
29 x Välisvalgusti | Esimene korrus
14 x Välisvalgusti | Teine korrus

# IfcFurnishingElement: KON-00_GENEERILINE - KONSTRUKTSIOON 5 (216)
In: Esimene korrus
Classification: 1.11 IfcFurnitureType (mööbel) (RKAS BIM + ARCHICAD Classification); Material: KON-00_GENEERILINE - KONSTRUKTSIOON
AR_Mööbel - 900_Tootja: Undefined; 905_Mudel: Undefined
AC_Pset_RenovationAndPhasing - Renovation Status: New
Name | 002_Tähis = Reference
2 x SS-04 | SS-04
2 x SS-02 | SS-02
2 x SS-43 | SS-43
2 x SS-38 | SS-38
2 x SS-39 | SS-39
2 x SS-37 | SS-37
2 x SS-07 | SS-07
2 x SS-09 | SS-09
2 x SS-98 | SS-98
2 x SS-08 | SS-08
2 x SS-91 | SS-91
2 x SS-92 | SS-92
2 x SS-93 | SS-93
2 x SS-94 | SS-94
2 x SS-95 | SS-95
2 x SS-96 | SS-96
2 x SS-97 | SS-97
2 x SS-05 | SS-05
2 x SS-12 | SS-12
2 x SS-22 | SS-22
2 x SS-03 | SS-03
2 x SS-90 | SS-90
2 x SS-30 | SS-30
2 x SS-01 | SS-01
2 x SS-10 | SS-10
2 x SS-28 | SS-28
2 x SS-85 | SS-85
2 x SS-86 | SS-86
2 x SS-25 | SS-25
4 x SS-68 | SS-68
2 x SS-06 | SS-06
2 x SS-62 | SS-62
4 x SS-64 | SS-64
2 x SS-63 | SS-63
4 x SS-65 | SS-65
4 x SS-66 | SS-66
2 x SS-00 | SS-00
4 x SS-69 | SS-69
2 x SS-99 | SS-99
2 x SS-58 | SS-58
2 x SS-57 | SS-57
2 x SS-56 | SS-56
2 x SS-55 | SS-55
2 x SS-54 | SS-54
2 x SS-53 | SS-53
2 x SS-52 | SS-52
2 x SS-51 | SS-51
2 x SS-50 | SS-50
2 x SS-49 | SS-49
2 x SS-48 | SS-48
2 x SS-47 | SS-47
2 x SS-46 | SS-46
2 x SS-45 | SS-45
2 x SS-44 | SS-44
2 x SS-59 | SS-59
2 x SS-60 | SS-60
2 x SS-42 | SS-42
2 x SS-41 | SS-41
2 x SS-84 | SS-84
2 x SS-83 | SS-83
2 x SS-40 | SS-40
2 x SS-82 | SS-82
2 x SS-81 | SS-81
2 x SS-36 | SS-36
2 x SS-35 | SS-35
2 x SS-79 | SS-79
2 x SS-80 | SS-80
2 x SS-34 | SS-34
2 x SS-33 | SS-33
2 x SS-32 | SS-32
2 x SS-77 | SS-77
2 x SS-78 | SS-78
2 x SS-31 | SS-31
2 x SS-29 | SS-29
2 x SS-76 | SS-76
2 x SS-75 | SS-75
2 x SS-27 | SS-27
2 x SS-26 | SS-26
2 x SS-74 | SS-74
2 x SS-73 | SS-73
2 x SS-61 | SS-61
2 x SS-24 | SS-24
2 x SS-23 | SS-23
4 x SS-71 | SS-71
2 x SS-72 | SS-72
2 x SS-21 | SS-21
2 x SS-20 | SS-20
2 x SS-19 | SS-19
4 x SS-70 | SS-70
2 x SS-18 | SS-18
2 x SS-17 | SS-17
2 x SS-16 | SS-16
4 x SS-67 | SS-67
2 x SS-15 | SS-15
2 x SS-14 | SS-14
2 x SS-13 | SS-13
2 x SS-11 | SS-11
2 x SS-87 | SS-87
2 x SS-89 | SS-89
2 x SS-88 | SS-88

# IfcFurnishingElement: Sofa 23, MÖÖBEL
In: Esimene korrus
Classification: 1.11 IfcFurnitureType (mööbel) (RKAS BIM + ARCHICAD Classification)
AR_Mööbel - 002_Tähis: MÖÖBEL; 900_Tootja: Undefined; 905_Mudel: Undefined
Pset_QuantityTakeOff - Reference: MÖÖBEL
AC_Pset_RenovationAndPhasing - Renovation Status: Existing

# IfcMember: Boundary Frame 50 x 200 (18)
In: Esimene korrus
Type - PredefinedType: MULLION
Classification: Curtain Wall Frame (RKAS BIM + ARCHICAD Classification); Material: ET-04_Alumiinium
AC_Pset_RenovationAndPhasing - Renovation Status: New
Name | Reference | Slope (deg)
RF RAAM SERV-521 | RF RAAM SERV-521 | 90
RF RAAM SERV-522 | RF RAAM SERV-522 | 90
2 x RF RAAM SERV-512 | RF RAAM SERV-512 | 7.88273e-07
RF RAAM SERV-510 | RF RAAM SERV-510 | 5.04853e-07
RF RAAM SERV-513 | RF RAAM SERV-513 | 0
RF RAAM SERV-517 | RF RAAM SERV-517 | 0.00000106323
RF RAAM SERV-516 | RF RAAM SERV-516 | 90
RF RAAM SERV-520 | RF RAAM SERV-520 | 0
2 x RF RAAM SERV-519 | RF RAAM SERV-519 | 0
RF RAAM SERV-515 | RF RAAM SERV-515 | 90
2 x RF RAAM SERV-518 | RF RAAM SERV-518 | 0
2 x RF RAAM SERV-511 | RF RAAM SERV-511 | 0
RF RAAM SERV-509 | RF RAAM SERV-509 | 90
RF RAAM SERV-514 | RF RAAM SERV-514 | 90

# IfcMember: ET-05_Teras 100 x 200 (9)
Type - ElementType: Stair Structure; PredefinedType: USERDEFINED
Classification: Stair Structure (RKAS BIM + ARCHICAD Classification); Material: ET-05_Teras
Pset_MemberCommon - Reference: Tala; Slope: 0 deg; LoadBearing: yes; IsExternal: yes
AC_Pset_RenovationAndPhasing - Renovation Status: New
Name | In
4 x Tala | Teine korrus
5 x Tala | Katusekorrus

# IfcMember: IfcMember (64)
Type - ElementType: Rail; PredefinedType: USERDEFINED
Classification: Rail (RKAS BIM + ARCHICAD Classification)
Name | In | Material | Reference | Renovation Status
4 x Piirde ülemise osa ots - 001 | Vundament | ET-07_Teras - Roostevaba | Piirde ülemise osa ots - 001 | Existing
12 x Piirde alaosa - 001 | Vundament | ET-07_Teras - Roostevaba | Piirde alaosa - 001 | Existing
8 x Piirde alaosa - 001 | Esimene korrus | ET-07_Teras - Roostevaba | Piirde alaosa - 001 | Existing
9 x  | Esimene korrus | ET-07_Teras - Roostevaba |  | New
4 x  | Esimene korrus | RAL7016 |  | New
2 x RAIL CONNECTION - 001 | Esimene korrus | ET-07_Teras - Roostevaba | RAIL CONNECTION - 001 | Existing
4 x Piirde ülemise osa ühendus - 001 | Esimene korrus | ET-07_Teras - Roostevaba | Piirde ülemise osa ühendus - 001 | Existing
Piirde alaosa - 001 | Teine korrus | RAL7016 | Piirde alaosa - 001 | New
4 x Piirde ülemise osa ots - 001 | Teine korrus | ET-07_Teras - Roostevaba | Piirde ülemise osa ots - 001 | Existing
8 x Piirde alaosa - 001 | Teine korrus | ET-07_Teras - Roostevaba | Piirde alaosa - 001 | Existing
4 x  | Teine korrus | ET-07_Teras - Roostevaba |  | New
4 x  | Teine korrus | RAL7016 |  | New

# IfcMember: IfcMember (10)
Type - ElementType: Stair Structure; PredefinedType: USERDEFINED
Classification: Stair Structure (RKAS BIM + ARCHICAD Classification)
Name | In | Material | Reference | Renovation Status
2 x Trepp | Esimene korrus | KON-00_GENEERILINE - KONSTRUKTSIOON | Trepp | Existing
Tala | Esimene korrus | ET-06_Teras - Konstruktsioon | Tala | New
Tala | Teine korrus | ET-06_Teras - Konstruktsioon | Tala | New
SF LEFT STRINGER - 007 | Teine korrus | ET-06_Teras - Konstruktsioon | SF LEFT STRINGER - 007 | Existing
SF RIGHT STRINGER - 007 | Teine korrus | ET-06_Teras - Konstruktsioon | SF RIGHT STRINGER - 007 | Existing
2 x SF LEFT STRINGER - 008 | Teine korrus | ET-06_Teras - Konstruktsioon | SF LEFT STRINGER - 008 | Existing
2 x SF RIGHT STRINGER - 008 | Teine korrus | ET-06_Teras - Konstruktsioon | SF RIGHT STRINGER - 008 | Existing

# IfcMember: IfcMember (54)
In: Teine korrus
Type - ElementType: Stair Tread; PredefinedType: USERDEFINED
Classification: Stair Tread (RKAS BIM + ARCHICAD Classification); Material: SV-02_Puit - Põrand
AC_Pset_RenovationAndPhasing - Renovation Status: Existing
Name | Reference
TV ASTE - 073 | TV ASTE - 073
TV ASTE - 074 | TV ASTE - 074
TV ASTE - 075 | TV ASTE - 075
TV ASTE - 076 | TV ASTE - 076
TV ASTE - 077 | TV ASTE - 077
TV ASTE - 078 | TV ASTE - 078
TV ASTE - 079 | TV ASTE - 079
TV ASTE - 080 | TV ASTE - 080
TV ASTE - 081 | TV ASTE - 081
TV ASTE - 082 | TV ASTE - 082
TV ASTE - 083 | TV ASTE - 083
TV ASTE - 084 | TV ASTE - 084
TV ASTE - 085 | TV ASTE - 085
TV ASTE - 086 | TV ASTE - 086
TV ASTE - 087 | TV ASTE - 087
TV ASTE - 088 | TV ASTE - 088
TV ASTE - 091 | TV ASTE - 091
TV ASTE - 092 | TV ASTE - 092
TV ASTE - 093 | TV ASTE - 093
2 x TV ASTE - 094 | TV ASTE - 094
2 x TV ASTE - 095 | TV ASTE - 095
2 x TV ASTE - 096 | TV ASTE - 096
2 x TV ASTE - 097 | TV ASTE - 097
2 x TV ASTE - 098 | TV ASTE - 098
2 x TV ASTE - 099 | TV ASTE - 099
2 x TV ASTE - 100 | TV ASTE - 100
2 x TV ASTE - 101 | TV ASTE - 101
2 x TV ASTE - 102 | TV ASTE - 102
2 x TV ASTE - 103 | TV ASTE - 103
2 x TV ASTE - 104 | TV ASTE - 104
2 x TV ASTE - 105 | TV ASTE - 105
2 x TV ASTE - 106 | TV ASTE - 106
2 x TV ASTE - 107 | TV ASTE - 107
2 x TV ASTE - 113 | TV ASTE - 113
TV ASTE - 114 | TV ASTE - 114
TV ASTE - 108 | TV ASTE - 108
TV ASTE - 109 | TV ASTE - 109
TV ASTE - 110 | TV ASTE - 110
TV ASTE - 111 | TV ASTE - 111

# IfcMember: IfcMember (415)
Type - PredefinedType: POST
Classification: Railing Post (RKAS BIM + ARCHICAD Classification)
Name | In | Material | Reference | Renovation Status
6 x PIIRDE POST - 001 | Vundament | ET-06_Teras - Konstruktsioon | PIIRDE POST - 001 | Existing
8 x Piirde Post - 001 | Vundament | ET-07_Teras - Roostevaba | Piirde Post - 001 | Existing
15 x Piirde Post - 001 | Esimene korrus | ET-07_Teras - Roostevaba | Piirde Post - 001 | Existing
5 x  | Esimene korrus | RAL7016 |  | New
126 x Balustraad - 001 | Esimene korrus | RAL7016 | Balustraad - 001 | New
9 x Piirde Post - 001 | Esimene korrus | RAL7016 | Piirde Post - 001 | New
16 x Balustraad - 001 | Esimene korrus | RAL7016 | Balustraad - 001 | Existing
28 x PIIRDE POST - 001 | Esimene korrus | ET-06_Teras - Konstruktsioon | PIIRDE POST - 001 | Existing
11 x  | Teine korrus | RAL7016 |  | New
171 x Balustraad - 001 | Teine korrus | RAL7016 | Balustraad - 001 | New
11 x Piirde Post - 001 | Teine korrus | RAL7016 | Piirde Post - 001 | New
4 x PIIRDE POST - 001 | Teine korrus | ET-06_Teras - Konstruktsioon | PIIRDE POST - 001 | Existing
5 x Piirde Post - 001 | Teine korrus | ET-07_Teras - Roostevaba | Piirde Post - 001 | Existing

# IfcMember: Mullion Frame 50 x 200 (6)
In: Esimene korrus
Type - PredefinedType: MULLION
Classification: Curtain Wall Frame (RKAS BIM + ARCHICAD Classification); Material: ET-04_Alumiinium
Pset_MemberCommon - Slope: 90 deg
Name | Reference | Renovation Status
2 x RF RAAM VERT-344 | RF RAAM VERT-344 | New
RF RAAM VERT-353 | RF RAAM VERT-353 | Existing
RF RAAM VERT-343 | RF RAAM VERT-343 | New
2 x RF RAAM VERT-341 | RF RAAM VERT-341 | New

# IfcOpeningElement: OPENING (50)
Classification: 1.14 IfcOpeningElement (avaelement) (RKAS BIM + ARCHICAD Classification)
Name | In | Reference | Renovation Status
32 x AVA | Esimene korrus | AVA | Existing
5 x VS-03 | Esimene korrus | VS-03 | Existing
2 x AVA | Esimene korrus | AVA | To Be Demolished
8 x AVA | Teine korrus | AVA | Existing
3 x AVA | Teine korrus | AVA | New

# IfcPlate: 800 x 5 x 20, RF PANEEL PEAMINE-029
In: Esimene korrus
Type - PredefinedType: CURTAIN_PANEL
Classification: Curtain Wall Panel (RKAS BIM + ARCHICAD Classification)
Pset_PlateCommon - Reference: RF PANEEL PEAMINE-029
Pset_ManufacturerOccurrence - SerialNumber: Off
AC_Pset_RenovationAndPhasing - Renovation Status: New

# IfcPlate: AP-02 pealiskihid 222, Põranda soojustus
In: Esimene korrus
Classification: 1.15 IfcPlateType (plaat) (RKAS BIM + ARCHICAD Classification)
Pset_PlateCommon - Reference: Põranda soojustus; LoadBearing: no; IsExternal: yes
AC_Pset_RenovationAndPhasing - Renovation Status: New

# IfcPlate: ET-02_Raudbetoon - Toode 300, AP-02
In: Esimene korrus
Classification: 1.15 IfcPlateType (plaat) (RKAS BIM + ARCHICAD Classification); Material: ET-02_Raudbetoon - Toode
Pset_PlateCommon - Reference: AP-02; LoadBearing: no; IsExternal: yes
AR - 001_Nimetus: Aluspõrand
AC_Pset_RenovationAndPhasing - Renovation Status: Existing

# IfcPlate: KON-00_GENEERILINE - KONSTRUKTSIOON 200, PLAAT
In: Esimene korrus
Classification: 1.15 IfcPlateType (plaat) (RKAS BIM + ARCHICAD Classification); Material: KON-00_GENEERILINE - KONSTRUKTSIOON
Pset_PlateCommon - Reference: PLAAT
AC_Pset_RenovationAndPhasing - Renovation Status: Existing

# IfcPlate: KON-00_GENEERILINE - KONSTRUKTSIOON 220, PLAAT
In: Esimene korrus
Classification: 1.15 IfcPlateType (plaat) (RKAS BIM + ARCHICAD Classification); Material: KON-00_GENEERILINE - KONSTRUKTSIOON
Pset_PlateCommon - Reference: PLAAT
AC_Pset_RenovationAndPhasing - Renovation Status: Existing

# IfcPlate: KON-00_GENEERILINE - KONSTRUKTSIOON 360 (2)
In: Esimene korrus
Classification: 1.15 IfcPlateType (plaat) (RKAS BIM + ARCHICAD Classification); Material: KON-00_GENEERILINE - KONSTRUKTSIOON
Pset_PlateCommon - Reference: PLAAT
AC_Pset_RenovationAndPhasing - Renovation Status: Existing

# IfcPlate: Karniis 25, AP-03
In: Esimene korrus
Classification: 1.15 IfcPlateType (plaat) (RKAS BIM + ARCHICAD Classification)
Pset_PlateCommon - Reference: AP-03; LoadBearing: no; IsExternal: yes
AR - 001_Nimetus: Aluspõrand
AC_Pset_RenovationAndPhasing - Renovation Status: Existing

# IfcPlate: Main Panel 720 x 5 x 20, RF PANEEL PEAMINE-030
In: Esimene korrus
Type - PredefinedType: CURTAIN_PANEL
Classification: Curtain Wall Panel (RKAS BIM + ARCHICAD Classification); Material: VKR-05_Klaas
Pset_PlateCommon - Reference: RF PANEEL PEAMINE-030
AC_Pset_RenovationAndPhasing - Renovation Status: New

# IfcPlate: Main Panel 875 x 5 x 20, RF PANEEL PEAMINE-028
In: Esimene korrus
Type - PredefinedType: CURTAIN_PANEL
Classification: Curtain Wall Panel (RKAS BIM + ARCHICAD Classification); Material: VKR-05_Klaas
Pset_PlateCommon - Reference: RF PANEEL PEAMINE-028
AC_Pset_RenovationAndPhasing - Renovation Status: New

# IfcRailing: ET-05_Teras 10 (4)
In: Esimene korrus
Classification: 1.16 IfcRailingType (piire) (RKAS BIM + ARCHICAD Classification); Material: ET-05_Teras
Pset_RailingCommon - Reference: Trepipiire; IsExternal: yes
AR_Piire - 205_Tähis: Trepipiire
AC_Pset_RenovationAndPhasing - Renovation Status: New

# IfcRailing: ET-07_Teras - Roostevaba D10 (86)
In: Esimene korrus
Classification: 1.16 IfcRailingType (piire) (RKAS BIM + ARCHICAD Classification); Material: ET-07_Teras - Roostevaba
Pset_RailingCommon - IsExternal: yes
AC_Pset_RenovationAndPhasing - Renovation Status: New
Name | Reference = 205_Tähis
30 x Trepiire | Trepiire
56 x Trepipiire | Trepipiire

# IfcRailing: IfcRailing (34)
Type - PredefinedType: GUARDRAIL
Classification: Guardrail (RKAS BIM + ARCHICAD Classification)
AR_Piire - 900_Tootja: Undefined; 905_Mudel: Undefined; 910_Tooteinfo: Undefined; 915_Kasutus-ja_hooldusjuhend: Undefined
Name | In | Material | Reference = 205_Tähis | Renovation Status
2 x Piirde Ülaosa - 001 | Vundament | ET-07_Teras - Roostevaba | Piirde Ülaosa - 001 | Existing
6 x  | Esimene korrus | RAL7016 |  | New
16 x Piirde Ülaosa - 001 | Esimene korrus | ET-07_Teras - Roostevaba | Piirde Ülaosa - 001 | Existing
8 x  | Teine korrus | RAL7016 |  | New
2 x Piirde Ülaosa - 001 | Teine korrus | ET-07_Teras - Roostevaba | Piirde Ülaosa - 001 | Existing

# IfcRailing: IfcRailing (20)
Type - PredefinedType: HANDRAIL
Classification: Handrail (RKAS BIM + ARCHICAD Classification); Material: ET-07_Teras - Roostevaba
Pset_RailingCommon - Reference: Piirde Käsipuu - 001
AR_Piire - 205_Tähis: Piirde Käsipuu - 001; 900_Tootja: Undefined; 905_Mudel: Undefined; 910_Tooteinfo: Undefined; 915_Kasutus-ja_hooldusjuhend: Undefined
AC_Pset_RenovationAndPhasing - Renovation Status: New
Name | In
12 x Piirde Käsipuu - 001 | Esimene korrus
8 x Piirde Käsipuu - 001 | Teine korrus

# IfcRailing: RAL 7011 Tumehall 50 (2)
In: Esimene korrus
Classification: 1.16 IfcRailingType (piire) (RKAS BIM + ARCHICAD Classification); Material: RAL 7011 Tumehall
Pset_RailingCommon - Reference: Trepiire; IsExternal: yes
AR_Piire - 205_Tähis: Trepiire
AC_Pset_RenovationAndPhasing - Renovation Status: New

# IfcRailing: RAL 9007 50 (2)
In: Esimene korrus
Classification: 1.16 IfcRailingType (piire) (RKAS BIM + ARCHICAD Classification); Material: RAL 9007
Pset_RailingCommon - Reference: Trepiire; IsExternal: yes
AR_Piire - 205_Tähis: Trepiire
AC_Pset_RenovationAndPhasing - Renovation Status: New

# IfcRailing: RAL7016 10 (5)
In: Esimene korrus
Classification: 1.16 IfcRailingType (piire) (RKAS BIM + ARCHICAD Classification); Material: RAL7016
Pset_RailingCommon - IsExternal: yes
AC_Pset_RenovationAndPhasing - Renovation Status: New
Name | Reference = 205_Tähis
4 x Trepiire | Trepiire
Trepipiire | Trepipiire

# IfcRailing: RAL7016 1000 (2)
In: Esimene korrus
Classification: 1.16 IfcRailingType (piire) (RKAS BIM + ARCHICAD Classification); Material: RAL7016
Pset_RailingCommon - Reference: Trepipiire; IsExternal: yes
AR_Piire - 205_Tähis: Trepipiire
AC_Pset_RenovationAndPhasing - Renovation Status: New

# IfcRailing: RAL7016 38 (7)
Classification: 1.16 IfcRailingType (piire) (RKAS BIM + ARCHICAD Classification); Material: RAL7016
Pset_RailingCommon - Reference: Trepi piire; IsExternal: yes
AR_Piire - 205_Tähis: Trepi piire
AC_Pset_RenovationAndPhasing - Renovation Status: New
Name | In
5 x Trepi piire | Teine korrus
2 x Trepi piire | Katusekorrus

# IfcRailing: RAL7016 41 (2)
In: Esimene korrus
Classification: 1.16 IfcRailingType (piire) (RKAS BIM + ARCHICAD Classification); Material: RAL7016
Pset_RailingCommon - Reference: Trepi piire; IsExternal: yes
AR_Piire - 205_Tähis: Trepi piire
AC_Pset_RenovationAndPhasing - Renovation Status: New

# IfcRailing: RAL7016 50 (82)
In: Esimene korrus
Classification: 1.16 IfcRailingType (piire) (RKAS BIM + ARCHICAD Classification); Material: RAL7016
Pset_RailingCommon - IsExternal: yes
AC_Pset_RenovationAndPhasing - Renovation Status: New
Name | Reference = 205_Tähis
56 x Piire | Piire
26 x Trepiire | Trepiire

# IfcRailing: Railing Type (29)
Classification: 1.16 IfcRailingType (piire) (RKAS BIM + ARCHICAD Classification)
Name | In | Reference = 205_Tähis | IsExternal | Renovation Status
2 x PIIRE | Vundament | PIIRE | no | Existing
PIIRE | Vundament | PIIRE |  | Existing
PIIRE | Esimene korrus | PIIRE | no | Existing
7 x Trepipiire | Esimene korrus | Trepipiire | yes | New
12 x PIIRE | Esimene korrus | PIIRE | yes | Existing
3 x Trepipiire | Teine korrus | Trepipiire | yes | New
PIIRE | Teine korrus | PIIRE |  | Existing
PIIRE | Teine korrus | PIIRE | no | Existing
PIIRE | Teine korrus | PIIRE |  | New

# IfcRamp (6)
In: Esimene korrus
Classification: 1.17 IfcRamp (ramp) (RKAS BIM + ARCHICAD Classification); Material: KON-06_Raudbetoon - Konstruktsioon
AR_Ramp - 335_Välispiire: yes
AC_Pset_RenovationAndPhasing - Renovation Status: New
Pset_RampCommon - IsExternal: yes
Name | 550_Kalle_RAD (deg)
4 x Pandus | 11.4592
2 x Pandus | 5.72958

# IfcSlab: AP-01 350 (12)
In: Esimene korrus
Classification: 1.20 IfcSlabType (vahelagi) (RKAS BIM + ARCHICAD Classification)
AR_Plaat - 001_Nimetus: Aluspõrand; 002_Tähis: AP-01; 325_Helipidavus: nõudeid ei esitata; 330_Tulekindlus: nõudeid ei esitata; 505_Paksus: 350 mm; 500_Kandev: no
AC_Pset_RenovationAndPhasing - Renovation Status: New
Pset_SlabCommon - LoadBearing: no; IsExternal: yes
Name | 515_Neto_pindala (m2)
AP-01 | 66.3262
AP-01 | 43.973
AP-01 | 32.1546
AP-01 | 7.96028
AP-01 | 19.1016
AP-01 | 68.6605
AP-01 | 54.6261
AP-01 | 68.3944
AP-01 | 185.919
AP-01 | 186.039
AP-01 | 18.5351
AP-01 | 14.5817

# IfcSlab: AP-02 551, AP-02
In: Esimene korrus
Classification: 1.20 IfcSlabType (vahelagi) (RKAS BIM + ARCHICAD Classification)
AR_Plaat - 001_Nimetus: Aluspõrand; 002_Tähis: AP-02; 325_Helipidavus: nõudeid ei esitata; 330_Tulekindlus: nõudeid ei esitata; 505_Paksus: 551 mm; 515_Neto_pindala: 1.53 m2; 500_Kandev: no
AC_Pset_RenovationAndPhasing - Renovation Status: New
Pset_SlabCommon - LoadBearing: no; IsExternal: yes

# IfcSlab: AP-04_prugimaja_betoonkivi 490, Alusporand
In: Esimene korrus
Classification: 1.20 IfcSlabType (vahelagi) (RKAS BIM + ARCHICAD Classification)
AR_Plaat - 002_Tähis: Alusporand; 325_Helipidavus: Undefined; 330_Tulekindlus: Undefined; 505_Paksus: 490 mm; 515_Neto_pindala: 39.8857 m2; 500_Kandev: yes
AC_Pset_RenovationAndPhasing - Renovation Status: New
Pset_SlabCommon - LoadBearing: yes; IsExternal: yes

# IfcSlab: ET-00_GENEERILINE - EHITUSTOODE (2)
In: Katusekorrus
Type - PredefinedType: ROOF
Classification: 1.19 IfcSlabType.ROOF (katus) (RKAS BIM + ARCHICAD Classification); Material: ET-00_GENEERILINE - EHITUSTOODE
AR_Plaat - 002_Tähis: KATUS; 325_Helipidavus: Undefined; 330_Tulekindlus: Undefined
AC_Pset_RenovationAndPhasing - Renovation Status: Existing

# IfcSlab: ET-03_Raud 100 (2)
In: Teine korrus
Type - PredefinedType: ROOF
Classification: 1.19 IfcSlabType.ROOF (katus) (RKAS BIM + ARCHICAD Classification); Material: ET-03_Raud
AR_Plaat - 002_Tähis: Varikatus; 325_Helipidavus: Undefined; 330_Tulekindlus: Undefined
AC_Pset_RenovationAndPhasing - Renovation Status: New
Pset_SlabCommon - LoadBearing: no; IsExternal: yes

# IfcSlab: KL-01 _uus soojustus 481, KL-01
In: Katusekorrus
Type - PredefinedType: ROOF
Classification: 1.19 IfcSlabType.ROOF (katus) (RKAS BIM + ARCHICAD Classification)
AR_Plaat - 515_Neto_pindala: 0 m2; 340_Soojusläbivus: 0; 001_Nimetus: katuslagi; 002_Tähis: KL-01; 325_Helipidavus: nõudeid ei esitata; 330_Tulekindlus: R30
AC_Pset_RenovationAndPhasing - Renovation Status: New
Pset_SlabCommon - LoadBearing: yes; IsExternal: yes

# IfcSlab: KL-01 ja KL-01.1 kalde ja pealiskihid 472 (8)
In: Katusekorrus
Type - PredefinedType: ROOF
Classification: 1.19 IfcSlabType.ROOF (katus) (RKAS BIM + ARCHICAD Classification)
AR_Plaat - 515_Neto_pindala: 0 m2; 340_Soojusläbivus: 0; 001_Nimetus: katuslagi; 002_Tähis: KL-01 ja KL-01.1 kalde ja pealiskihid; 325_Helipidavus: nõudeid ei esitata; 330_Tulekindlus: R30
AC_Pset_RenovationAndPhasing - Renovation Status: New
Pset_SlabCommon - LoadBearing: no; IsExternal: yes

# IfcSlab: KL-01 ja KL-01.1 servasoojustus 300, KL-01 ja KL-01.1 servasoojustus
In: Katusekorrus
Type - PredefinedType: ROOF
Classification: 1.19 IfcSlabType.ROOF (katus) (RKAS BIM + ARCHICAD Classification)
AR_Plaat - 515_Neto_pindala: 0 m2; 340_Soojusläbivus: 0; 001_Nimetus: katuslagi; 002_Tähis: KL-01 ja KL-01.1 servasoojustus; 325_Helipidavus: nõudeid ei esitata; 330_Tulekindlus: R30
AC_Pset_RenovationAndPhasing - Renovation Status: New
Pset_SlabCommon - LoadBearing: no; IsExternal: yes

# IfcSlab: KL-01.1 701 (2)
In: Katusekorrus
Type - PredefinedType: ROOF
Classification: 1.19 IfcSlabType.ROOF (katus) (RKAS BIM + ARCHICAD Classification)
AR_Plaat - 515_Neto_pindala: 0 m2; 340_Soojusläbivus: 0; 001_Nimetus: katuslagi; 002_Tähis: KL-01.1; 325_Helipidavus: nõudeid ei esitata; 330_Tulekindlus: R30
AC_Pset_RenovationAndPhasing - Renovation Status: New
Pset_SlabCommon - LoadBearing: yes

# IfcSlab: KL-01_ololpaneel 220, KL-01
In: Katusekorrus
Type - PredefinedType: ROOF
Classification: 1.19 IfcSlabType.ROOF (katus) (RKAS BIM + ARCHICAD Classification); Material: Olemasolev r/b paneel 220 mm
AR_Plaat - 515_Neto_pindala: 0 m2; 340_Soojusläbivus: 0; 001_Nimetus: katuslagi; 002_Tähis: KL-01; 325_Helipidavus: nõudeid ei esitata; 330_Tulekindlus: R30
AC_Pset_RenovationAndPhasing - Renovation Status: Existing
Pset_SlabCommon - LoadBearing: yes; IsExternal: yes

# IfcSlab: KL-02 281, KL-02
In: Teine korrus
Type - PredefinedType: ROOF
Classification: 1.19 IfcSlabType.ROOF (katus) (RKAS BIM + ARCHICAD Classification)
AR_Plaat - 340_Soojusläbivus: 0; 515_Neto_pindala: 0 m2; 001_Nimetus: katuslagi; 002_Tähis: KL-02; 325_Helipidavus: nõudeid ei esitata; 330_Tulekindlus: R30
AC_Pset_RenovationAndPhasing - Renovation Status: New
Pset_SlabCommon - LoadBearing: no; IsExternal: yes

# IfcSlab: KL-02 kalde ja pealiskihid 382 (12)
In: Teine korrus
Type - PredefinedType: ROOF
Classification: 1.19 IfcSlabType.ROOF (katus) (RKAS BIM + ARCHICAD Classification)
AR_Plaat - 340_Soojusläbivus: 0; 515_Neto_pindala: 0 m2; 001_Nimetus: katuslagi; 002_Tähis: KL-02; 325_Helipidavus: nõudeid ei esitata; 330_Tulekindlus: R30
AC_Pset_RenovationAndPhasing - Renovation Status: New
Pset_SlabCommon - LoadBearing: no; IsExternal: yes

# IfcSlab: KL-02 servasoojustus 380, KL-02 servasoojustus
In: Teine korrus
Type - PredefinedType: ROOF
Classification: 1.19 IfcSlabType.ROOF (katus) (RKAS BIM + ARCHICAD Classification)
AR_Plaat - 340_Soojusläbivus: 0; 515_Neto_pindala: 0 m2; 001_Nimetus: katuslagi; 002_Tähis: KL-02 servasoojustus; 325_Helipidavus: nõudeid ei esitata; 330_Tulekindlus: R30
AC_Pset_RenovationAndPhasing - Renovation Status: New
Pset_SlabCommon - LoadBearing: no; IsExternal: yes

# IfcSlab: KL-03 100, KL-03
In: Esimene korrus
Type - PredefinedType: ROOF
Classification: 1.19 IfcSlabType.ROOF (katus) (RKAS BIM + ARCHICAD Classification); Material: SP2B E-PIR 100 mm
AR_Plaat - 340_Soojusläbivus: 0; 515_Neto_pindala: 0 m2; 002_Tähis: KL-03; 325_Helipidavus: Undefined; 330_Tulekindlus: Undefined
AC_Pset_RenovationAndPhasing - Renovation Status: New
Pset_SlabCommon - LoadBearing: no; IsExternal: yes

# IfcSlab: KL-04 sisekihid 207, KL-04
In: Esimene korrus
Type - PredefinedType: ROOF
Classification: 1.19 IfcSlabType.ROOF (katus) (RKAS BIM + ARCHICAD Classification)
AR_Plaat - 340_Soojusläbivus: 0; 515_Neto_pindala: 0 m2; 002_Tähis: KL-04; 325_Helipidavus: Undefined; 330_Tulekindlus: Undefined
AC_Pset_RenovationAndPhasing - Renovation Status: New

# IfcSlab: KON-00_GENEERILINE - KONSTRUKTSIOON 130, KATUS
In: Esimene korrus
Type - PredefinedType: ROOF
Classification: 1.19 IfcSlabType.ROOF (katus) (RKAS BIM + ARCHICAD Classification); Material: KON-00_GENEERILINE - KONSTRUKTSIOON 130.042 mm
AR_Plaat - 002_Tähis: KATUS; 325_Helipidavus: Undefined; 330_Tulekindlus: Undefined
AC_Pset_RenovationAndPhasing - Renovation Status: Existing
Pset_SlabCommon - LoadBearing: no; IsExternal: yes

# IfcSlab: KON-04_Betoon - Konstuktsioon 200, Äärekivi
In: Esimene korrus
Classification: 1.20 IfcSlabType (vahelagi) (RKAS BIM + ARCHICAD Classification); Material: KON-04_Betoon - Konstuktsioon 200 mm
AR_Plaat - 002_Tähis: Äärekivi; 325_Helipidavus: Undefined; 330_Tulekindlus: Undefined; 505_Paksus: 200 mm; 515_Neto_pindala: 1.58863 m2; 500_Kandev: no
AC_Pset_RenovationAndPhasing - Renovation Status: New
Pset_SlabCommon - LoadBearing: no; IsExternal: yes

# IfcSlab: KON-04_Betoon - Konstuktsioon 200 (2)
In: Esimene korrus
Type - PredefinedType: ROOF
Classification: 1.19 IfcSlabType.ROOF (katus) (RKAS BIM + ARCHICAD Classification); Material: KON-04_Betoon - Konstuktsioon 200 mm
AR_Plaat - 002_Tähis: KATUS; 325_Helipidavus: Undefined; 330_Tulekindlus: Undefined
AC_Pset_RenovationAndPhasing - Renovation Status: Existing
Pset_SlabCommon - LoadBearing: yes; IsExternal: yes

# IfcSlab: Katuse äravool 92 (6)
Type - PredefinedType: ROOF
Classification: 1.19 IfcSlabType.ROOF (katus) (RKAS BIM + ARCHICAD Classification)
AR_Plaat - 340_Soojusläbivus: 0; 515_Neto_pindala: 0 m2; 001_Nimetus: katuslagi; 325_Helipidavus: nõudeid ei esitata; 330_Tulekindlus: R30
AC_Pset_RenovationAndPhasing - Renovation Status: New
Pset_SlabCommon - LoadBearing: no; IsExternal: yes
Name | In | 002_Tähis
4 x KL-02 | Teine korrus | KL-02
2 x KL-01 | Katusekorrus | KL-01

# IfcSlab: LADU LAGI 1_puhas paneel 12132 x 300, KL-02
In: Esimene korrus
Type - PredefinedType: ROOF
Classification: 1.19 IfcSlabType.ROOF (katus) (RKAS BIM + ARCHICAD Classification); Material: SV-03_Plaat - Põrand
AR_Sein - 500_Kandev: yes
AR_Plaat - 340_Soojusläbivus: 0; 515_Neto_pindala: 0 m2; 001_Nimetus: katuslagi; 002_Tähis: KL-02; 325_Helipidavus: nõudeid ei esitata; 330_Tulekindlus: R30
AC_Pset_RenovationAndPhasing - Renovation Status: Existing
Pset_SlabCommon - LoadBearing: yes; IsExternal: no

# IfcSlab: LADU LAGI 2_Puhas paneel 12000 x 300, KL-02
In: Teine korrus
Type - PredefinedType: ROOF
Classification: 1.19 IfcSlabType.ROOF (katus) (RKAS BIM + ARCHICAD Classification); Material: SV-03_Plaat - Põrand
AR_Sein - 500_Kandev: yes
AR_Plaat - 340_Soojusläbivus: 0; 515_Neto_pindala: 0 m2; 001_Nimetus: katuslagi; 002_Tähis: KL-02; 325_Helipidavus: nõudeid ei esitata; 330_Tulekindlus: R30
AC_Pset_RenovationAndPhasing - Renovation Status: Existing
Pset_SlabCommon - LoadBearing: yes; IsExternal: yes

# IfcSlab: LADU LAGI 3_Puhas paneel 11829 x 300 (2)
In: Teine korrus
Type - PredefinedType: ROOF
Classification: 1.19 IfcSlabType.ROOF (katus) (RKAS BIM + ARCHICAD Classification); Material: SV-03_Plaat - Põrand
AR_Sein - 500_Kandev: yes
AR_Plaat - 340_Soojusläbivus: 0; 515_Neto_pindala: 0 m2; 001_Nimetus: katuslagi; 002_Tähis: KL-02; 325_Helipidavus: nõudeid ei esitata; 330_Tulekindlus: R30
AC_Pset_RenovationAndPhasing - Renovation Status: Existing
Pset_SlabCommon - LoadBearing: yes; IsExternal: yes

# IfcSlab: Olemasolev raudbetoontala 260, Tala
In: Teine korrus
Classification: 1.20 IfcSlabType (vahelagi) (RKAS BIM + ARCHICAD Classification); Material: Olemasolev raudbetoontala 260 mm
AR_Plaat - 002_Tähis: Tala; 325_Helipidavus: Undefined; 330_Tulekindlus: Undefined; 505_Paksus: 260 mm; 515_Neto_pindala: 1.19268 m2; 500_Kandev: yes
AC_Pset_RenovationAndPhasing - Renovation Status: Existing
Pset_SlabCommon - LoadBearing: yes; IsExternal: no

# IfcSlab: RAL7016 100 (4)
In: Teine korrus
Type - PredefinedType: ROOF
Classification: 1.19 IfcSlabType.ROOF (katus) (RKAS BIM + ARCHICAD Classification); Material: RAL7016
AR_Plaat - 002_Tähis: Varikatus; 325_Helipidavus: Undefined; 330_Tulekindlus: Undefined
AC_Pset_RenovationAndPhasing - Renovation Status: New
Pset_SlabCommon - LoadBearing: no; IsExternal: yes

# IfcSlab: RAL7016 50, Parapetiplekk
In: Teine korrus
Type - PredefinedType: ROOF
Classification: 1.19 IfcSlabType.ROOF (katus) (RKAS BIM + ARCHICAD Classification); Material: RAL7016 50 mm
AR_Plaat - 002_Tähis: Parapetiplekk; 325_Helipidavus: Undefined; 330_Tulekindlus: Undefined
AC_Pset_RenovationAndPhasing - Renovation Status: New
Pset_SlabCommon - LoadBearing: no; IsExternal: yes

# IfcSlab: Räästas 1_2K 1526 x 1052 (3)
In: Katusekorrus
Type - PredefinedType: ROOF
Classification: 1.19 IfcSlabType.ROOF (katus) (RKAS BIM + ARCHICAD Classification)
AR_Sein - 500_Kandev: yes
AR_Plaat - 002_Tähis: Räästas; 325_Helipidavus: Undefined; 330_Tulekindlus: Undefined
AC_Pset_RenovationAndPhasing - Renovation Status: New
Pset_SlabCommon - LoadBearing: no; IsExternal: yes

# IfcSlab: Räästas 2_2K 1556 x 1052 (2)
In: Katusekorrus
Type - PredefinedType: ROOF
Classification: 1.19 IfcSlabType.ROOF (katus) (RKAS BIM + ARCHICAD Classification)
AR_Sein - 500_Kandev: yes
AR_Plaat - 002_Tähis: Räästas; 325_Helipidavus: Undefined; 330_Tulekindlus: Undefined
AC_Pset_RenovationAndPhasing - Renovation Status: New
Pset_SlabCommon - LoadBearing: no; IsExternal: yes

# IfcSlab: Räästas_1_1K 1537 x 742 (16)
In: Katusekorrus
Type - PredefinedType: ROOF
Classification: 1.19 IfcSlabType.ROOF (katus) (RKAS BIM + ARCHICAD Classification)
AR_Sein - 500_Kandev: yes
AR_Plaat - 002_Tähis: Räästas; 325_Helipidavus: Undefined; 330_Tulekindlus: Undefined
AC_Pset_RenovationAndPhasing - Renovation Status: New
Pset_SlabCommon - LoadBearing: no; IsExternal: yes

# IfcSlab: SKR-02_Kipsplaat 13 (2)
In: Esimene korrus
Classification: 1.20 IfcSlabType (vahelagi) (RKAS BIM + ARCHICAD Classification); Material: SKR-02_Kipsplaat 13 mm
AR_Plaat - 001_Nimetus: Vahelagi; 002_Tähis: VL-01; 325_Helipidavus: 55 dB; 330_Tulekindlus: REI30; 505_Paksus: 13 mm; 500_Kandev: yes
AC_Pset_RenovationAndPhasing - Renovation Status: Existing
Pset_SlabCommon - LoadBearing: yes; IsExternal: no
Name | 515_Neto_pindala (m2)
VL-01 | 0.99089
VL-01 | 0.704919

# IfcSlab: SS-14 170, SS-14
In: Esimene korrus
Type - PredefinedType: ROOF
Classification: 1.19 IfcSlabType.ROOF (katus) (RKAS BIM + ARCHICAD Classification)
AR_Plaat - 330_Tulekindlus: EI30; 340_Soojusläbivus: 0; 325_Helipidavus: 52; 001_Nimetus: sisesein; 002_Tähis: SS-14
AC_Pset_RenovationAndPhasing - Renovation Status: New
Pset_SlabCommon - LoadBearing: no; IsExternal: no

# IfcSlab: VL-01_paneel 220, VL-01
In: Teine korrus
Classification: 1.20 IfcSlabType (vahelagi) (RKAS BIM + ARCHICAD Classification); Material: Olemasolev r/b paneel 220 mm 220 mm
AR_Plaat - 001_Nimetus: Vahelagi; 002_Tähis: VL-01; 325_Helipidavus: 55 dB; 330_Tulekindlus: REI30; 505_Paksus: 220 mm; 515_Neto_pindala: 360.995 m2; 500_Kandev: yes
AC_Pset_RenovationAndPhasing - Renovation Status: Existing
Pset_SlabCommon - LoadBearing: yes; IsExternal: no

# IfcSlab: VL-01_pealiskihid 130, VL-01
In: Teine korrus
Classification: 1.20 IfcSlabType (vahelagi) (RKAS BIM + ARCHICAD Classification)
AR_Plaat - 001_Nimetus: Vahelagi; 002_Tähis: VL-01; 325_Helipidavus: 55 dB; 330_Tulekindlus: REI30; 505_Paksus: 130 mm; 515_Neto_pindala: 342.591 m2; 500_Kandev: yes
AC_Pset_RenovationAndPhasing - Renovation Status: New
Pset_SlabCommon - LoadBearing: yes; IsExternal: no

# IfcSlab: VL-01_pealiskihid_dush 120, KL-01 ja KL-01.2 kalde ja pealiskihid
In: Teine korrus
Type - PredefinedType: ROOF
Classification: 1.19 IfcSlabType.ROOF (katus) (RKAS BIM + ARCHICAD Classification)
AR_Plaat - 340_Soojusläbivus: 0; 515_Neto_pindala: 0 m2; 001_Nimetus: katulagi; 002_Tähis: KL-01 ja KL-01.2 kalde ja pealiskihid; 325_Helipidavus: nõudeid ei esitata; 330_Tulekindlus: R60
AC_Pset_RenovationAndPhasing - Renovation Status: Existing
Pset_SlabCommon - LoadBearing: no; IsExternal: yes

# IfcSlab: VMR-01_Puit - Katus 271, Varikatus
In: Esimene korrus
Type - PredefinedType: ROOF
Classification: 1.19 IfcSlabType.ROOF (katus) (RKAS BIM + ARCHICAD Classification); Material: VMR-01_Puit - Katus
AR_Plaat - 002_Tähis: Varikatus; 325_Helipidavus: Undefined; 330_Tulekindlus: Undefined
AC_Pset_RenovationAndPhasing - Renovation Status: New
Pset_SlabCommon - LoadBearing: no; IsExternal: yes

# IfcSlab: Varikatuse aluskihid 271 (4)
Type - PredefinedType: ROOF
Classification: 1.19 IfcSlabType.ROOF (katus) (RKAS BIM + ARCHICAD Classification)
AR_Plaat - 002_Tähis: Varikatus; 325_Helipidavus: Undefined; 330_Tulekindlus: Undefined
AC_Pset_RenovationAndPhasing - Renovation Status: New
Pset_SlabCommon - LoadBearing: no; IsExternal: yes
Name | In
Varikatus | Teine korrus
3 x Varikatus | Katusekorrus

# IfcSlab: Varikatuse esiserv 447, Varikatus
In: Teine korrus
Type - PredefinedType: ROOF
Classification: 1.19 IfcSlabType.ROOF (katus) (RKAS BIM + ARCHICAD Classification)
AR_Plaat - 002_Tähis: Varikatus; 325_Helipidavus: Undefined; 330_Tulekindlus: Undefined
AC_Pset_RenovationAndPhasing - Renovation Status: New
Pset_SlabCommon - LoadBearing: no; IsExternal: yes

# IfcSlab: Varikatuse pealiskihid 423 (6)
Type - PredefinedType: ROOF
Classification: 1.19 IfcSlabType.ROOF (katus) (RKAS BIM + ARCHICAD Classification)
Pset_SlabCommon - LoadBearing: no; IsExternal: yes
Name | In | 340_Soojusläbivus = 515_Neto_pindala (m2) | 001_Nimetus | 002_Tähis | 325_Helipidavus | 330_Tulekindlus | Renovation Status
KL-01 ja KL-01.1 kalde ja pealiskihid | Teine korrus | 0 | katulagi | KL-01 ja KL-01.1 kalde ja pealiskihid | nõudeid ei esitata | R60 | Existing
2 x KL-01 ja KL-01.1 kalde ja pealiskihid | Katusekorrus | 0 | katulagi | KL-01 ja KL-01.1 kalde ja pealiskihid | nõudeid ei esitata | R60 | New
KL-01 | Katusekorrus | 0 | katuslagi | KL-01 | nõudeid ei esitata | R60 | New
KL-01 ja KL-01.2 kalde ja pealiskihid | Katusekorrus | 0 | katulagi | KL-01 ja KL-01.2 kalde ja pealiskihid | nõudeid ei esitata | R60 | Existing
Varikatus | Katusekorrus |  |  | Varikatus | Undefined | Undefined | New

# IfcSlab: Varikatuse pealiskihid_2 223 (3)
In: Katusekorrus
Type - PredefinedType: ROOF
Classification: 1.19 IfcSlabType.ROOF (katus) (RKAS BIM + ARCHICAD Classification)
AR_Plaat - 002_Tähis: Varikatus; 325_Helipidavus: Undefined; 330_Tulekindlus: Undefined
AC_Pset_RenovationAndPhasing - Renovation Status: New
Pset_SlabCommon - LoadBearing: no; IsExternal: yes

# IfcStair (64)
Classification: 1.22 IfcStair (trepp) (RKAS BIM + ARCHICAD Classification)
Name | In | Material | Reference | IsExternal | Renovation Status
11 x Trepp | Vundament | ET-02_Raudbetoon - Toode | Trepp | yes | New | AR_Sein - 500_Kandev: yes
16 x Välistrepp | Esimene korrus | KON-06_Raudbetoon - Konstruktsioon | Välistrepp | yes | New
TREPP | Esimene korrus |  | TREPP | no | Existing | Pset_StairCommon - NumberOfRiser: 11; NumberOfTreads: 10; RiserHeight: 150.909 mm; RequiredHeadroom: 2200 mm
Trepp | Esimene korrus | KON-00_GENEERILINE - KONSTRUKTSIOON | Trepp | no | Existing
TREPP | Esimene korrus |  | TREPP | no | Existing | Pset_StairCommon - NumberOfRiser: 11; NumberOfTreads: 11; RiserHeight: 153.636 mm; RequiredHeadroom: 2200 mm
7 x Vundament | Esimene korrus | KON-06_Raudbetoon - Konstruktsioon | Vundament | yes | New
8 x Teraspost | Esimene korrus | ET-05_Teras | Teraspost | yes | New
2 x Pandus | Esimene korrus | KON-06_Raudbetoon - Konstruktsioon | Pandus | yes | New
2 x Saunalava | Esimene korrus | SV-02_Puit - Põrand | Saunalava | no | New
Trepp | Esimene korrus |  | Trepp | yes | New | Pset_StairCommon - NumberOfRiser: 23; NumberOfTreads: 23; RiserHeight: 179.565 mm; RequiredHeadroom: 2200 mm
Trepp | Esimene korrus | KON-06_Raudbetoon - Konstruktsioon | Trepp | yes | New
2 x Vundament | Esimene korrus | KON-06_Raudbetoon - Konstruktsioon | Vundament | yes | Existing
Trepp | Teine korrus |  | Trepp | yes | New | Pset_StairCommon - NumberOfRiser: 20; NumberOfTreads: 20; RiserHeight: 220 mm; RequiredHeadroom: 2200 mm
Trepp | Teine korrus | ET-06_Teras - Konstruktsioon | Trepp | yes | New
TALA | Teine korrus | ET-05_Teras | TALA | yes | New
2 x TREPP | Teine korrus | KON-00_GENEERILINE - KONSTRUKTSIOON | TREPP | yes | Existing
TREPP | Teine korrus |  | TREPP | yes | Existing | Pset_StairCommon - NumberOfRiser: 19; NumberOfTreads: 19; RiserHeight: 189.474 mm; RequiredHeadroom: 2200 mm
TREPP | Teine korrus |  | TREPP | yes | Existing | Pset_StairCommon - NumberOfRiser: 16; NumberOfTreads: 16; RiserHeight: 192.677 mm; RequiredHeadroom: 2200 mm
TREPP | Teine korrus |  | TREPP | yes | Existing | Pset_StairCommon - NumberOfRiser: 19; NumberOfTreads: 19; RiserHeight: 188.684 mm; RequiredHeadroom: 2200 mm
Trepp | Katusekorrus | ET-06_Teras - Konstruktsioon | Trepp | yes | New
2 x TREPP | Katusekorrus | KON-00_GENEERILINE - KONSTRUKTSIOON | TREPP |  | Existing

# IfcWall: Karniis 25, Sahti sein
In: Esimene korrus
Classification: 1.24 IfcWallType (sein) (RKAS BIM + ARCHICAD Classification)
Pset_WallCommon - Reference: Karniis; LoadBearing: no; IsExternal: no
AR_Sein - 002_Tähis: Sahti sein; 325_Helipidavus: 24 dB; 330_Tulekindlus: nõudeid ei esitata; 335_Välispiire: no; 605_Neto_pindala: 1.17159 m2; 600_Bruto_pindala: 1.22313 m2; 500_Kandev: no; 505_Paksus: 25 mm
AC_Pset_RenovationAndPhasing - Renovation Status: Existing

# IfcWall: Olemasolev silikaltsiitplokk 340 (2)
In: Esimene korrus
Classification: 1.24 IfcWallType (sein) (RKAS BIM + ARCHICAD Classification); Material: Olemasolev silikaltsiitplokk
Pset_WallCommon - Reference: Olemasolev silikaltsiitplokk; LoadBearing: yes; IsExternal: yes
AR_Sein - 001_Nimetus: Ol.olev välissein; 002_Tähis: VS-03; 325_Helipidavus: 48 dB; 330_Tulekindlus: nõudeid ei esitata; 335_Välispiire: yes; 500_Kandev: yes; 505_Paksus: 340 mm; 340_Soojusläbivus: 0,10
AC_Pset_RenovationAndPhasing - Renovation Status: Existing
Name | 605_Neto_pindala (m2) | 600_Bruto_pindala (m2)
VS-03 | 17.5526 | 24.6747
VS-03 | 18.6404 | 25.753

# IfcWall: SS-04 170 (27)
In: Esimene korrus
Classification: 1.24 IfcWallType (sein) (RKAS BIM + ARCHICAD Classification)
AR_Sein - 500_Kandev: no; 335_Välispiire: no; 001_Nimetus: Sisesein; 002_Tähis: SS-04; 325_Helipidavus: 49 dB; 505_Paksus: 170 mm
Pset_WallCommon - Reference: SS-04; LoadBearing: no; IsExternal: no
AC_Pset_RenovationAndPhasing - Renovation Status: New
Name | 330_Tulekindlus | 605_Neto_pindala (m2) | 600_Bruto_pindala (m2)
SS-04 | nõudeid ei esitata | 5.7428 | 10.4807
SS-04 | nõudeid ei esitata | 7.79424 | 10.4742
SS-04 | nõudeid ei esitata | 8.53755 | 9.54895
SS-04 | nõudeid ei esitata | 32.6144 | 45.017
2 x SS-04 | nõudeid ei esitata | 11.9457 | 15.2457
SS-04 | nõudeid ei esitata | 14.3355 | 18.222
SS-04 | nõudeid ei esitata | 4.14085 | 4.44225
SS-04 | nõudeid ei esitata | 8.364 | 8.378
SS-04 | nõudeid ei esitata | 5.37172 | 7.21409
SS-04 | nõudeid ei esitata | 3.82122 | 5.49076
SS-04 | EI30 | 10.8538 | 11.3077
SS-04 | EI30 | 15.267 | 18.482
SS-04 | nõudeid ei esitata | 11.1897 | 12.9535
SS-04 | EI30 | 14.162 | 17.2575
SS-04 | nõudeid ei esitata | 13.0802 | 13.6716
SS-04 | EI30 | 7.9398 | 7.965
SS-04 | EI30 | 15.2457 | 15.4061
SS-04 | nõudeid ei esitata | 10.8538 | 11.3077
SS-04 | nõudeid ei esitata | 3.72145 | 8.79706
SS-04 | nõudeid ei esitata | 15.624 | 21.5034
SS-04 | nõudeid ei esitata | 10.3052 | 12.9603
SS-04 | nõudeid ei esitata | 13.614 | 14.4995
SS-04 | EI30 | 8.40979 | 14.5447
SS-04 | EI30 | 1.56687 | 2.24707
SS-04 | nõudeid ei esitata | 8.8615 | 13.983
SS-04 | nõudeid ei esitata | 5.2965 | 8.437

# IfcWall: SS-05_sisekihid 101 (22)
Classification: 1.24 IfcWallType (sein) (RKAS BIM + ARCHICAD Classification)
AR_Sein - 500_Kandev: no; 335_Välispiire: no; 001_Nimetus: Sisesein; 002_Tähis: SS-05; 325_Helipidavus: 64 dB; 505_Paksus: 101 mm
Pset_WallCommon - Reference: SS-05; LoadBearing: no; IsExternal: no
AC_Pset_RenovationAndPhasing - Renovation Status: New
Name | In | 330_Tulekindlus | 605_Neto_pindala (m2) | 600_Bruto_pindala (m2)
SS-05 | Esimene korrus | EI30 | 16.728 | 18.0949
SS-05 | Esimene korrus | EI30 | 16.728 | 17.1985
SS-05 | Teine korrus | EI30 | 5.812 | 8.21456
SS-05 | Teine korrus | EI30 | 15.7558 | 17.5355
SS-05 | Teine korrus | nõudeid ei esitata | 7.42 | 9.702
SS-05 | Teine korrus | nõudeid ei esitata | 8.17936 | 10.3578
SS-05 | Teine korrus | nõudeid ei esitata | 7.76915 | 7.97619
SS-05 | Teine korrus | nõudeid ei esitata | 11.024 | 12.2592
SS-05 | Teine korrus | nõudeid ei esitata | 11.1466 | 12.409
SS-05 | Teine korrus | nõudeid ei esitata | 9.64311 | 11.9366
SS-05 | Teine korrus | nõudeid ei esitata | 8.66488 | 8.85206
SS-05 | Teine korrus | nõudeid ei esitata | 32.8012 | 35.2762
SS-05 | Teine korrus | nõudeid ei esitata | 14.5581 | 17.0404
SS-05 | Teine korrus | nõudeid ei esitata | 11.1472 | 12.4096
SS-05 | Teine korrus | nõudeid ei esitata | 11.0252 | 12.2604
SS-05 | Teine korrus | EI30 | 15.7558 | 17.5542
SS-05 | Teine korrus | nõudeid ei esitata | 14.3422 | 16.6492
SS-05 | Teine korrus | nõudeid ei esitata | 4.2256 | 8.4378
SS-05 | Teine korrus | nõudeid ei esitata | 6.07852 | 8.3669
SS-05 | Teine korrus | nõudeid ei esitata | 9.16763 | 10.3835
SS-05 | Teine korrus | nõudeid ei esitata | 42.5162 | 53.9755
SS-05 | Teine korrus | nõudeid ei esitata | 80.2061 | 90.4037

# IfcWall: SS-06_sisekihid 101 (3)
In: Teine korrus
Classification: 1.24 IfcWallType (sein) (RKAS BIM + ARCHICAD Classification)
AR_Sein - 500_Kandev: no; 335_Välispiire: no; 001_Nimetus: Sisesein; 002_Tähis: SS-06; 325_Helipidavus: 64 dB; 330_Tulekindlus: nõudeid ei esitata; 505_Paksus: 101 mm
Pset_WallCommon - Reference: SS-06; LoadBearing: no; IsExternal: no
Name | 605_Neto_pindala (m2) | 600_Bruto_pindala (m2) | Renovation Status
SS-06 | 11.1117 | 13.5746 | New
SS-06 | 11.11 | 13.5727 | New
SS-06 | 8.29704 | 8.29704 | Existing

# IfcWall: SS-07_sisekihid 101 (2)
In: Teine korrus
Classification: 1.24 IfcWallType (sein) (RKAS BIM + ARCHICAD Classification)
AR_Sein - 335_Välispiire: no; 500_Kandev: no; 001_Nimetus: Sisesein; 002_Tähis: SS-07; 330_Tulekindlus: nõudeid ei esitata; 505_Paksus: 101 mm
Pset_WallCommon - Reference: SS-07; LoadBearing: no; IsExternal: no
AC_Pset_RenovationAndPhasing - Renovation Status: New
Name | 325_Helipidavus | 605_Neto_pindala (m2) | 600_Bruto_pindala (m2)
SS-07 | 55 dB | 17.1307 | 19.1191
SS-07 | 64 dB | 5.5582 | 9.9666

# IfcWall: SS-08 sisekihid 101 (2)
In: Teine korrus
Classification: 1.24 IfcWallType (sein) (RKAS BIM + ARCHICAD Classification)
AR_Sein - 335_Välispiire: no; 500_Kandev: no; 001_Nimetus: Sisesein; 002_Tähis: SS-08; 325_Helipidavus: 48 dB; 330_Tulekindlus: nõudeid ei esitata; 505_Paksus: 101 mm
Pset_WallCommon - Reference: SS-08 sisekihid; LoadBearing: no; IsExternal: no
AC_Pset_RenovationAndPhasing - Renovation Status: New
Name | 605_Neto_pindala (m2) | 600_Bruto_pindala (m2)
SS-08 | 8.66426 | 9.16381
SS-08 | 11.6903 | 19.0853

# IfcWall: SS-08.1 250, SS-08.1
In: Teine korrus
Classification: 1.24 IfcWallType (sein) (RKAS BIM + ARCHICAD Classification)
AR_Sein - 500_Kandev: no; 335_Välispiire: no; 001_Nimetus: Ol.olev sisesein; 002_Tähis: SS-08.1; 325_Helipidavus: 48 dB; 330_Tulekindlus: nõudeid ei esitata; 605_Neto_pindala: 8.2022 m2; 600_Bruto_pindala: 10.9292 m2; 505_Paksus: 250 mm
Pset_WallCommon - Reference: SS-08.1; LoadBearing: no; IsExternal: no
AC_Pset_RenovationAndPhasing - Renovation Status: Existing

# IfcWall: SS-08.1 sisekihid 108, SS-8.1
In: Teine korrus
Classification: 1.24 IfcWallType (sein) (RKAS BIM + ARCHICAD Classification)
AR_Sein - 500_Kandev: no; 335_Välispiire: no; 002_Tähis: SS-8.1; 325_Helipidavus: 64 dB; 330_Tulekindlus: nõudeid ei esitata; 605_Neto_pindala: 6.62293 m2; 600_Bruto_pindala: 7.36835 m2; 505_Paksus: 108 mm
Pset_WallCommon - Reference: SS-08.1 sisekihid; LoadBearing: no; IsExternal: no
AC_Pset_RenovationAndPhasing - Renovation Status: New

# IfcWall: SS-09_sisekihid 108 (3)
In: Teine korrus
Classification: 1.24 IfcWallType (sein) (RKAS BIM + ARCHICAD Classification)
AR_Sein - 500_Kandev: no; 335_Välispiire: no; 001_Nimetus: Sisesein; 002_Tähis: SS-09; 325_Helipidavus: 64 dB; 330_Tulekindlus: nõudeid ei esitata; 505_Paksus: 108 mm
Pset_WallCommon - Reference: SS-09; LoadBearing: no; IsExternal: no
AC_Pset_RenovationAndPhasing - Renovation Status: New
Name | 605_Neto_pindala (m2) | 600_Bruto_pindala (m2)
SS-09 | 9.14743 | 11.2604
SS-09 | 9.14743 | 11.4782
SS-09 | 1.55774 | 5.49757

# IfcWall: SS-12 sisekihid 207 (2)
In: Esimene korrus
Classification: 1.24 IfcWallType (sein) (RKAS BIM + ARCHICAD Classification)
Pset_WallCommon - Reference: SS-12 sisekihid; LoadBearing: no; IsExternal: yes
AR_Sein - 001_Nimetus: Sisesein; 002_Tähis: SS-12; 325_Helipidavus: 55 dB; 335_Välispiire: no; 500_Kandev: no; 505_Paksus: 207 mm
AC_Pset_RenovationAndPhasing - Renovation Status: New
Name | 330_Tulekindlus | 605_Neto_pindala (m2) | 600_Bruto_pindala (m2)
SS-12 | EI30 | 4.97088 | 6.15848
SS-12 | nõudeid ei esitata | 8.32178 | 11.2459

# IfcWall: SS-14 170 (3)
In: Teine korrus
Classification: 1.24 IfcWallType (sein) (RKAS BIM + ARCHICAD Classification)
AR_Sein - 500_Kandev: no; 335_Välispiire: no; 001_Nimetus: Sisesein; 002_Tähis: SS-14; 325_Helipidavus: 52 dB; 330_Tulekindlus: nõudeid ei esitata; 505_Paksus: 170 mm
Pset_WallCommon - Reference: SS-14; LoadBearing: no; IsExternal: no
AC_Pset_RenovationAndPhasing - Renovation Status: New
Name | 605_Neto_pindala (m2) | 600_Bruto_pindala (m2)
SS-14 | 4.7524 | 8.4378
SS-14 | 1.68781 | 2.00533
SS-14 | 5.6762 | 6.03194

# IfcWall: Sahti sein 75 (2)
In: Esimene korrus
Classification: 1.24 IfcWallType (sein) (RKAS BIM + ARCHICAD Classification)
Pset_WallCommon - Reference: Sahti sein; LoadBearing: no; IsExternal: no
AR_Sein - 002_Tähis: Sahti sein; 325_Helipidavus: 24 dB; 330_Tulekindlus: nõudeid ei esitata; 335_Välispiire: no; 500_Kandev: no; 505_Paksus: 75 mm
AC_Pset_RenovationAndPhasing - Renovation Status: New
Name | 605_Neto_pindala (m2) | 600_Bruto_pindala (m2)
Sahti sein | 1.2015 | 1.2015
Sahti sein | 1.18147 | 2.09595

# IfcWall: VS-01 221 (22)
In: Vundament
Classification: 1.24 IfcWallType (sein) (RKAS BIM + ARCHICAD Classification)
Pset_WallCommon - Reference: VS-01; LoadBearing: no; IsExternal: yes
AR_Sein - 001_Nimetus: Vundamendi soojustus; 002_Tähis: VS-01; 325_Helipidavus: nõudeid ei esitata; 330_Tulekindlus: Undefined; 335_Välispiire: yes; 500_Kandev: no; 505_Paksus: 221 mm; 340_Soojusläbivus: 0,16
AC_Pset_RenovationAndPhasing - Renovation Status: New
Name | 605_Neto_pindala (m2) | 600_Bruto_pindala (m2)
VS-01 | 3.65548 | 3.89669
VS-01 | 22.5264 | 22.5504
VS-01 | 3.624 | 3.8892
VS-01 | 7.21179 | 7.47699
2 x VS-01 | 3.6 | 3.8652
VS-01 | 7.176 | 7.4412
VS-01 | 10.488 | 10.7532
VS-01 | 15.1921 | 15.4573
VS-01 | 4.356 | 4.4412
VS-01 | 2.95602 | 6.564
VS-01 | 26.016 | 26.1012
VS-01 | 16.2025 | 16.2265
VS-01 | 7.15179 | 7.41699
VS-01 | 3.46734 | 3.73254
VS-01 | 7.2 | 7.4652
VS-01 | 20.6496 | 21.156
VS-01 | 3.59893 | 3.86413
VS-01 | 6.082 | 8.05481
VS-01 | 10.9574 | 15.6992
VS-01 | 7.10436 | 7.39358
VS-01 | 32.7487 | 33.0139

# IfcWall: VS-01.1 71 (6)
In: Vundament
Classification: 1.24 IfcWallType (sein) (RKAS BIM + ARCHICAD Classification)
Pset_WallCommon - Reference: VS-01.1; LoadBearing: no; IsExternal: yes
AR_Sein - 001_Nimetus: Vundamendi soojustus; 002_Tähis: VS-01.1; 325_Helipidavus: nõudeid ei esitata; 330_Tulekindlus: Undefined; 335_Välispiire: yes; 500_Kandev: no; 505_Paksus: 71 mm; 340_Soojusläbivus: 0,16
AC_Pset_RenovationAndPhasing - Renovation Status: New
Name | 605_Neto_pindala (m2) | 600_Bruto_pindala (m2)
2 x VS-01.1 | 2.676 | 2.9412
2 x VS-01.1 | 0.5064 | 0.5304
2 x VS-01.1 | 2.67601 | 2.94121

# IfcWall: VS-02_olol 320, VS-02
In: Esimene korrus
Classification: 1.24 IfcWallType (sein) (RKAS BIM + ARCHICAD Classification); Material: Olemasolev silikaltsiitpaneel
Pset_WallCommon - Reference: VS-02; LoadBearing: yes; IsExternal: yes
AR_Sein - 001_Nimetus: Ol.olev välissein; 002_Tähis: VS-02; 325_Helipidavus: 48 dB; 330_Tulekindlus: nõudeid ei esitata; 335_Välispiire: yes; 605_Neto_pindala: 26.079 m2; 600_Bruto_pindala: 61.248 m2; 500_Kandev: yes; 505_Paksus: 320 mm; 340_Soojusläbivus: 0,10
AC_Pset_RenovationAndPhasing - Renovation Status: Existing

# IfcWall: VS-02_uued_kihid 300 (7)
Classification: 1.24 IfcWallType (sein) (RKAS BIM + ARCHICAD Classification)
Pset_WallCommon - Reference: VS-02; LoadBearing: no; IsExternal: yes
AR_Sein - 001_Nimetus: Ol.olev välissein; 002_Tähis: VS-02; 325_Helipidavus: 48 dB; 330_Tulekindlus: nõudeid ei esitata; 335_Välispiire: yes; 500_Kandev: no; 505_Paksus: 300 mm; 340_Soojusläbivus: 0,10
AC_Pset_RenovationAndPhasing - Renovation Status: New
Name | In | 605_Neto_pindala (m2) | 600_Bruto_pindala (m2)
VS-02 | Esimene korrus | 39.2246 | 92.103
VS-02 | Esimene korrus | 39.2819 | 91.0818
VS-02 | Esimene korrus | 6.53186 | 12.507
VS-02 | Teine korrus | 38.2747 | 93.1989
VS-02 | Teine korrus | 40.719 | 41.5046
VS-02 | Teine korrus | 38.745 | 93.198
VS-02 | Teine korrus | 41.1118 | 41.5046

# IfcWall: VS-03.1A _uued_kihid 250, VS-03.1
In: Esimene korrus
Classification: 1.24 IfcWallType (sein) (RKAS BIM + ARCHICAD Classification)
Pset_WallCommon - Reference: VS-03.1A; LoadBearing: no; IsExternal: yes
AR_Sein - 001_Nimetus: Ol.olev välissein; 002_Tähis: VS-03.1; 325_Helipidavus: 48 dB; 330_Tulekindlus: EI30; 335_Välispiire: yes; 605_Neto_pindala: 7.2982 m2; 600_Bruto_pindala: 13.5952 m2; 500_Kandev: no; 505_Paksus: 250 mm; 340_Soojusläbivus: 0,10
AC_Pset_RenovationAndPhasing - Renovation Status: New

# IfcWall: VS-03.1B_uued_kihid 180, VS-03.1
In: Esimene korrus
Classification: 1.24 IfcWallType (sein) (RKAS BIM + ARCHICAD Classification)
Pset_WallCommon - Reference: VS-03.1B; LoadBearing: no; IsExternal: yes
AR_Sein - 001_Nimetus: Ol.olev välissein; 002_Tähis: VS-03.1; 325_Helipidavus: 48 dB; 330_Tulekindlus: nõudeid ei esitata; 335_Välispiire: yes; 605_Neto_pindala: 2.3625 m2; 600_Bruto_pindala: 2.3625 m2; 500_Kandev: no; 505_Paksus: 180 mm; 340_Soojusläbivus: 0,10
AC_Pset_RenovationAndPhasing - Renovation Status: New

# IfcWall: VS-03.1_uued_kihid 250 (8)
Classification: 1.24 IfcWallType (sein) (RKAS BIM + ARCHICAD Classification)
Pset_WallCommon - Reference: VS-03.1; LoadBearing: no; IsExternal: yes
AR_Sein - 001_Nimetus: Ol.olev välissein; 002_Tähis: VS-03.1; 325_Helipidavus: 48 dB; 330_Tulekindlus: nõudeid ei esitata; 335_Välispiire: yes; 500_Kandev: no; 505_Paksus: 250 mm; 340_Soojusläbivus: 0,10
AC_Pset_RenovationAndPhasing - Renovation Status: New
Name | In | 605_Neto_pindala (m2) | 600_Bruto_pindala (m2)
VS-03.1 | Esimene korrus | 2.985 | 2.985
3 x VS-03.1 | Esimene korrus | 4.4402 | 4.4402
VS-03.1 | Esimene korrus | 2.15 | 4.95
VS-03.1 | Esimene korrus | 4.95 | 4.95
VS-03.1 | Teine korrus | 2.32366 | 2.33701
VS-03.1 | Teine korrus | 2.37489 | 5.17489

# IfcWall: VS-03A_uued_kihid 300, VS-03
In: Teine korrus
Classification: 1.24 IfcWallType (sein) (RKAS BIM + ARCHICAD Classification)
Pset_WallCommon - Reference: VS-03A; LoadBearing: no; IsExternal: yes
AR_Sein - 001_Nimetus: Ol.olev välissein; 002_Tähis: VS-03; 325_Helipidavus: 48 dB; 330_Tulekindlus: nõudeid ei esitata; 335_Välispiire: yes; 605_Neto_pindala: 11.4311 m2; 600_Bruto_pindala: 11.4311 m2; 500_Kandev: no; 505_Paksus: 300 mm; 340_Soojusläbivus: 0,10
AC_Pset_RenovationAndPhasing - Renovation Status: New

# IfcWall: VS-03B_uued kihid 300 (2)
Classification: 1.24 IfcWallType (sein) (RKAS BIM + ARCHICAD Classification)
Pset_WallCommon - Reference: VS-03B; LoadBearing: no; IsExternal: yes
AR_Sein - 001_Nimetus: Ol.olev välissein; 002_Tähis: VS-03; 325_Helipidavus: 48 dB; 330_Tulekindlus: nõudeid ei esitata; 335_Välispiire: yes; 500_Kandev: no; 505_Paksus: 300 mm; 340_Soojusläbivus: 0,10
AC_Pset_RenovationAndPhasing - Renovation Status: New
Name | In | 605_Neto_pindala (m2) | 600_Bruto_pindala (m2)
VS-03 | Esimene korrus | 22.11 | 23.1
VS-03 | Teine korrus | 20.2272 | 25.2252

# IfcWall: VS-03C_uued_kihid 300 (3)
In: Esimene korrus
Classification: 1.24 IfcWallType (sein) (RKAS BIM + ARCHICAD Classification)
Pset_WallCommon - Reference: VS-03C; LoadBearing: no; IsExternal: yes
AR_Sein - 001_Nimetus: Ol.olev välissein; 002_Tähis: VS-03; 325_Helipidavus: 48 dB; 335_Välispiire: yes; 500_Kandev: no; 505_Paksus: 300 mm; 340_Soojusläbivus: 0,10
AC_Pset_RenovationAndPhasing - Renovation Status: New
Name | 330_Tulekindlus | 605_Neto_pindala (m2) | 600_Bruto_pindala (m2)
VS-03 | nõudeid ei esitata | 36.9193 | 54.1544
VS-03 | nõudeid ei esitata | 20.144 | 28.0997
VS-03 | EI30 | 29.6607 | 29.8977

# IfcWall: VS-03D_uued_kihid 300 (5)
In: Esimene korrus
Classification: 1.24 IfcWallType (sein) (RKAS BIM + ARCHICAD Classification)
Pset_WallCommon - Reference: VS-03D; LoadBearing: no; IsExternal: yes
AR_Sein - 325_Helipidavus: 48 dB; 335_Välispiire: yes; 500_Kandev: no; 505_Paksus: 300 mm
AC_Pset_RenovationAndPhasing - Renovation Status: New
Name | 001_Nimetus | 002_Tähis | 330_Tulekindlus | 605_Neto_pindala (m2) | 600_Bruto_pindala (m2) | 340_Soojusläbivus
VS-03 | Ol.olev välissein | VS-03 | nõudeid ei esitata | 35.5421 | 72.1067 | 0,10
VS-03 | Ol.olev välissein | VS-03 | nõudeid ei esitata | 14.7649 | 15.3784 | 0,10
VS-08 | Välissein | VS-08 | nõudeid ei esitata | 3.1493 | 10.3068 | 0,09
VS-03 | Ol.olev välissein | VS-03 | EI30 | 11.6619 | 13.5025 | 0,10
VS-03 | Ol.olev välissein | VS-03 | EI30 | 19.9787 | 25.5229 | 0,10

# IfcWall: VS-03E_uuedkihid 300, VS-03
In: Esimene korrus
Classification: 1.24 IfcWallType (sein) (RKAS BIM + ARCHICAD Classification)
Pset_WallCommon - Reference: VS-03E; LoadBearing: no; IsExternal: yes
AR_Sein - 001_Nimetus: Ol.olev välissein; 002_Tähis: VS-03; 325_Helipidavus: 48 dB; 330_Tulekindlus: EI30; 335_Välispiire: yes; 605_Neto_pindala: 12.27 m2; 600_Bruto_pindala: 13.497 m2; 500_Kandev: no; 505_Paksus: 300 mm; 340_Soojusläbivus: 0,10
AC_Pset_RenovationAndPhasing - Renovation Status: New

# IfcWall: VS-03F_uued_kihid 300, VS-03
In: Esimene korrus
Classification: 1.24 IfcWallType (sein) (RKAS BIM + ARCHICAD Classification)
Pset_WallCommon - Reference: VS-03F; LoadBearing: no; IsExternal: yes
AR_Sein - 001_Nimetus: Ol.olev välissein; 002_Tähis: VS-03; 325_Helipidavus: 48 dB; 330_Tulekindlus: nõudeid ei esitata; 335_Välispiire: yes; 605_Neto_pindala: 18.6497 m2; 600_Bruto_pindala: 25.8072 m2; 500_Kandev: no; 505_Paksus: 300 mm; 340_Soojusläbivus: 0,10
AC_Pset_RenovationAndPhasing - Renovation Status: New

# IfcWall: VS-03G_uued_kihid 300, VS-03
In: Esimene korrus
Classification: 1.24 IfcWallType (sein) (RKAS BIM + ARCHICAD Classification)
Pset_WallCommon - Reference: VS-03G; LoadBearing: no; IsExternal: yes
AR_Sein - 001_Nimetus: Ol.olev välissein; 002_Tähis: VS-03; 325_Helipidavus: 48 dB; 330_Tulekindlus: EI30; 335_Välispiire: yes; 605_Neto_pindala: 12.3518 m2; 600_Bruto_pindala: 13.5788 m2; 500_Kandev: no; 505_Paksus: 300 mm; 340_Soojusläbivus: 0,10
AC_Pset_RenovationAndPhasing - Renovation Status: New

# IfcWall: VS-03H_uued_kihid 300 (2)
In: Esimene korrus
Classification: 1.24 IfcWallType (sein) (RKAS BIM + ARCHICAD Classification)
Pset_WallCommon - Reference: VS-03H; LoadBearing: no; IsExternal: yes
AR_Sein - 001_Nimetus: Ol.olev välissein; 002_Tähis: VS-03; 325_Helipidavus: 48 dB; 330_Tulekindlus: nõudeid ei esitata; 335_Välispiire: yes; 500_Kandev: no; 505_Paksus: 300 mm; 340_Soojusläbivus: 0,10
AC_Pset_RenovationAndPhasing - Renovation Status: New
Name | 605_Neto_pindala (m2) | 600_Bruto_pindala (m2)
VS-03 | 18.6075 | 24.538
VS-03 | 20.5727 | 27.1167

# IfcWall: VS-03I_uuedkihid 300 (2)
In: Esimene korrus
Classification: 1.24 IfcWallType (sein) (RKAS BIM + ARCHICAD Classification)
Pset_WallCommon - Reference: VS-03I; LoadBearing: no; IsExternal: yes
AR_Sein - 001_Nimetus: Ol.olev välissein; 002_Tähis: VS-03; 325_Helipidavus: 48 dB; 335_Välispiire: yes; 500_Kandev: no; 505_Paksus: 300 mm; 340_Soojusläbivus: 0,10
AC_Pset_RenovationAndPhasing - Renovation Status: New
Name | 330_Tulekindlus | 605_Neto_pindala (m2) | 600_Bruto_pindala (m2)
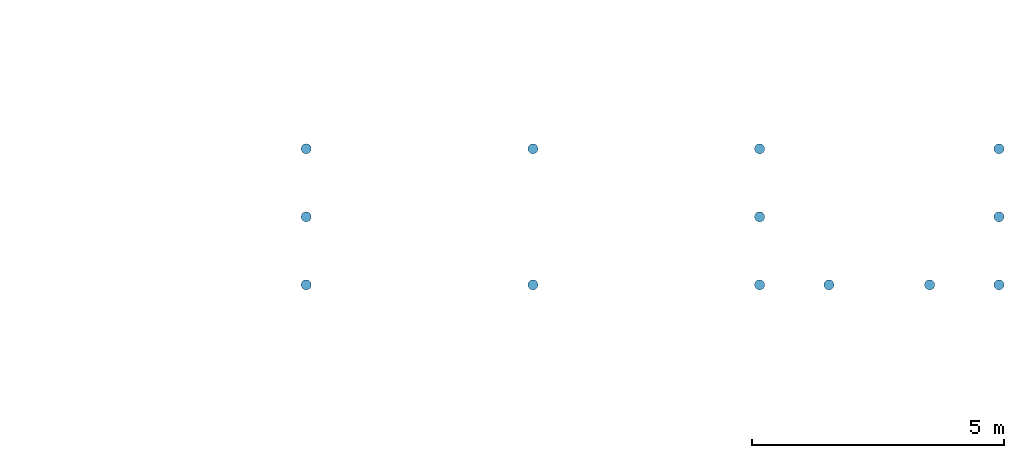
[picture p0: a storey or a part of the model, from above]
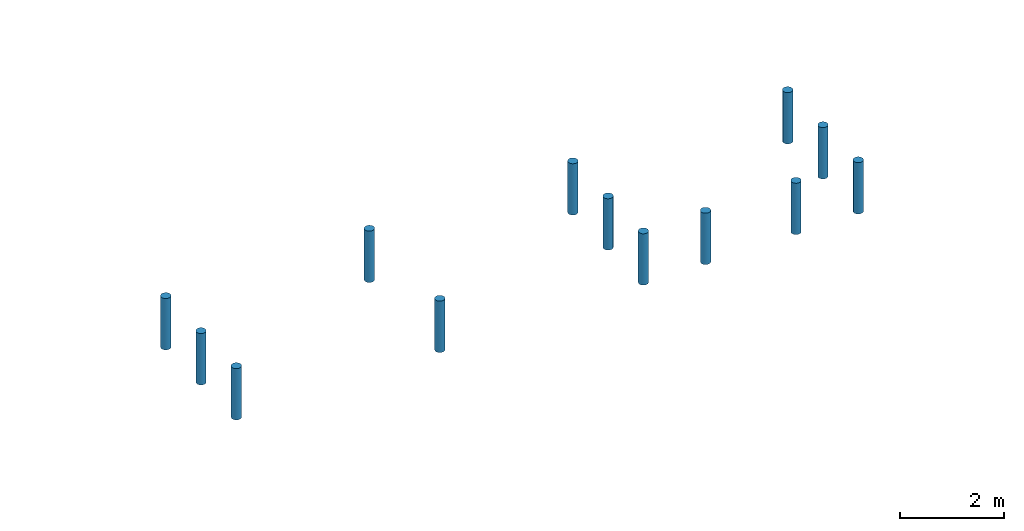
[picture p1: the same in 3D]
Properties of the parts of a building model (IFC2X3), part 4 of 5

# IfcWall: VS-03I_uuedkihid 300 (2)
Name | 330_Tulekindlus | 605_Neto_pindala (m2) | 600_Bruto_pindala (m2)
VS-03 | EI30 | 16.3547 | 17.3772
VS-03 | nõudeid ei esitata | 2.33862 | 8.26912

# IfcWall: VS-03J_uued_kihid 300, VS-03
In: Esimene korrus
Classification: 1.24 IfcWallType (sein) (RKAS BIM + ARCHICAD Classification)
Pset_WallCommon - Reference: VS-03J; LoadBearing: no; IsExternal: yes
AR_Sein - 001_Nimetus: Ol.olev välissein; 002_Tähis: VS-03; 325_Helipidavus: 48 dB; 330_Tulekindlus: nõudeid ei esitata; 335_Välispiire: yes; 605_Neto_pindala: 10.395 m2; 600_Bruto_pindala: 13.497 m2; 500_Kandev: no; 505_Paksus: 300 mm; 340_Soojusläbivus: 0,10
AC_Pset_RenovationAndPhasing - Renovation Status: New

# IfcWall: VS-03K_uued_kihid 300, VS-03
In: Esimene korrus
Classification: 1.24 IfcWallType (sein) (RKAS BIM + ARCHICAD Classification)
Pset_WallCommon - Reference: VS-03K; LoadBearing: no; IsExternal: yes
AR_Sein - 001_Nimetus: Ol.olev välissein; 002_Tähis: VS-03; 325_Helipidavus: 48 dB; 330_Tulekindlus: nõudeid ei esitata; 335_Välispiire: yes; 605_Neto_pindala: 16.7274 m2; 600_Bruto_pindala: 17.3409 m2; 500_Kandev: no; 505_Paksus: 300 mm; 340_Soojusläbivus: 0,10
AC_Pset_RenovationAndPhasing - Renovation Status: New

# IfcWall: VS-03L_uued_kihid 300, VS-03
In: Esimene korrus
Classification: 1.24 IfcWallType (sein) (RKAS BIM + ARCHICAD Classification)
Pset_WallCommon - Reference: VS-03L; LoadBearing: no; IsExternal: yes
AR_Sein - 001_Nimetus: Ol.olev välissein; 002_Tähis: VS-03; 325_Helipidavus: 48 dB; 330_Tulekindlus: nõudeid ei esitata; 335_Välispiire: yes; 605_Neto_pindala: 3.3136 m2; 600_Bruto_pindala: 8.4261 m2; 500_Kandev: no; 505_Paksus: 300 mm; 340_Soojusläbivus: 0,10
AC_Pset_RenovationAndPhasing - Renovation Status: New

# IfcWall: VS-03M_uued_kihid 300 (3)
In: Esimene korrus
Classification: 1.24 IfcWallType (sein) (RKAS BIM + ARCHICAD Classification)
Pset_WallCommon - Reference: VS-03M; LoadBearing: no; IsExternal: yes
AR_Sein - 325_Helipidavus: 48 dB; 335_Välispiire: yes; 500_Kandev: no; 505_Paksus: 300 mm
AC_Pset_RenovationAndPhasing - Renovation Status: New
Name | 001_Nimetus | 002_Tähis | 330_Tulekindlus | 605_Neto_pindala (m2) | 600_Bruto_pindala (m2) | 340_Soojusläbivus
VS-03 | Ol.olev välissein | VS-03 | EI30 | 9.1207 | 9.1207 | 0,10
VS-07 | Välissein | VS-07 | EI30 | 10.0205 | 11.2475 | 0,07
VS-03 | Ol.olev välissein | VS-03 | nõudeid ei esitata | 5.0793 | 5.3163 | 0,10

# IfcWall: VS-03N_uued_kihid 300, VS-03
In: Esimene korrus
Classification: 1.24 IfcWallType (sein) (RKAS BIM + ARCHICAD Classification)
Pset_WallCommon - Reference: VS-03N; LoadBearing: no; IsExternal: yes
AR_Sein - 001_Nimetus: Ol.olev välissein; 002_Tähis: VS-03; 325_Helipidavus: 48 dB; 330_Tulekindlus: nõudeid ei esitata; 335_Välispiire: yes; 605_Neto_pindala: 8.1349 m2; 600_Bruto_pindala: 15.9034 m2; 500_Kandev: no; 505_Paksus: 300 mm; 340_Soojusläbivus: 0,10
AC_Pset_RenovationAndPhasing - Renovation Status: New

# IfcWall: VS-03_uued_kihid 300 (7)
Classification: 1.24 IfcWallType (sein) (RKAS BIM + ARCHICAD Classification)
Pset_WallCommon - Reference: VS-03; LoadBearing: no; IsExternal: yes
AR_Sein - 001_Nimetus: Ol.olev välissein; 002_Tähis: VS-03; 325_Helipidavus: 48 dB; 330_Tulekindlus: nõudeid ei esitata; 335_Välispiire: yes; 500_Kandev: no; 505_Paksus: 300 mm; 340_Soojusläbivus: 0,10
AC_Pset_RenovationAndPhasing - Renovation Status: New
Name | In | 605_Neto_pindala (m2) | 600_Bruto_pindala (m2)
VS-03 | Esimene korrus | 14.1573 | 19.6023
VS-03 | Esimene korrus | 38.0423 | 45.0123
VS-03 | Teine korrus | 15.4367 | 17.8589
VS-03 | Teine korrus | 13.7411 | 14.8739
VS-03 | Teine korrus | 15.2859 | 17.8589
VS-03 | Teine korrus | 1.9992 | 2.8812
VS-03 | Teine korrus | 21.2325 | 25.7895

# IfcWall: VS-04_uued_kihid 300 (5)
Classification: 1.24 IfcWallType (sein) (RKAS BIM + ARCHICAD Classification)
Pset_WallCommon - Reference: VS-04; LoadBearing: no; IsExternal: yes
AR_Sein - 001_Nimetus: Välissein; 002_Tähis: VS-04; 325_Helipidavus: 48 dB; 330_Tulekindlus: nõudeid ei esitata; 335_Välispiire: yes; 500_Kandev: no; 505_Paksus: 300 mm; 340_Soojusläbivus: 0,10
AC_Pset_RenovationAndPhasing - Renovation Status: New
Name | In | 605_Neto_pindala (m2) | 600_Bruto_pindala (m2)
VS-04 | Esimene korrus | 10.9162 | 46.6384
VS-04 | Esimene korrus | 1.225 | 5.425
VS-04 | Esimene korrus | 7.6825 | 37.0825
VS-04 | Teine korrus | 11.259 | 53.235
VS-04 | Teine korrus | 11.13 | 53.8125

# IfcWall: VS-04_uued_sisekihid 63 (6)
Classification: 1.24 IfcWallType (sein) (RKAS BIM + ARCHICAD Classification)
Pset_WallCommon - Reference: VS-04; LoadBearing: yes; IsExternal: yes
AR_Sein - 001_Nimetus: Välissein; 002_Tähis: VS-04; 325_Helipidavus: 48 dB; 330_Tulekindlus: nõudeid ei esitata; 335_Välispiire: yes; 500_Kandev: yes; 505_Paksus: 63 mm; 340_Soojusläbivus: 0,10
AC_Pset_RenovationAndPhasing - Renovation Status: New
Name | In | 605_Neto_pindala (m2) | 600_Bruto_pindala (m2)
VS-04 | Esimene korrus | 6.418 | 31.8675
VS-04 | Esimene korrus | 1.225 | 5.425
VS-04 | Esimene korrus | 7.385 | 37.0825
VS-04 | Esimene korrus | 0.595963 | 4.79596
VS-04 | Teine korrus | 11.235 | 53.235
VS-04 | Teine korrus | 10.976 | 53.8125

# IfcWall: VS-05B_uued_kihid 270, VS-05
In: Esimene korrus
Classification: 1.24 IfcWallType (sein) (RKAS BIM + ARCHICAD Classification)
Pset_WallCommon - Reference: VS-05B; LoadBearing: no; IsExternal: yes
AR_Sein - 001_Nimetus: Välissein; 002_Tähis: VS-05; 325_Helipidavus: 48 dB; 330_Tulekindlus: nõudeid ei esitata; 335_Välispiire: yes; 605_Neto_pindala: 3.4655 m2; 600_Bruto_pindala: 5.9305 m2; 500_Kandev: no; 505_Paksus: 270 mm; 340_Soojusläbivus: 0,08
AC_Pset_RenovationAndPhasing - Renovation Status: New

# IfcWall: VS-05C_uued_kihid 370, VS-05
In: Esimene korrus
Classification: 1.24 IfcWallType (sein) (RKAS BIM + ARCHICAD Classification)
Pset_WallCommon - Reference: VS-05C; LoadBearing: no; IsExternal: yes
AR_Sein - 001_Nimetus: Välissein; 002_Tähis: VS-05; 325_Helipidavus: 48 dB; 330_Tulekindlus: nõudeid ei esitata; 335_Välispiire: yes; 605_Neto_pindala: 3.4655 m2; 600_Bruto_pindala: 5.9305 m2; 500_Kandev: no; 505_Paksus: 370 mm; 340_Soojusläbivus: 0,08
AC_Pset_RenovationAndPhasing - Renovation Status: New

# IfcWall: VS-05D_uued_kihid 370 (4)
In: Esimene korrus
Classification: 1.24 IfcWallType (sein) (RKAS BIM + ARCHICAD Classification)
Pset_WallCommon - Reference: VS-05D; LoadBearing: no; IsExternal: yes
AR_Sein - 001_Nimetus: Välissein; 002_Tähis: VS-05; 325_Helipidavus: 48 dB; 330_Tulekindlus: nõudeid ei esitata; 335_Välispiire: yes; 500_Kandev: no; 505_Paksus: 370 mm; 340_Soojusläbivus: 0,08
AC_Pset_RenovationAndPhasing - Renovation Status: New
Name | 605_Neto_pindala (m2) | 600_Bruto_pindala (m2)
3 x VS-05 | 3.4655 | 5.9305
VS-05 | 2.87931 | 4.91931

# IfcWall: VS-06 600 (2)
In: Esimene korrus
Classification: 1.24 IfcWallType (sein) (RKAS BIM + ARCHICAD Classification)
Pset_WallCommon - Reference: VS-06; LoadBearing: no; IsExternal: yes
AR_Sein - 001_Nimetus: Välissein; 002_Tähis: VS-06; 325_Helipidavus: 48 dB; 330_Tulekindlus: nõudeid ei esitata; 335_Välispiire: yes; 500_Kandev: no; 505_Paksus: 600 mm; 340_Soojusläbivus: 0,10
AC_Pset_RenovationAndPhasing - Renovation Status: New
Name | 605_Neto_pindala (m2) | 600_Bruto_pindala (m2)
VS-06 | 4.21469 | 4.264
VS-06 | 2.02566 | 2.05

# IfcWall: VS-06.1 550 (3)
Classification: 1.24 IfcWallType (sein) (RKAS BIM + ARCHICAD Classification)
Pset_WallCommon - Reference: VS-06.1; LoadBearing: no; IsExternal: yes
AR_Sein - 325_Helipidavus: 48 dB; 330_Tulekindlus: nõudeid ei esitata; 335_Välispiire: yes; 500_Kandev: no; 505_Paksus: 550 mm
AC_Pset_RenovationAndPhasing - Renovation Status: New
Name | In | 001_Nimetus | 002_Tähis | 605_Neto_pindala (m2) | 600_Bruto_pindala (m2) | 340_Soojusläbivus
VS-06.1 | Esimene korrus | Välissein | VS-06.1 | 5.01293 | 5.07 | 0,12
VS-06.1 | Esimene korrus | Välissein | VS-06.1 | 1.7784 | 1.788 | 0,12
VS-06 | Teine korrus |  | VS-06 | 0.86417 | 0.86417 | 0,10

# IfcWall: VS-06.2_sisekiht 170 (2)
In: Esimene korrus
Classification: 1.24 IfcWallType (sein) (RKAS BIM + ARCHICAD Classification)
AR_Sein - 325_Helipidavus: 48 dB; 001_Nimetus: Välissein; 002_Tähis: VS-06.2; 330_Tulekindlus: nõudeid ei esitata; 335_Välispiire: yes; 500_Kandev: yes; 505_Paksus: 170 mm; 340_Soojusläbivus: 0,10
Pset_WallCommon - Reference: VS-06.2; LoadBearing: yes; IsExternal: yes
AC_Pset_RenovationAndPhasing - Renovation Status: New
Name | 605_Neto_pindala (m2) | 600_Bruto_pindala (m2)
VS-06.2 | 4.125 | 10.5
VS-06.2 | 0.525035 | 0.525035

# IfcWall: VS-07 sisekihid 207 (3)
In: Esimene korrus
Classification: 1.24 IfcWallType (sein) (RKAS BIM + ARCHICAD Classification)
Pset_WallCommon - Reference: VS-07 sisekihid; LoadBearing: no; IsExternal: yes
AR_Sein - 325_Helipidavus: 55 dB; 330_Tulekindlus: EI30; 335_Välispiire: no; 500_Kandev: no; 505_Paksus: 207 mm
AC_Pset_RenovationAndPhasing - Renovation Status: New
Name | 001_Nimetus | 002_Tähis | 605_Neto_pindala (m2) | 600_Bruto_pindala (m2) | 340_Soojusläbivus
VS-07 | Välissein | VS-07 | 8.08214 | 8.73249 | 0,07
VS-07 | Välissein | VS-07 | 4.91432 | 6.15848 | 0,07
SS-12 | Sisesein | SS-12 | 1.86309 | 2.51345

# IfcWall: VS-07B_uued_kihid 300, VS-07
In: Esimene korrus
Classification: 1.24 IfcWallType (sein) (RKAS BIM + ARCHICAD Classification)
Pset_WallCommon - Reference: VS-07B; LoadBearing: no; IsExternal: yes
AR_Sein - 001_Nimetus: Välissein; 002_Tähis: VS-07; 325_Helipidavus: 48 dB; 330_Tulekindlus: EI30; 335_Välispiire: yes; 605_Neto_pindala: 11.8178 m2; 600_Bruto_pindala: 13.0448 m2; 500_Kandev: no; 505_Paksus: 300 mm; 340_Soojusläbivus: 0,07
AC_Pset_RenovationAndPhasing - Renovation Status: New

# IfcWall: VS-08.1_uued_kihid 370, VS-08.1
In: Esimene korrus
Classification: 1.24 IfcWallType (sein) (RKAS BIM + ARCHICAD Classification)
Pset_WallCommon - Reference: VS-08.1; LoadBearing: no; IsExternal: yes
AR_Sein - 001_Nimetus: Välissein; 002_Tähis: VS-08.1; 325_Helipidavus: 48 dB; 330_Tulekindlus: nõudeid ei esitata; 335_Välispiire: yes; 605_Neto_pindala: 3.6525 m2; 600_Bruto_pindala: 5.9305 m2; 500_Kandev: no; 505_Paksus: 370 mm; 340_Soojusläbivus: 0,08
AC_Pset_RenovationAndPhasing - Renovation Status: New

# IfcWall: VS-08_uued_kihid 300, VS-08
In: Esimene korrus
Classification: 1.24 IfcWallType (sein) (RKAS BIM + ARCHICAD Classification)
Pset_WallCommon - Reference: VS-08; LoadBearing: no; IsExternal: yes
AR_Sein - 001_Nimetus: Välissein; 002_Tähis: VS-08; 325_Helipidavus: 48 dB; 330_Tulekindlus: EI30; 335_Välispiire: yes; 605_Neto_pindala: 6.42148 m2; 600_Bruto_pindala: 7.03498 m2; 500_Kandev: no; 505_Paksus: 300 mm; 340_Soojusläbivus: 0,09
AC_Pset_RenovationAndPhasing - Renovation Status: New

# IfcWall: WC-tagasein 68 (4)
In: Esimene korrus
Classification: 1.24 IfcWallType (sein) (RKAS BIM + ARCHICAD Classification)
Pset_WallCommon - Reference: WC-tagasein; LoadBearing: no; IsExternal: yes
AR_Sein - 330_Tulekindlus: nõudeid ei esitata; 335_Välispiire: yes; 500_Kandev: no; 505_Paksus: 68 mm
AC_Pset_RenovationAndPhasing - Renovation Status: Existing
Name | 002_Tähis | 325_Helipidavus | 605_Neto_pindala (m2) | 600_Bruto_pindala (m2)
WC_tagasein | WC_tagasein | 24 dB | 1.10511 | 1.23511
WC_tagasein | WC_tagasein | 24 dB | 1.46878 | 1.88478
WC_tagasein | WC_tagasein | 24 dB | 1.10511 | 1.52111
VS-05 | VS-05 | 48 dB | 2.8204 | 3.081 | AR_Sein - 001_Nimetus: Välissein; 340_Soojusläbivus: 0,08

# IfcWallStandardCase: BAUROC CLASSIC 3 MPa kergplokk 300 (2)
In: Esimene korrus
Classification: 1.24 IfcWallType (sein) (RKAS BIM + ARCHICAD Classification); Material: BAUROC CLASSIC 3 MPa kergplokk 300 mm
AR_Sein - 325_Helipidavus: 48 dB; 330_Tulekindlus: nõudeid ei esitata; 335_Välispiire: yes; 500_Kandev: yes; 505_Paksus: 300 mm
Pset_WallCommon - Reference: BAUROC CLASSIC 3 MPa kergplokk; LoadBearing: yes; IsExternal: yes
Name | 002_Tähis | 605_Neto_pindala (m2) | 600_Bruto_pindala (m2) | Renovation Status
VS-08 | VS-08 | 0.432574 | 1.09557 | Existing | AR_Sein - 001_Nimetus: Välissein; 340_Soojusläbivus: 0,09
SS | SS | 0.414721 | 0.414721 | New

# IfcWallStandardCase: ET-02_Raudbetoon - Toode 1, Vundament
In: Vundament
Classification: 1.24 IfcWallType (sein) (RKAS BIM + ARCHICAD Classification); Material: ET-02_Raudbetoon - Toode 1 mm
AR_Sein - 500_Kandev: yes; 002_Tähis: Vundament; 325_Helipidavus: Undefined; 330_Tulekindlus: Undefined; 335_Välispiire: yes; 605_Neto_pindala: 0.000405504 m2; 600_Bruto_pindala: 0.710559 m2; 505_Paksus: 1 mm
Pset_WallCommon - Reference: ET-02; LoadBearing: yes; IsExternal: yes
AC_Pset_RenovationAndPhasing - Renovation Status: New

# IfcWallStandardCase: KON-00_GENEERILINE - KONSTRUKTSIOON 100, Välissein
In: Esimene korrus
Classification: 1.24 IfcWallType (sein) (RKAS BIM + ARCHICAD Classification); Material: KON-00_GENEERILINE - KONSTRUKTSIOON 100 mm
AR_Sein - 500_Kandev: yes; 002_Tähis: Välissein; 325_Helipidavus: 48 dB; 330_Tulekindlus: nõudeid ei esitata; 335_Välispiire: yes; 605_Neto_pindala: 1.05808 m2; 600_Bruto_pindala: 1.2837 m2; 505_Paksus: 100 mm
Pset_WallCommon - Reference: KON-00; LoadBearing: no; IsExternal: no
AC_Pset_RenovationAndPhasing - Renovation Status: Existing

# IfcWallStandardCase: KON-00_GENEERILINE - KONSTRUKTSIOON 150, Sissein
In: Esimene korrus
Classification: 1.24 IfcWallType (sein) (RKAS BIM + ARCHICAD Classification); Material: KON-00_GENEERILINE - KONSTRUKTSIOON 150 mm
AR_Sein - 500_Kandev: yes; 002_Tähis: Sissein; 325_Helipidavus: Undefined; 330_Tulekindlus: nõudeid ei esitata; 335_Välispiire: no; 605_Neto_pindala: 0.3 m2; 600_Bruto_pindala: 0.825 m2; 505_Paksus: 150 mm
Pset_WallCommon - Reference: KON-00; LoadBearing: yes; IsExternal: no
AC_Pset_RenovationAndPhasing - Renovation Status: Existing

# IfcWallStandardCase: KON-00_GENEERILINE - KONSTRUKTSIOON 250, SEIN
In: Esimene korrus
Classification: 1.24 IfcWallType (sein) (RKAS BIM + ARCHICAD Classification); Material: KON-00_GENEERILINE - KONSTRUKTSIOON 250 mm
AR_Sein - 500_Kandev: yes; 002_Tähis: SEIN; 325_Helipidavus: Undefined; 330_Tulekindlus: EI60; 335_Välispiire: yes; 605_Neto_pindala: 8.0147 m2; 600_Bruto_pindala: 14.3314 m2; 505_Paksus: 250 mm
Pset_WallCommon - Reference: KON-00; LoadBearing: yes; IsExternal: yes
AC_Pset_RenovationAndPhasing - Renovation Status: Existing

# IfcWallStandardCase: KON-00_GENEERILINE - KONSTRUKTSIOON 270, VS-01
In: Vundament
Classification: 1.24 IfcWallType (sein) (RKAS BIM + ARCHICAD Classification); Material: KON-00_GENEERILINE - KONSTRUKTSIOON 270 mm
Pset_WallCommon - Reference: KON-00; LoadBearing: yes; IsExternal: yes
AR_Sein - 001_Nimetus: Ol.olev vundament; 002_Tähis: VS-01; 325_Helipidavus: Undefined; 330_Tulekindlus: EI60; 335_Välispiire: yes; 605_Neto_pindala: 2.47221 m2; 600_Bruto_pindala: 3.51621 m2; 500_Kandev: yes; 505_Paksus: 270 mm; 340_Soojusläbivus: 0,16
AC_Pset_RenovationAndPhasing - Renovation Status: Existing

# IfcWallStandardCase: KON-00_GENEERILINE - KONSTRUKTSIOON 30, Välissein
In: Esimene korrus
Classification: 1.24 IfcWallType (sein) (RKAS BIM + ARCHICAD Classification); Material: KON-00_GENEERILINE - KONSTRUKTSIOON 30 mm
AR_Sein - 500_Kandev: yes; 002_Tähis: Välissein; 325_Helipidavus: 48 dB; 330_Tulekindlus: nõudeid ei esitata; 335_Välispiire: yes; 605_Neto_pindala: 0.811 m2; 600_Bruto_pindala: 1.518 m2; 505_Paksus: 30 mm
Pset_WallCommon - Reference: KON-00; LoadBearing: no; IsExternal: no
AC_Pset_RenovationAndPhasing - Renovation Status: Existing

# IfcWallStandardCase: KON-00_GENEERILINE - KONSTRUKTSIOON 320, Vundament
In: Vundament
Classification: 1.24 IfcWallType (sein) (RKAS BIM + ARCHICAD Classification); Material: KON-00_GENEERILINE - KONSTRUKTSIOON 320 mm
AR_Sein - 500_Kandev: yes; 002_Tähis: Vundament; 325_Helipidavus: Undefined; 330_Tulekindlus: Undefined; 335_Välispiire: no; 605_Neto_pindala: 3.70734 m2; 600_Bruto_pindala: 4.16334 m2; 505_Paksus: 320 mm
Pset_WallCommon - Reference: KON-00; LoadBearing: yes; IsExternal: no
AC_Pset_RenovationAndPhasing - Renovation Status: Existing

# IfcWallStandardCase: KON-00_GENEERILINE - KONSTRUKTSIOON 490, VS-01
In: Vundament
Classification: 1.24 IfcWallType (sein) (RKAS BIM + ARCHICAD Classification); Material: KON-00_GENEERILINE - KONSTRUKTSIOON 490 mm
Pset_WallCommon - Reference: KON-00; LoadBearing: yes; IsExternal: yes
AR_Sein - 001_Nimetus: Ol.olev vundament; 002_Tähis: VS-01; 325_Helipidavus: Undefined; 330_Tulekindlus: EI60; 335_Välispiire: yes; 605_Neto_pindala: 3.33534 m2; 600_Bruto_pindala: 3.79134 m2; 500_Kandev: yes; 505_Paksus: 490 mm; 340_Soojusläbivus: 0,16
AC_Pset_RenovationAndPhasing - Renovation Status: Existing

# IfcWallStandardCase: KON-00_GENEERILINE - KONSTRUKTSIOON 60 (2)
In: Esimene korrus
Classification: 1.24 IfcWallType (sein) (RKAS BIM + ARCHICAD Classification); Material: KON-00_GENEERILINE - KONSTRUKTSIOON 60 mm
AR_Sein - 500_Kandev: yes; 330_Tulekindlus: nõudeid ei esitata; 505_Paksus: 60 mm
Pset_WallCommon - Reference: KON-00; LoadBearing: no; IsExternal: no
AC_Pset_RenovationAndPhasing - Renovation Status: Existing
Name | 002_Tähis | 325_Helipidavus | 335_Välispiire | 605_Neto_pindala (m2) | 600_Bruto_pindala (m2)
Sisesein | Sisesein | Undefined | no | 0.9612 | 2.06925
Välissein | Välissein | 48 dB | yes | 0.57 | 2.343

# IfcWallStandardCase: KON-00_GENEERILINE - KONSTRUKTSIOON 80, Vundament
In: Vundament
Classification: 1.24 IfcWallType (sein) (RKAS BIM + ARCHICAD Classification); Material: KON-00_GENEERILINE - KONSTRUKTSIOON 80 mm
AR_Sein - 500_Kandev: yes; 002_Tähis: Vundament; 325_Helipidavus: Undefined; 330_Tulekindlus: Undefined; 335_Välispiire: no; 605_Neto_pindala: 0.468 m2; 600_Bruto_pindala: 0.9 m2; 505_Paksus: 80 mm
Pset_WallCommon - Reference: KON-00; LoadBearing: yes; IsExternal: no
AC_Pset_RenovationAndPhasing - Renovation Status: Existing

# IfcWallStandardCase: KON-00_GENEERILINE - KONSTRUKTSIOON 95 (2)
In: Esimene korrus
Classification: 1.24 IfcWallType (sein) (RKAS BIM + ARCHICAD Classification); Material: KON-00_GENEERILINE - KONSTRUKTSIOON 95 mm
AR_Sein - 500_Kandev: yes; 002_Tähis: Sisesein; 325_Helipidavus: Undefined; 330_Tulekindlus: nõudeid ei esitata; 335_Välispiire: no; 600_Bruto_pindala: 1.21485 m2; 505_Paksus: 95 mm
Pset_WallCommon - Reference: KON-00; LoadBearing: no; IsExternal: no
AC_Pset_RenovationAndPhasing - Renovation Status: Existing
Name | 605_Neto_pindala (m2)
Sisesein | 0.9612
Sisesein | 1.21485

# IfcWallStandardCase: Kipsplaat Knauf GKF vm 13 (2)
In: Esimene korrus
Classification: 1.24 IfcWallType (sein) (RKAS BIM + ARCHICAD Classification); Material: Kipsplaat Knauf GKF vm 13 mm
Pset_WallCommon - Reference: Kipsplaat Knauf GKF vm; LoadBearing: no; IsExternal: yes
AR_Sein - 001_Nimetus: Vundamendi soojustus; 325_Helipidavus: nõudeid ei esitata; 330_Tulekindlus: Undefined; 335_Välispiire: yes; 500_Kandev: no; 505_Paksus: 13 mm; 340_Soojusläbivus: 0,16
AC_Pset_RenovationAndPhasing - Renovation Status: Existing
Name | 002_Tähis | 605_Neto_pindala (m2) | 600_Bruto_pindala (m2)
VS-01.2 | VS-01.2 | 0.43788 | 0.47259
VS-01.1 | VS-01.1 | 0.686415 | 0.686415

# IfcWallStandardCase: Olemasolev raudbetoonplokk 120, Vundament
In: Vundament
Classification: 1.24 IfcWallType (sein) (RKAS BIM + ARCHICAD Classification); Material: Olemasolev raudbetoonplokk 120 mm
AR_Sein - 500_Kandev: yes; 002_Tähis: Vundament; 325_Helipidavus: Undefined; 330_Tulekindlus: Undefined; 335_Välispiire: yes; 605_Neto_pindala: 6.816 m2; 600_Bruto_pindala: 6.816 m2; 505_Paksus: 120 mm
Pset_WallCommon - Reference: Olemasolev raudbetoonplokk; LoadBearing: no; IsExternal: yes
AC_Pset_RenovationAndPhasing - Renovation Status: Existing

# IfcWallStandardCase: Olemasolev raudbetoonplokk 200 (2)
In: Vundament
Classification: 1.24 IfcWallType (sein) (RKAS BIM + ARCHICAD Classification); Material: Olemasolev raudbetoonplokk 200 mm
AR_Sein - 500_Kandev: yes; 002_Tähis: Vundament; 325_Helipidavus: Undefined; 330_Tulekindlus: Undefined; 335_Välispiire: yes; 605_Neto_pindala: 6.77224 m2; 505_Paksus: 200 mm
Pset_WallCommon - Reference: Olemasolev raudbetoonplokk; LoadBearing: yes; IsExternal: yes
AC_Pset_RenovationAndPhasing - Renovation Status: Existing
Name | 600_Bruto_pindala (m2)
Vundament | 7.50026
Vundament | 7.60827

# IfcWallStandardCase: Olemasolev raudbetoonplokk 250 (2)
In: Vundament
Classification: 1.24 IfcWallType (sein) (RKAS BIM + ARCHICAD Classification); Material: Olemasolev raudbetoonplokk 250 mm
AR_Sein - 500_Kandev: yes; 002_Tähis: Vundament; 325_Helipidavus: Undefined; 330_Tulekindlus: Undefined; 335_Välispiire: yes; 505_Paksus: 250 mm
Pset_WallCommon - Reference: Olemasolev raudbetoonplokk; IsExternal: yes
AC_Pset_RenovationAndPhasing - Renovation Status: Existing
Name | 605_Neto_pindala (m2) = 600_Bruto_pindala (m2) | LoadBearing
Vundament | 6.852 | no
Vundament | 6.8041 | yes

# IfcWallStandardCase: Olemasolev raudbetoonplokk 260, Vundament
In: Vundament
Classification: 1.24 IfcWallType (sein) (RKAS BIM + ARCHICAD Classification); Material: Olemasolev raudbetoonplokk 260 mm
AR_Sein - 500_Kandev: yes; 002_Tähis: Vundament; 325_Helipidavus: Undefined; 330_Tulekindlus: Undefined; 335_Välispiire: yes; 605_Neto_pindala: 2.55621 m2; 600_Bruto_pindala: 2.94021 m2; 505_Paksus: 260 mm
Pset_WallCommon - Reference: Olemasolev raudbetoonplokk; LoadBearing: yes; IsExternal: yes
AC_Pset_RenovationAndPhasing - Renovation Status: Existing

# IfcWallStandardCase: Olemasolev raudbetoonplokk 300 (7)
In: Vundament
Classification: 1.24 IfcWallType (sein) (RKAS BIM + ARCHICAD Classification); Material: Olemasolev raudbetoonplokk 300 mm
Pset_WallCommon - Reference: Olemasolev raudbetoonplokk; LoadBearing: yes; IsExternal: yes
AR_Sein - 330_Tulekindlus: Undefined; 335_Välispiire: yes; 500_Kandev: yes; 505_Paksus: 300 mm
AC_Pset_RenovationAndPhasing - Renovation Status: Existing
Name | 002_Tähis | 325_Helipidavus | 605_Neto_pindala (m2) | 600_Bruto_pindala (m2)
VS-01 | VS-01 | nõudeid ei esitata | 3.216 | 4.152 | AR_Sein - 001_Nimetus: Ol.olev vundament; 340_Soojusläbivus: 0,16
2 x Vundament | Vundament | nõudeid ei esitata | 2.8548 | 3.2628
Vundament | Vundament | Undefined | 4.08 | 4.464
Vundament | Vundament | Undefined | 14.4001 | 15.1921
Vundament | Vundament | Undefined | 3.72 | 4.224
Vundament | Vundament | Undefined | 0.629 | 1.32

# IfcWallStandardCase: Olemasolev raudbetoonplokk 320 (9)
In: Vundament
Classification: 1.24 IfcWallType (sein) (RKAS BIM + ARCHICAD Classification); Material: Olemasolev raudbetoonplokk 320 mm
Pset_WallCommon - Reference: Olemasolev raudbetoonplokk; IsExternal: yes
AR_Sein - 335_Välispiire: yes; 505_Paksus: 320 mm
AC_Pset_RenovationAndPhasing - Renovation Status: Existing
Name | LoadBearing = 500_Kandev | 001_Nimetus | 002_Tähis | 325_Helipidavus | 330_Tulekindlus | 605_Neto_pindala (m2) | 600_Bruto_pindala (m2) | 340_Soojusläbivus
VS-01 | yes | Ol.olev vundament | VS-01 | nõudeid ei esitata | Undefined | 14.1687 | 14.5367 | 0,16
VS-01 | yes | Ol.olev vundament | VS-01 | nõudeid ei esitata | Undefined | 7.176 | 7.704 | 0,16
VS-01 | no | Ol.olev vundament | VS-01 | nõudeid ei esitata | Undefined | 7.1281 | 7.5121 | 0,16
VS-01 | yes | Ol.olev vundament | VS-01 | nõudeid ei esitata | Undefined | 10.488 | 10.872 | 0,16
VS-01 | yes | Ol.olev vundament | VS-01 | nõudeid ei esitata | Undefined | 7.12836 | 7.60839 | 0,16
Vundament | yes |  | Vundament | Undefined | Undefined | 2.58 | 2.58
VS-01 | yes | Ol.olev vundament | VS-01 | Undefined | EI60 | 22.068 | 22.068 | 0,16
VS-01 | yes | Ol.olev vundament | VS-01 | Undefined | EI60 | 3.22145 | 3.98947 | 0,16
VS-01 | yes | Ol.olev vundament | VS-01 | Undefined | EI60 | 7.15636 | 7.52438 | 0,16

# IfcWallStandardCase: Olemasolev raudbetoonplokk 340 (7)
In: Vundament
Classification: 1.24 IfcWallType (sein) (RKAS BIM + ARCHICAD Classification); Material: Olemasolev raudbetoonplokk 340 mm
Pset_WallCommon - Reference: Olemasolev raudbetoonplokk; IsExternal: yes
AR_Sein - 330_Tulekindlus: Undefined; 335_Välispiire: yes; 500_Kandev: yes; 505_Paksus: 340 mm
AC_Pset_RenovationAndPhasing - Renovation Status: Existing
Name | LoadBearing | 001_Nimetus | 002_Tähis | 325_Helipidavus | 605_Neto_pindala (m2) | 600_Bruto_pindala (m2) | 340_Soojusläbivus
VS-01 | yes | Ol.olev vundament | VS-01 | nõudeid ei esitata | 15.2881 | 15.6961 | 0,16
VS-01 | yes | Ol.olev vundament | VS-01 | nõudeid ei esitata | 36.84 | 37.296 | 0,16
VS-01 | yes | Ol.olev vundament | VS-01 | nõudeid ei esitata | 32.3407 | 33.2047 | 0,16
VS-01 | yes | Ol.olev vundament | VS-01 | nõudeid ei esitata | 21.54 | 22.02 | 0,16
Vundament | yes |  | Vundament | Undefined | 2.32853 | 3.74334
Vundament | no |  | Vundament | Undefined | 3.78 | 4.236
Vundament | no |  | Vundament | Undefined | 1.29204 | 1.82405

# IfcWallStandardCase: Olemasolev raudbetoonplokk 360, Vundament
In: Vundament
Classification: 1.24 IfcWallType (sein) (RKAS BIM + ARCHICAD Classification); Material: Olemasolev raudbetoonplokk 360 mm
AR_Sein - 500_Kandev: yes; 002_Tähis: Vundament; 325_Helipidavus: Undefined; 330_Tulekindlus: Undefined; 335_Välispiire: yes; 605_Neto_pindala: 4.28379 m2; 600_Bruto_pindala: 4.66779 m2; 505_Paksus: 360 mm
Pset_WallCommon - Reference: Olemasolev raudbetoonplokk; LoadBearing: yes; IsExternal: yes
AC_Pset_RenovationAndPhasing - Renovation Status: Existing

# IfcWallStandardCase: Olemasolev raudbetoonplokk 380 (3)
In: Vundament
Classification: 1.24 IfcWallType (sein) (RKAS BIM + ARCHICAD Classification); Material: Olemasolev raudbetoonplokk 380 mm
Pset_WallCommon - Reference: Olemasolev raudbetoonplokk; IsExternal: yes
AR_Sein - 330_Tulekindlus: Undefined; 335_Välispiire: yes; 505_Paksus: 380 mm
AC_Pset_RenovationAndPhasing - Renovation Status: Existing
Name | LoadBearing = 500_Kandev | 001_Nimetus | 002_Tähis | 325_Helipidavus | 605_Neto_pindala (m2) = 600_Bruto_pindala (m2) | 340_Soojusläbivus
VS-01 | yes | Ol.olev vundament | VS-01 | nõudeid ei esitata | 7.55979 | 0,16
VS-01 | no | Ol.olev vundament | VS-01 | nõudeid ei esitata | 8.064 | 0,16
Vundament | yes |  | Vundament | Undefined | 4.164

# IfcWallStandardCase: Olemasolev raudbetoonplokk 390, Vundament
In: Vundament
Classification: 1.24 IfcWallType (sein) (RKAS BIM + ARCHICAD Classification); Material: Olemasolev raudbetoonplokk 390 mm
AR_Sein - 500_Kandev: yes; 002_Tähis: Vundament; 325_Helipidavus: Undefined; 330_Tulekindlus: Undefined; 335_Välispiire: yes; 605_Neto_pindala: 7.07528 m2; 600_Bruto_pindala: 7.4593 m2; 505_Paksus: 390 mm
Pset_WallCommon - Reference: Olemasolev raudbetoonplokk; LoadBearing: yes; IsExternal: yes
AC_Pset_RenovationAndPhasing - Renovation Status: Existing

# IfcWallStandardCase: Olemasolev raudbetoonplokk 400 (4)
In: Vundament
Classification: 1.24 IfcWallType (sein) (RKAS BIM + ARCHICAD Classification); Material: Olemasolev raudbetoonplokk 400 mm
Pset_WallCommon - Reference: Olemasolev raudbetoonplokk; LoadBearing: yes; IsExternal: yes
AR_Sein - 330_Tulekindlus: Undefined; 335_Välispiire: yes; 500_Kandev: yes; 505_Paksus: 400 mm
AC_Pset_RenovationAndPhasing - Renovation Status: Existing
Name | 002_Tähis | 325_Helipidavus | 605_Neto_pindala (m2) | 600_Bruto_pindala (m2)
VS-01 | VS-01 | nõudeid ei esitata | 4.008 | 4.008 | AR_Sein - 001_Nimetus: Ol.olev vundament; 340_Soojusläbivus: 0,16
Vundament | Vundament | Undefined | 10.4762 | 11.5682
Vundament | Vundament | Undefined | 7.32 | 7.824
Vundament | Vundament | Undefined | 10.32 | 10.728

# IfcWallStandardCase: Olemasolev raudbetoonplokk 440 (4)
In: Vundament
Classification: 1.24 IfcWallType (sein) (RKAS BIM + ARCHICAD Classification); Material: Olemasolev raudbetoonplokk 440 mm
Pset_WallCommon - Reference: Olemasolev raudbetoonplokk; LoadBearing: yes; IsExternal: yes
AR_Sein - 001_Nimetus: Ol.olev vundament; 002_Tähis: VS-01; 325_Helipidavus: nõudeid ei esitata; 330_Tulekindlus: Undefined; 335_Välispiire: yes; 500_Kandev: yes; 505_Paksus: 440 mm; 340_Soojusläbivus: 0,16
AC_Pset_RenovationAndPhasing - Renovation Status: Existing
Name | 605_Neto_pindala (m2) | 600_Bruto_pindala (m2)
VS-01 | 2.7075 | 3.6
VS-01 | 3.74379 | 4.27179
VS-01 | 3.58869 | 3.984
VS-01 | 7.4391 | 7.60195

# IfcWallStandardCase: Olemasolev raudbetoonplokk 450, Vundament
In: Vundament
Classification: 1.24 IfcWallType (sein) (RKAS BIM + ARCHICAD Classification); Material: Olemasolev raudbetoonplokk 450 mm
AR_Sein - 500_Kandev: yes; 002_Tähis: Vundament; 325_Helipidavus: Undefined; 330_Tulekindlus: Undefined; 335_Välispiire: yes; 605_Neto_pindala: 1.284 m2; 600_Bruto_pindala: 1.284 m2; 505_Paksus: 450 mm
Pset_WallCommon - Reference: Olemasolev raudbetoonplokk; LoadBearing: yes; IsExternal: yes
AC_Pset_RenovationAndPhasing - Renovation Status: Existing

# IfcWallStandardCase: Olemasolev raudbetoonplokk 480, Vundament
In: Vundament
Classification: 1.24 IfcWallType (sein) (RKAS BIM + ARCHICAD Classification); Material: Olemasolev raudbetoonplokk 480 mm
AR_Sein - 500_Kandev: yes; 002_Tähis: Vundament; 325_Helipidavus: Undefined; 330_Tulekindlus: Undefined; 335_Välispiire: yes; 605_Neto_pindala: 4.22278 m2; 600_Bruto_pindala: 4.22278 m2; 505_Paksus: 480 mm
Pset_WallCommon - Reference: Olemasolev raudbetoonplokk; LoadBearing: yes; IsExternal: yes
AC_Pset_RenovationAndPhasing - Renovation Status: Existing

# IfcWallStandardCase: Olemasolev silikaattellis 250 (3)
Classification: 1.24 IfcWallType (sein) (RKAS BIM + ARCHICAD Classification); Material: Olemasolev silikaattellis 250 mm
AR_Sein - 500_Kandev: yes; 001_Nimetus: Ol.olev sisesein; 325_Helipidavus: 55 dB; 335_Välispiire: no; 505_Paksus: 250 mm
Pset_WallCommon - Reference: Olemasolev silikaattellis; LoadBearing: yes; IsExternal: no
AC_Pset_RenovationAndPhasing - Renovation Status: Existing
Name | In | 002_Tähis | 330_Tulekindlus | 605_Neto_pindala (m2) | 600_Bruto_pindala (m2)
SS-01 | Esimene korrus | SS-01 | nõudeid ei esitata | 15.1391 | 15.1391
SS-01 | Esimene korrus | SS-01 | nõudeid ei esitata | 13.2507 | 16.8959
SS-07 | Teine korrus | SS-07 | EI30 | 4.437 | 9.5259

# IfcWallStandardCase: Olemasolev silikaattellis 260, SS-12
In: Esimene korrus
Classification: 1.24 IfcWallType (sein) (RKAS BIM + ARCHICAD Classification); Material: Olemasolev silikaattellis 260 mm
AR_Sein - 500_Kandev: yes; 335_Välispiire: no; 002_Tähis: SS-12; 325_Helipidavus: 48 dB; 330_Tulekindlus: EI30; 605_Neto_pindala: 7.28573 m2; 600_Bruto_pindala: 8.38156 m2; 505_Paksus: 260 mm
Pset_WallCommon - Reference: Olemasolev silikaattellis; LoadBearing: yes; IsExternal: no
AC_Pset_RenovationAndPhasing - Renovation Status: Existing

# IfcWallStandardCase: Olemasolev silikaattellis 270, SS-06
In: Teine korrus
Classification: 1.24 IfcWallType (sein) (RKAS BIM + ARCHICAD Classification); Material: Olemasolev silikaattellis 270 mm
AR_Sein - 335_Välispiire: no; 500_Kandev: yes; 001_Nimetus: Ol.olev sisesein; 002_Tähis: SS-06; 325_Helipidavus: 64 dB; 330_Tulekindlus: nõudeid ei esitata; 605_Neto_pindala: 11.0812 m2; 600_Bruto_pindala: 11.3622 m2; 505_Paksus: 270 mm
Pset_WallCommon - Reference: Olemasolev silikaattellis; LoadBearing: yes; IsExternal: no
AC_Pset_RenovationAndPhasing - Renovation Status: Existing

# IfcWallStandardCase: Olemasolev silikaattellis 280, SS-07
In: Teine korrus
Classification: 1.24 IfcWallType (sein) (RKAS BIM + ARCHICAD Classification); Material: Olemasolev silikaattellis 280 mm
AR_Sein - 335_Välispiire: no; 500_Kandev: yes; 001_Nimetus: Ol.olev sisesein; 002_Tähis: SS-07; 325_Helipidavus: 55 dB; 330_Tulekindlus: nõudeid ei esitata; 605_Neto_pindala: 7.72823 m2; 600_Bruto_pindala: 7.72823 m2; 505_Paksus: 280 mm
Pset_WallCommon - Reference: Olemasolev silikaattellis; LoadBearing: yes; IsExternal: no
AC_Pset_RenovationAndPhasing - Renovation Status: Existing

# IfcWallStandardCase: Olemasolev silikaattellis 340 (2)
In: Esimene korrus
Classification: 1.24 IfcWallType (sein) (RKAS BIM + ARCHICAD Classification); Material: Olemasolev silikaattellis 340 mm
AR_Sein - 500_Kandev: yes; 001_Nimetus: Ol.olev sisesein; 002_Tähis: SS-01; 325_Helipidavus: 55 dB; 335_Välispiire: no; 505_Paksus: 340 mm
Pset_WallCommon - Reference: Olemasolev silikaattellis; LoadBearing: yes; IsExternal: no
AC_Pset_RenovationAndPhasing - Renovation Status: Existing
Name | 330_Tulekindlus | 605_Neto_pindala (m2) | 600_Bruto_pindala (m2)
SS-01 | EI30 | 8.85 | 10.031
SS-01 | nõudeid ei esitata | 4.05852 | 4.05852

# IfcWallStandardCase: Olemasolev silikaattellis 400, SS-07.1
In: Teine korrus
Classification: 1.24 IfcWallType (sein) (RKAS BIM + ARCHICAD Classification); Material: Olemasolev silikaattellis 400 mm
AR_Sein - 335_Välispiire: no; 500_Kandev: yes; 002_Tähis: SS-07.1; 325_Helipidavus: 55 dB; 330_Tulekindlus: nõudeid ei esitata; 605_Neto_pindala: 7.6427 m2; 600_Bruto_pindala: 8.2047 m2; 505_Paksus: 400 mm
Pset_WallCommon - Reference: Olemasolev silikaattellis; LoadBearing: yes; IsExternal: no
AC_Pset_RenovationAndPhasing - Renovation Status: Existing

# IfcWallStandardCase: Olemasolev silikaattellis 450, SS-12
In: Esimene korrus
Classification: 1.24 IfcWallType (sein) (RKAS BIM + ARCHICAD Classification); Material: Olemasolev silikaattellis 450 mm
AR_Sein - 500_Kandev: yes; 335_Välispiire: no; 002_Tähis: SS-12; 325_Helipidavus: 48 dB; 330_Tulekindlus: EI30; 605_Neto_pindala: 2.73899 m2; 600_Bruto_pindala: 3.6626 m2; 505_Paksus: 450 mm
Pset_WallCommon - Reference: Olemasolev silikaattellis; LoadBearing: yes; IsExternal: no
AC_Pset_RenovationAndPhasing - Renovation Status: Existing

# IfcWallStandardCase: Olemasolev silikaltsiitpaneel 100 (3)
In: Teine korrus
Classification: 1.24 IfcWallType (sein) (RKAS BIM + ARCHICAD Classification); Material: Olemasolev silikaltsiitpaneel 100 mm
AR_Sein - 500_Kandev: no; 335_Välispiire: no; 001_Nimetus: Ol.olev seisesein; 002_Tähis: SS-05; 325_Helipidavus: 64 dB; 505_Paksus: 100 mm
Pset_WallCommon - Reference: Olemasolev silikaltsiitpaneel; LoadBearing: no; IsExternal: no
AC_Pset_RenovationAndPhasing - Renovation Status: Existing
Name | 330_Tulekindlus | 605_Neto_pindala (m2) | 600_Bruto_pindala (m2)
SS-05 | nõudeid ei esitata | 11.1198 | 11.4008
SS-05 | nõudeid ei esitata | 10.9993 | 11.2763
SS-05 | EI30 | 15.9329 | 15.9329

# IfcWallStandardCase: Olemasolev silikaltsiitpaneel 120, SS-05
In: Esimene korrus
Classification: 1.24 IfcWallType (sein) (RKAS BIM + ARCHICAD Classification); Material: Olemasolev silikaltsiitpaneel 120 mm
AR_Sein - 500_Kandev: no; 335_Välispiire: no; 001_Nimetus: Ol.olev sisesein; 002_Tähis: SS-05; 325_Helipidavus: nõudeid ei esitata; 330_Tulekindlus: EI30; 605_Neto_pindala: 16.728 m2; 600_Bruto_pindala: 16.756 m2; 505_Paksus: 120 mm
Pset_WallCommon - Reference: Olemasolev silikaltsiitpaneel; LoadBearing: yes; IsExternal: no
AC_Pset_RenovationAndPhasing - Renovation Status: Existing

# IfcWallStandardCase: Olemasolev silikaltsiitpaneel 220, SS-05
In: Teine korrus
Classification: 1.24 IfcWallType (sein) (RKAS BIM + ARCHICAD Classification); Material: Olemasolev silikaltsiitpaneel 220 mm
AR_Sein - 500_Kandev: no; 335_Välispiire: no; 001_Nimetus: Ol.olev seisesein; 002_Tähis: SS-05; 325_Helipidavus: 64 dB; 330_Tulekindlus: nõudeid ei esitata; 605_Neto_pindala: 8.00863 m2; 600_Bruto_pindala: 8.00863 m2; 505_Paksus: 220 mm
Pset_WallCommon - Reference: Olemasolev silikaltsiitpaneel; LoadBearing: no; IsExternal: no
AC_Pset_RenovationAndPhasing - Renovation Status: Existing

# IfcWallStandardCase: Olemasolev silikaltsiitpaneel 300, SS-08.1
In: Teine korrus
Classification: 1.24 IfcWallType (sein) (RKAS BIM + ARCHICAD Classification); Material: Olemasolev silikaltsiitpaneel 300 mm
AR_Sein - 500_Kandev: no; 335_Välispiire: no; 002_Tähis: SS-08.1; 325_Helipidavus: 64 dB; 330_Tulekindlus: nõudeid ei esitata; 605_Neto_pindala: 5.91551 m2; 600_Bruto_pindala: 8.76757 m2; 505_Paksus: 300 mm
Pset_WallCommon - Reference: Olemasolev silikaltsiitpaneel; LoadBearing: no; IsExternal: no
AC_Pset_RenovationAndPhasing - Renovation Status: Existing

# IfcWallStandardCase: Olemasolev silikaltsiitplokk 200 (7)
Classification: 1.24 IfcWallType (sein) (RKAS BIM + ARCHICAD Classification); Material: Olemasolev silikaltsiitplokk 200 mm
AR_Sein - 325_Helipidavus: 48 dB; 505_Paksus: 200 mm
Pset_WallCommon - Reference: Olemasolev silikaltsiitplokk; LoadBearing: no; IsExternal: no
AC_Pset_RenovationAndPhasing - Renovation Status: Existing
Name | In | 500_Kandev | 002_Tähis | 330_Tulekindlus | 335_Välispiire | 605_Neto_pindala (m2) | 600_Bruto_pindala (m2) | 001_Nimetus
Välissein | Esimene korrus | yes | Välissein | nõudeid ei esitata | yes | 9.1028 | 9.768
SS-03 | Esimene korrus | yes | SS-03 | EI30 | no | 8.59475 | 9.61502 | Ol.olev sisesein
SS-03 | Esimene korrus | yes | SS-03 | nõudeid ei esitata | no | 16.5222 | 21.5619 | Ol.olev sisesein
SS-03 | Esimene korrus | yes | SS-03 | nõudeid ei esitata | no | 6.63525 | 11.9396 | Ol.olev sisesein
SS-02 | Teine korrus | no | SS-02 | nõudeid ei esitata | no | 11.8435 | 11.9423 | Ol.olev sisesein
SS-08 | Teine korrus | no | SS-08 | nõudeid ei esitata | no | 8.90326 | 9.57866 | Ol.olev sisesein
SS-02 | Teine korrus | no | SS-02 | nõudeid ei esitata | no | 6.85086 | 9.88486 | Ol.olev sisesein

# IfcWallStandardCase: Olemasolev silikaltsiitplokk 220 (5)
Classification: 1.24 IfcWallType (sein) (RKAS BIM + ARCHICAD Classification); Material: Olemasolev silikaltsiitplokk 220 mm
Pset_WallCommon - Reference: Olemasolev silikaltsiitplokk
AR_Sein - 505_Paksus: 220 mm
AC_Pset_RenovationAndPhasing - Renovation Status: Existing
Name | In | LoadBearing = IsExternal = 335_Välispiire = 500_Kandev | 001_Nimetus | 002_Tähis | 325_Helipidavus | 330_Tulekindlus | 605_Neto_pindala (m2) | 600_Bruto_pindala (m2) | 340_Soojusläbivus
2 x VS-05 | Esimene korrus | yes | Ol.olev välissein | VS-05 | Undefined | EI60 | 3.0885 | 5.9305 | 0,08
VS-05 | Esimene korrus | yes | Ol.olev välissein | VS-05 | Undefined | EI60 | 1.45 | 3.915 | 0,08
VS-05 | Esimene korrus | yes | Ol.olev välissein | VS-05 | Undefined | EI60 | 2.83103 | 5.9714 | 0,08
SS-08 | Teine korrus | no | Ol.olev sisesein | SS-08 | 48 dB | nõudeid ei esitata | 9.00669 | 9.01344

# IfcWallStandardCase: Olemasolev silikaltsiitplokk 240, SS-03
In: Teine korrus
Classification: 1.24 IfcWallType (sein) (RKAS BIM + ARCHICAD Classification); Material: Olemasolev silikaltsiitplokk 240 mm
AR_Sein - 500_Kandev: yes; 335_Välispiire: no; 001_Nimetus: Ol.olev sisesein; 002_Tähis: SS-03; 325_Helipidavus: 48 dB; 330_Tulekindlus: EI30; 605_Neto_pindala: 15.9329 m2; 600_Bruto_pindala: 15.9329 m2; 505_Paksus: 240 mm
Pset_WallCommon - Reference: Olemasolev silikaltsiitplokk; LoadBearing: yes; IsExternal: no
AC_Pset_RenovationAndPhasing - Renovation Status: Existing

# IfcWallStandardCase: Olemasolev silikaltsiitplokk 270, VS-03
In: Esimene korrus
Classification: 1.24 IfcWallType (sein) (RKAS BIM + ARCHICAD Classification); Material: Olemasolev silikaltsiitplokk 270 mm
Pset_WallCommon - Reference: Olemasolev silikaltsiitplokk; LoadBearing: yes; IsExternal: yes
AR_Sein - 001_Nimetus: Ol.olev välissein; 002_Tähis: VS-03; 325_Helipidavus: 48 dB; 330_Tulekindlus: nõudeid ei esitata; 335_Välispiire: yes; 605_Neto_pindala: 5.6761 m2; 600_Bruto_pindala: 10.4302 m2; 500_Kandev: yes; 505_Paksus: 270 mm; 340_Soojusläbivus: 0,10
AC_Pset_RenovationAndPhasing - Renovation Status: Existing

# IfcWallStandardCase: Olemasolev silikaltsiitplokk 300 (5)
In: Esimene korrus
Classification: 1.24 IfcWallType (sein) (RKAS BIM + ARCHICAD Classification); Material: Olemasolev silikaltsiitplokk 300 mm
AR_Sein - 500_Kandev: yes; 505_Paksus: 300 mm
Pset_WallCommon - Reference: Olemasolev silikaltsiitplokk; LoadBearing: yes
AC_Pset_RenovationAndPhasing - Renovation Status: Existing
Name | 001_Nimetus | 002_Tähis | 325_Helipidavus | 330_Tulekindlus | 335_Välispiire = IsExternal | 605_Neto_pindala (m2) | 600_Bruto_pindala (m2)
SS-02 | Ol.olev sisesein | SS-02 | 55 dB | EI30 | no | 11.6702 | 11.7991
SS-02 | Ol.olev sisesein | SS-02 | 55 dB | nõudeid ei esitata | no | 41.1877 | 42.3548
SS-02 | Ol.olev sisesein | SS-02 | 55 dB | nõudeid ei esitata | no | 8.87626 | 8.87626
SS-02 | Ol.olev sisesein | SS-02 | 55 dB | EI30 | no | 1.66624 | 2.7545
VS-03 | Ol.olev välissein | VS-03 | 48 dB | EI30 | yes | 11.0952 | 14.3074 | AR_Sein - 340_Soojusläbivus: 0,10

# IfcWallStandardCase: Olemasolev silikaltsiitplokk 320 (10)
In: Esimene korrus
Classification: 1.24 IfcWallType (sein) (RKAS BIM + ARCHICAD Classification); Material: Olemasolev silikaltsiitplokk 320 mm
Pset_WallCommon - Reference: Olemasolev silikaltsiitplokk; LoadBearing: yes
AR_Sein - 500_Kandev: yes; 505_Paksus: 320 mm
AC_Pset_RenovationAndPhasing - Renovation Status: Existing
Name | IsExternal = 335_Välispiire | 001_Nimetus | 002_Tähis | 325_Helipidavus | 330_Tulekindlus | 605_Neto_pindala (m2) | 600_Bruto_pindala (m2) | 340_Soojusläbivus
VS-03 | yes | Ol.olev välissein | VS-03 | 48 dB | nõudeid ei esitata | 21.1867 | 25.6456 | 0,10
VS-03 | yes | Ol.olev välissein | VS-03 | 48 dB | nõudeid ei esitata | 16.4469 | 25.9319 | 0,10
VS-03 | yes | Ol.olev välissein | VS-03 | 48 dB | nõudeid ei esitata | 12.2886 | 12.2886 | 0,10
VS-03 | yes | Ol.olev välissein | VS-03 | 48 dB | nõudeid ei esitata | 50.1715 | 75.2151 | 0,10
VS-05 | yes | Ol.olev välissein | VS-05 | Undefined | EI60 | 2.7985 | 5.9305 | 0,08
VS-03 | yes | Ol.olev välissein | VS-03 | 48 dB | nõudeid ei esitata | 16.5456 | 26.2578 | 0,10
SS-02 | no | Ol.olev sisesein | SS-02 | 48 dB | EI30 | 6.83518 | 11.4492
SS-02 | no | Ol.olev sisesein | SS-02 | 55 dB | EI30 | 5.40039 | 7.33539
VS-03 | yes | Ol.olev välissein | VS-03 | 48 dB | EI30 | 35.9664 | 37.0554 | 0,10
VS-03 | yes | Ol.olev välissein | VS-03 | 48 dB | EI60 | 30.7978 | 52.3323 | 0,10

# IfcWallStandardCase: Olemasolev silikaltsiitplokk 330 (3)
Classification: 1.24 IfcWallType (sein) (RKAS BIM + ARCHICAD Classification); Material: Olemasolev silikaltsiitplokk 330 mm
Pset_WallCommon - Reference: Olemasolev silikaltsiitplokk; LoadBearing: no; IsExternal: yes
AR_Sein - 001_Nimetus: Ol.olev välissein; 002_Tähis: VS-03; 330_Tulekindlus: nõudeid ei esitata; 335_Välispiire: yes; 500_Kandev: no; 505_Paksus: 330 mm; 340_Soojusläbivus: 0,10
AC_Pset_RenovationAndPhasing - Renovation Status: Existing
Name | In | 325_Helipidavus | 605_Neto_pindala (m2) | 600_Bruto_pindala (m2)
VS-03 | Esimene korrus | 48 dB | 17.8583 | 20.6583
VS-03 | Teine korrus | nõudeid ei esitata | 17.0733 | 17.0733
VS-03 | Teine korrus | 48 dB | 13.8473 | 13.8473

# IfcWallStandardCase: Olemasolev silikaltsiitplokk 340 (2)
In: Esimene korrus
Classification: 1.24 IfcWallType (sein) (RKAS BIM + ARCHICAD Classification); Material: Olemasolev silikaltsiitplokk 340 mm
Pset_WallCommon - Reference: Olemasolev silikaltsiitplokk; LoadBearing: yes
AR_Sein - 325_Helipidavus: Undefined; 500_Kandev: yes; 505_Paksus: 340 mm
AC_Pset_RenovationAndPhasing - Renovation Status: Existing
Name | IsExternal = 335_Välispiire | 002_Tähis | 330_Tulekindlus | 605_Neto_pindala (m2) | 600_Bruto_pindala (m2)
VS-05 | yes | VS-05 | EI60 | 3.1409 | 5.9595 | AR_Sein - 001_Nimetus: Ol.olev välissein; 340_Soojusläbivus: 0,08
SS-12 | no | SS-12 | nõudeid ei esitata | 8.82065 | 10.6659

# IfcWallStandardCase: Olemasolev silikaltsiitplokk 350 (4)
Classification: 1.24 IfcWallType (sein) (RKAS BIM + ARCHICAD Classification); Material: Olemasolev silikaltsiitplokk 350 mm
Pset_WallCommon - Reference: Olemasolev silikaltsiitplokk; LoadBearing: yes; IsExternal: yes
AR_Sein - 001_Nimetus: Ol.olev välissein; 002_Tähis: VS-03; 325_Helipidavus: 48 dB; 330_Tulekindlus: nõudeid ei esitata; 335_Välispiire: yes; 500_Kandev: yes; 505_Paksus: 350 mm; 340_Soojusläbivus: 0,10
AC_Pset_RenovationAndPhasing - Renovation Status: Existing
Name | In | 605_Neto_pindala (m2) | 600_Bruto_pindala (m2)
VS-03 | Esimene korrus | 43.0323 | 43.0323
VS-03 | Teine korrus | 17.0534 | 17.0733
VS-03 | Teine korrus | 1.9992 | 1.9992
VS-03 | Teine korrus | 20.9721 | 24.5841

# IfcWallStandardCase: Olemasolev silikaltsiitplokk 360, SS-02
In: Esimene korrus
Classification: 1.24 IfcWallType (sein) (RKAS BIM + ARCHICAD Classification); Material: Olemasolev silikaltsiitplokk 360 mm
AR_Sein - 002_Tähis: SS-02; 325_Helipidavus: 55 dB; 330_Tulekindlus: EI30; 335_Välispiire: no; 605_Neto_pindala: 12.238 m2; 600_Bruto_pindala: 13.335 m2; 500_Kandev: yes; 505_Paksus: 360 mm
Pset_WallCommon - Reference: Olemasolev silikaltsiitplokk; LoadBearing: yes; IsExternal: no
AC_Pset_RenovationAndPhasing - Renovation Status: Existing

# IfcWallStandardCase: Olemasolev silikaltsiitplokk 380 (5)
In: Esimene korrus
Classification: 1.24 IfcWallType (sein) (RKAS BIM + ARCHICAD Classification); Material: Olemasolev silikaltsiitplokk 380 mm
Pset_WallCommon - Reference: Olemasolev silikaltsiitplokk; LoadBearing: yes
AR_Sein - 330_Tulekindlus: EI30; 500_Kandev: yes; 505_Paksus: 380 mm
AC_Pset_RenovationAndPhasing - Renovation Status: Existing
Name | IsExternal = 335_Välispiire | 001_Nimetus | 002_Tähis | 325_Helipidavus | 605_Neto_pindala (m2) | 600_Bruto_pindala (m2)
VS-07 | yes | Ol.olev välissein | VS-07 | 48 dB | 8.0164 | 10.0205 | AR_Sein - 340_Soojusläbivus: 0,07
SS-02 | no | Ol.olev sisesein | SS-02 | 55 dB | 1.07254 | 2.90004
VS-03 | yes | Ol.olev välissein | VS-03 | 48 dB | 15.7458 | 15.7458 | AR_Sein - 340_Soojusläbivus: 0,10
SS-02 | no | Ol.olev sisesein | SS-02 | 55 dB | 2.33709 | 3.97476
SS-02 | no | Ol.olev sisesein | SS-02 | 55 dB | 3.46298 | 4.96417

# IfcWallStandardCase: Olemasolev silikaltsiitplokk 390 (3)
Classification: 1.24 IfcWallType (sein) (RKAS BIM + ARCHICAD Classification); Material: Olemasolev silikaltsiitplokk 390 mm
AR_Sein - 330_Tulekindlus: nõudeid ei esitata; 505_Paksus: 390 mm
Pset_WallCommon - Reference: Olemasolev silikaltsiitplokk
AC_Pset_RenovationAndPhasing - Renovation Status: Existing
Name | In | 500_Kandev = LoadBearing | 001_Nimetus | 002_Tähis | 325_Helipidavus | 335_Välispiire = IsExternal | 605_Neto_pindala (m2) | 600_Bruto_pindala (m2) | 340_Soojusläbivus
SS-02 | Esimene korrus | yes | Ol.olev sisesein | SS-02 | 55 dB | no | 17.4264 | 21.1397
VS-03 | Esimene korrus | no | Ol.olev välissein | VS-03 | 48 dB | yes | 20.3796 | 22.11 | 0,10
VS-03 | Teine korrus | no | Ol.olev välissein | VS-03 | 48 dB | yes | 19.0606 | 24.7812 | 0,10

# IfcWallStandardCase: Olemasolev silikaltsiitplokk 400 (4)
In: Esimene korrus
Classification: 1.24 IfcWallType (sein) (RKAS BIM + ARCHICAD Classification); Material: Olemasolev silikaltsiitplokk 400 mm
AR_Sein - 500_Kandev: yes; 505_Paksus: 400 mm
Pset_WallCommon - Reference: Olemasolev silikaltsiitplokk; LoadBearing: yes
AC_Pset_RenovationAndPhasing - Renovation Status: Existing
Name | 001_Nimetus | 002_Tähis | 325_Helipidavus | 330_Tulekindlus | 335_Välispiire = IsExternal | 605_Neto_pindala (m2) | 600_Bruto_pindala (m2)
SS-02 | Ol.olev sisesein | SS-02 | 55 dB | EI30 | no | 30.6475 | 33.6114
SS-02 | Ol.olev sisesein | SS-02 | 55 dB | EI30 | no | 21.0499 | 22.4993
SS-02 | Ol.olev sisesein | SS-02 | 55 dB | EI30 | no | 29.2758 | 29.6202
VS-03 | Ol.olev välissein | VS-03 | 48 dB | nõudeid ei esitata | yes | 6.78633 | 13.6606 | AR_Sein - 340_Soojusläbivus: 0,10

# IfcWallStandardCase: Olemasolev silikaltsiitplokk 440 (5)
In: Esimene korrus
Classification: 1.24 IfcWallType (sein) (RKAS BIM + ARCHICAD Classification); Material: Olemasolev silikaltsiitplokk 440 mm
Pset_WallCommon - Reference: Olemasolev silikaltsiitplokk; LoadBearing: yes; IsExternal: yes
AR_Sein - 001_Nimetus: Ol.olev välissein; 002_Tähis: VS-03; 325_Helipidavus: 48 dB; 335_Välispiire: yes; 500_Kandev: yes; 505_Paksus: 440 mm; 340_Soojusläbivus: 0,10
AC_Pset_RenovationAndPhasing - Renovation Status: Existing
Name | 330_Tulekindlus | 605_Neto_pindala (m2) | 600_Bruto_pindala (m2)
VS-03 | nõudeid ei esitata | 16.1139 | 16.1139
VS-03 | nõudeid ei esitata | 18.988 | 28.0228
VS-03 | EI30 | 10.5177 | 13.5788
VS-03 | nõudeid ei esitata | 16.7749 | 24.6238
VS-03 | EI30 | 11.7923 | 13.5788

# IfcWallStandardCase: Olemasolev silikaltsiitplokk 480, SS-03
In: Esimene korrus
Classification: 1.24 IfcWallType (sein) (RKAS BIM + ARCHICAD Classification); Material: Olemasolev silikaltsiitplokk 480 mm
AR_Sein - 500_Kandev: yes; 001_Nimetus: Ol.olev sisesein; 002_Tähis: SS-03; 325_Helipidavus: 48 dB; 330_Tulekindlus: EI30; 335_Välispiire: no; 605_Neto_pindala: 12.0202 m2; 600_Bruto_pindala: 13.5314 m2; 505_Paksus: 480 mm
Pset_WallCommon - Reference: Olemasolev silikaltsiitplokk; LoadBearing: no; IsExternal: no
AC_Pset_RenovationAndPhasing - Renovation Status: Existing

# IfcWallStandardCase: Olemasolev silikaltsiitplokk 490, VS-07
In: Esimene korrus
Classification: 1.24 IfcWallType (sein) (RKAS BIM + ARCHICAD Classification); Material: Olemasolev silikaltsiitplokk 490 mm
Pset_WallCommon - Reference: Olemasolev silikaltsiitplokk; LoadBearing: yes; IsExternal: yes
AR_Sein - 001_Nimetus: Ol.olev välissein; 002_Tähis: VS-07; 325_Helipidavus: 48 dB; 330_Tulekindlus: EI30; 335_Välispiire: yes; 605_Neto_pindala: 12.9221 m2; 600_Bruto_pindala: 12.9221 m2; 500_Kandev: yes; 505_Paksus: 490 mm; 340_Soojusläbivus: 0,07
AC_Pset_RenovationAndPhasing - Renovation Status: Existing

# IfcWallStandardCase: Olemasolev silikaltsiitplokk 510, VS-03
In: Teine korrus
Classification: 1.24 IfcWallType (sein) (RKAS BIM + ARCHICAD Classification); Material: Olemasolev silikaltsiitplokk 510 mm
Pset_WallCommon - Reference: Olemasolev silikaltsiitplokk; LoadBearing: yes; IsExternal: yes
AR_Sein - 001_Nimetus: Ol.olev välissein; 002_Tähis: VS-03; 325_Helipidavus: 48 dB; 330_Tulekindlus: nõudeid ei esitata; 335_Välispiire: yes; 605_Neto_pindala: 10.5439 m2; 600_Bruto_pindala: 12.0475 m2; 500_Kandev: yes; 505_Paksus: 510 mm; 340_Soojusläbivus: 0,10
AC_Pset_RenovationAndPhasing - Renovation Status: Existing

# IfcWallStandardCase: Olemasolev silikaltsiitplokk 80, Sissein
In: Esimene korrus
Classification: 1.24 IfcWallType (sein) (RKAS BIM + ARCHICAD Classification); Material: Olemasolev silikaltsiitplokk 80 mm
AR_Sein - 500_Kandev: yes; 002_Tähis: Sissein; 325_Helipidavus: 48 dB; 330_Tulekindlus: EI30; 335_Välispiire: no; 605_Neto_pindala: 1.32885 m2; 600_Bruto_pindala: 2.94729 m2; 505_Paksus: 80 mm
Pset_WallCommon - Reference: Olemasolev silikaltsiitplokk; LoadBearing: yes; IsExternal: no
AC_Pset_RenovationAndPhasing - Renovation Status: Existing

# IfcWallStandardCase: Puit - Konstruktsioon 100, SM-3
In: Esimene korrus
Classification: 1.24 IfcWallType (sein) (RKAS BIM + ARCHICAD Classification); Material: Puit - Konstruktsioon 100 mm
Pset_WallCommon - Reference: Puit - Konstruktsioon; LoadBearing: no; IsExternal: yes
AR_Sein - 002_Tähis: SM-3; 325_Helipidavus: 24 dB; 330_Tulekindlus: nõudeid ei esitata; 335_Välispiire: yes; 605_Neto_pindala: 3.1602 m2; 600_Bruto_pindala: 3.1882 m2; 500_Kandev: no; 505_Paksus: 100 mm
AC_Pset_RenovationAndPhasing - Renovation Status: Existing

# IfcWallStandardCase: SKR-02_Kipsplaat 13 (14)
In: Esimene korrus
Classification: 1.24 IfcWallType (sein) (RKAS BIM + ARCHICAD Classification); Material: SKR-02_Kipsplaat 13 mm
Pset_WallCommon - Reference: SKR-02; LoadBearing: no; IsExternal: yes
AR_Sein - 001_Nimetus: Vundamendi soojustus; 325_Helipidavus: nõudeid ei esitata; 330_Tulekindlus: Undefined; 335_Välispiire: yes; 500_Kandev: no; 505_Paksus: 13 mm; 340_Soojusläbivus: 0,16
AC_Pset_RenovationAndPhasing - Renovation Status: Existing
Name | 002_Tähis | 605_Neto_pindala (m2) | 600_Bruto_pindala (m2)
VS-01.4 | VS-01.4 | 0.2691 | 0.3029
VS-01.3 | VS-01.3 | 0.980201 | 1.8122
VS-01.4 | VS-01.4 | 0.86272 | 0.896
VS-01.3 | VS-01.3 | 1.014 | 1.846
VS-01.6 | VS-01.6 | 0.547575 | 0.547575
VS-01.5 | VS-01.5 | 0.651705 | 0.686415
VS-01.4 | VS-01.4 | 0.96387 | 0.99858
VS-01.3 | VS-01.3 | 0.512865 | 0.512865
VS-01.4 | VS-01.4 | 0.47259 | 0.5073
VS-01.3 | VS-01.3 | 0.721125 | 0.721125
VS-01.7 | VS-01.7 | 0.99858 | 1.068
VS-01.8 | VS-01.8 | 0.721125 | 1.17502
VS-01.7 | VS-01.7 | 0.69687 | 0.7308
VS-01.4 | VS-01.4 | 0.3029 | 0.3367

# IfcWallStandardCase: SP2B E-PIR 220, SEIN
In: Esimene korrus
Classification: 1.24 IfcWallType (sein) (RKAS BIM + ARCHICAD Classification); Material: SP2B E-PIR 220 mm
AR_Sein - 500_Kandev: yes; 002_Tähis: SEIN; 325_Helipidavus: Undefined; 330_Tulekindlus: EI60; 335_Välispiire: yes; 605_Neto_pindala: 3.025 m2; 600_Bruto_pindala: 5.887 m2; 505_Paksus: 220 mm
Pset_WallCommon - Reference: SP2B E-PIR; LoadBearing: yes; IsExternal: yes
AC_Pset_RenovationAndPhasing - Renovation Status: Existing

# IfcWallStandardCase: SS-05 100 (8)
In: Teine korrus
Classification: 1.24 IfcWallType (sein) (RKAS BIM + ARCHICAD Classification); Material: Olemasolev silikaltsiitpaneel 100 mm
AR_Sein - 500_Kandev: no; 335_Välispiire: no; 001_Nimetus: Ol.olev seisesein; 002_Tähis: SS-05; 325_Helipidavus: 64 dB; 505_Paksus: 100 mm
Pset_WallCommon - Reference: SS-05; LoadBearing: no; IsExternal: no
AC_Pset_RenovationAndPhasing - Renovation Status: Existing
Name | 330_Tulekindlus | 605_Neto_pindala (m2) | 600_Bruto_pindala (m2)
SS-05 | nõudeid ei esitata | 1.71238 | 1.72538
SS-05 | nõudeid ei esitata | 31.8261 | 36.6865
SS-05 | nõudeid ei esitata | 31.1235 | 38.9584
SS-05 | nõudeid ei esitata | 15.4522 | 17.5912
SS-05 | EI30 | 6.243 | 8.289
SS-05 | nõudeid ei esitata | 4.5064 | 7.5522
SS-05 | nõudeid ei esitata | 13.6606 | 15.7736
SS-05 | nõudeid ei esitata | 1.0886 | 1.1666

# IfcWallStandardCase: SS-05A 140, SS-05
In: Teine korrus
Classification: 1.24 IfcWallType (sein) (RKAS BIM + ARCHICAD Classification); Material: Olemasolev silikaltsiitpaneel 140 mm
AR_Sein - 500_Kandev: no; 335_Välispiire: no; 001_Nimetus: Ol.olev seisesein; 002_Tähis: SS-05; 325_Helipidavus: 64 dB; 330_Tulekindlus: nõudeid ei esitata; 605_Neto_pindala: 8.35663 m2; 600_Bruto_pindala: 8.98363 m2; 505_Paksus: 140 mm
Pset_WallCommon - Reference: SS-05A; LoadBearing: yes; IsExternal: no
AC_Pset_RenovationAndPhasing - Renovation Status: Existing

# IfcWallStandardCase: SS-08A 305, SS-08
In: Teine korrus
Classification: 1.24 IfcWallType (sein) (RKAS BIM + ARCHICAD Classification); Material: Olemasolev silikaltsiitpaneel 305 mm
AR_Sein - 500_Kandev: no; 335_Välispiire: no; 001_Nimetus: Ol.olev sisesein; 002_Tähis: SS-08; 325_Helipidavus: 48 dB; 330_Tulekindlus: nõudeid ei esitata; 605_Neto_pindala: 4.66097 m2; 600_Bruto_pindala: 9.37497 m2; 505_Paksus: 305 mm
Pset_WallCommon - Reference: SS-08A; LoadBearing: no; IsExternal: no
AC_Pset_RenovationAndPhasing - Renovation Status: Existing

# IfcWallStandardCase: SS-09 100 (3)
In: Teine korrus
Classification: 1.24 IfcWallType (sein) (RKAS BIM + ARCHICAD Classification); Material: BAUROC Acoustic 100 mm
AR_Sein - 500_Kandev: no; 335_Välispiire: no; 001_Nimetus: Sisesein; 002_Tähis: SS-09; 325_Helipidavus: 64 dB; 330_Tulekindlus: nõudeid ei esitata; 505_Paksus: 100 mm
Pset_WallCommon - Reference: SS-09; LoadBearing: no; IsExternal: no
AC_Pset_RenovationAndPhasing - Renovation Status: New
Name | 605_Neto_pindala (m2) | 600_Bruto_pindala (m2)
SS-09 | 0.000752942 | 2.1
SS-09 | 9.14743 | 11.2604
SS-09 | 1.55774 | 5.49757

# IfcWallStandardCase: SS-10.1 100, SS-10.1
In: Teine korrus
Classification: 1.24 IfcWallType (sein) (RKAS BIM + ARCHICAD Classification); Material: BAUROC Acoustic 100 mm
AR_Sein - 335_Välispiire: no; 500_Kandev: no; 002_Tähis: SS-10.1; 325_Helipidavus: 39 dB; 330_Tulekindlus: nõudeid ei esitata; 605_Neto_pindala: 1.995 m2; 600_Bruto_pindala: 1.995 m2; 505_Paksus: 100 mm
Pset_WallCommon - Reference: SS-10.1; LoadBearing: no; IsExternal: no
AC_Pset_RenovationAndPhasing - Renovation Status: New

# IfcWallStandardCase: SS-11 100 (15)
Classification: 1.24 IfcWallType (sein) (RKAS BIM + ARCHICAD Classification); Material: BAUROC Acoustic 100 mm
Pset_WallCommon - Reference: SS-11; LoadBearing: no
AR_Sein - 002_Tähis: SS-11; 500_Kandev: no; 505_Paksus: 100 mm
AC_Pset_RenovationAndPhasing - Renovation Status: New
Name | In | IsExternal | 001_Nimetus | 325_Helipidavus | 330_Tulekindlus | 335_Välispiire | 605_Neto_pindala (m2) | 600_Bruto_pindala (m2)
SS-11 | Esimene korrus | yes | Sisesein | 39 dB | nõudeid ei esitata | no | 4.16055 | 4.91429
SS-11 | Esimene korrus | yes | Sisesein | 39 dB | nõudeid ei esitata | no | 3 | 7.4726
SS-11 | Esimene korrus | yes |  | 24 dB | nõudeid ei esitata | yes | 0.93635 | 1.92125
SS-11 | Esimene korrus | yes |  | 24 dB | nõudeid ei esitata | yes | 0.66875 | 0.93625
SS-11 | Esimene korrus | yes |  | 24 dB | nõudeid ei esitata | yes | 1.0325 | 1.534
SS-11 | Esimene korrus | yes |  | 24 dB | nõudeid ei esitata | yes | 1.23135 | 1.92125
SS-11 | Esimene korrus | yes |  | 24 dB | nõudeid ei esitata | yes | 1.0325 | 1.3275
SS-11 | Teine korrus | yes | Sisesein | 39 dB | nõudeid ei esitata | no | 7.62954 | 9.17304
SS-11 | Teine korrus | no | Sisesein | 39 dB | EI30 | no | 5.51116 | 7.17054
SS-11 | Teine korrus | no | Sisesein | 39 dB | EI30 | no | 3.27032 | 3.56432
SS-11 | Teine korrus | yes | Sisesein | 39 dB | nõudeid ei esitata | no | 3.49849 | 4.72769
SS-11 | Teine korrus | yes | Sisesein | 39 dB | nõudeid ei esitata | no | 6.67309 | 7.58216
SS-11 | Teine korrus | yes | Sisesein | 39 dB | nõudeid ei esitata | no | 0.63 | 2.3025
SS-11 | Teine korrus | yes | Sisesein | 39 dB | nõudeid ei esitata | no | 0.799708 | 2.05764
SS-11 | Teine korrus | yes | Sisesein | 39 dB | nõudeid ei esitata | no | 0.66 | 0.699

# IfcWallStandardCase: SS-13 100 (2)
In: Esimene korrus
Classification: 1.24 IfcWallType (sein) (RKAS BIM + ARCHICAD Classification); Material: SP2B E-PIR 100 mm
Pset_WallCommon - Reference: SS-13; LoadBearing: no; IsExternal: yes
AR_Sein - 001_Nimetus: Sisesein; 002_Tähis: SS-13; 325_Helipidavus: 24 dB; 330_Tulekindlus: nõudeid ei esitata; 335_Välispiire: yes; 500_Kandev: no; 505_Paksus: 100 mm
AC_Pset_RenovationAndPhasing - Renovation Status: New
Name | 605_Neto_pindala (m2) | 600_Bruto_pindala (m2)
SS-13 | 6.48243 | 6.48243
SS-13 | 2.30481 | 3.72599

# IfcWallStandardCase: VS-02_olol 320 (8)
Classification: 1.24 IfcWallType (sein) (RKAS BIM + ARCHICAD Classification); Material: Olemasolev silikaltsiitpaneel 320 mm
Pset_WallCommon - Reference: VS-02; LoadBearing: yes; IsExternal: yes
AR_Sein - 001_Nimetus: Ol.olev välissein; 325_Helipidavus: 48 dB; 330_Tulekindlus: nõudeid ei esitata; 335_Välispiire: yes; 500_Kandev: yes; 505_Paksus: 320 mm; 340_Soojusläbivus: 0,10
AC_Pset_RenovationAndPhasing - Renovation Status: Existing
Name | In | 002_Tähis | 605_Neto_pindala (m2) | 600_Bruto_pindala (m2)
VS-03 | Esimene korrus | VS-03 | 4.24785 | 10.2978
VS-02 | Esimene korrus | VS-02 | 4.805 | 11.517
VS-02 | Esimene korrus | VS-02 | 4.44 | 4.44
VS-02 | Esimene korrus | VS-02 | 36.9197 | 91.113
2 x VS-02 | Teine korrus | VS-02 | 39.8287 | 40.719
VS-02 | Teine korrus | VS-02 | 36.1284 | 91.434
VS-02 | Teine korrus | VS-02 | 35.8996 | 91.434

# IfcWallStandardCase: VS-04_olol 115 (6)
Classification: 1.24 IfcWallType (sein) (RKAS BIM + ARCHICAD Classification); Material: Olemasolev silikaltsiitplokk 115 mm
Pset_WallCommon - Reference: VS-04; LoadBearing: yes; IsExternal: yes
AR_Sein - 002_Tähis: VS-04; 325_Helipidavus: 48 dB; 330_Tulekindlus: nõudeid ei esitata; 335_Välispiire: yes; 500_Kandev: yes; 505_Paksus: 115 mm; 340_Soojusläbivus: 0,10
AC_Pset_RenovationAndPhasing - Renovation Status: Existing
Name | In | 001_Nimetus | 605_Neto_pindala (m2) | 600_Bruto_pindala (m2)
VS-04 | Esimene korrus | Ol.olev välissein | 0.595963 | 4.79596
VS-04 | Esimene korrus | Ol.olev välissein | 1.33009 | 6.06526
VS-04 | Esimene korrus | Ol.olev välissein | 7.6825 | 37.0825
VS-04 | Esimene korrus | Ol.olev välissein | 6.418 | 31.8675
VS-04 | Teine korrus | Välissein | 11.13 | 53.8125
VS-04 | Teine korrus | Välissein | 11.235 | 53.235

# IfcWallStandardCase: VS-06_sisekiht 300, VS-06
In: Esimene korrus
Classification: 1.24 IfcWallType (sein) (RKAS BIM + ARCHICAD Classification); Material: BAUROC CLASSIC 3 MPa kergplokk 300 mm
AR_Sein - 325_Helipidavus: 48 dB; 001_Nimetus: Välissein; 002_Tähis: VS-06; 330_Tulekindlus: nõudeid ei esitata; 335_Välispiire: yes; 605_Neto_pindala: 2.835 m2; 600_Bruto_pindala: 4.86 m2; 500_Kandev: yes; 505_Paksus: 300 mm; 340_Soojusläbivus: 0,10
Pset_WallCommon - Reference: VS-06; LoadBearing: yes; IsExternal: yes
AC_Pset_RenovationAndPhasing - Renovation Status: New

# IfcWallStandardCase: VS-08 sisekiht 100 (2)
In: Esimene korrus
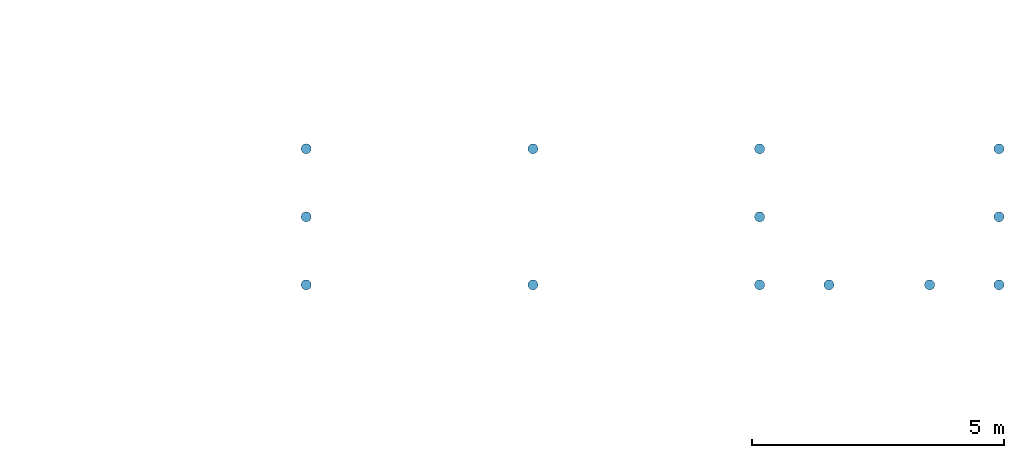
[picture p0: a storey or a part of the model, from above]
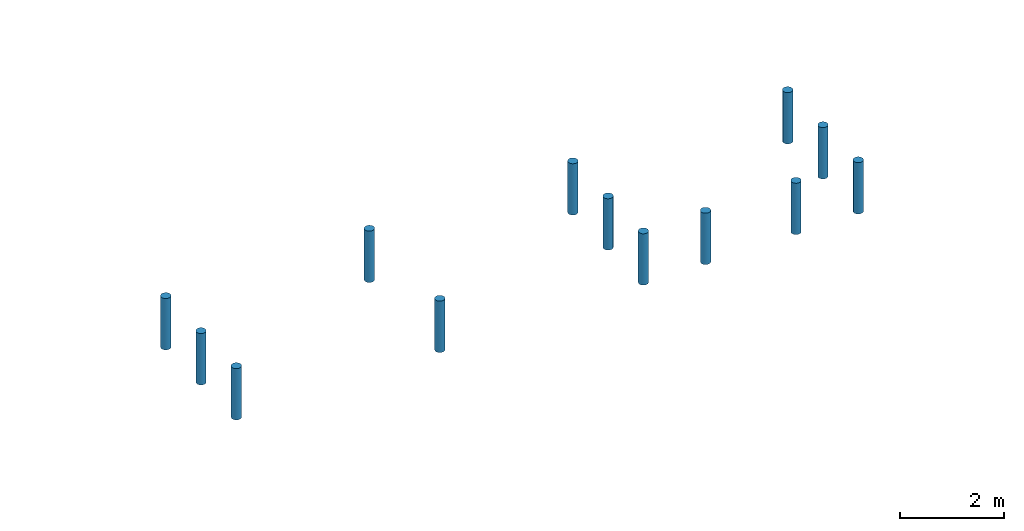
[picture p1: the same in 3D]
Properties of the parts of a building model (IFC2X3), part 5 of 5

# IfcWallStandardCase: VS-08 sisekiht 100 (2)
Classification: 1.24 IfcWallType (sein) (RKAS BIM + ARCHICAD Classification); Material: SP2B E-PIR 100 mm
Pset_WallCommon - Reference: VS-08 sisekiht; LoadBearing: no; IsExternal: yes
AR_Sein - 001_Nimetus: Välissein; 325_Helipidavus: 24 dB; 330_Tulekindlus: nõudeid ei esitata; 335_Välispiire: yes; 500_Kandev: no; 505_Paksus: 100 mm
AC_Pset_RenovationAndPhasing - Renovation Status: New
Name | 002_Tähis | 605_Neto_pindala (m2) | 600_Bruto_pindala (m2) | 340_Soojusläbivus
VS-08 | VS-08 | 3.38498 | 3.72616 | 0,09
VS-08.1 | VS-08.1 | 3.06307 | 5.96943 | 0,08

# IfcWindow: Double Window 23, A-05
In: Esimene korrus
Type - OperationType: DOUBLE_PANEL_VERTICAL; ParameterTakesPrecedence: no; Sizeable: no
Type - Window Lining Properties - LiningDepth: 85 mm; LiningThickness: 100 mm; MullionThickness: 100 mm; FirstMullionOffset: 0.5
Type - Window Panel Properties - Panel 1 - OperationType: TILTANDTURNLEFTHAND; PanelPosition: RIGHT; FrameDepth: 50 mm; FrameThickness: 50 mm
Type - Window Panel Properties - Panel 2 - OperationType: TILTANDTURNRIGHTHAND; PanelPosition: LEFT; FrameDepth: 50 mm; FrameThickness: 50 mm
OverallHeight: 2000 mm; OverallWidth: 1400 mm; Classification: 1.25 IfcWindowStyle (aken) (RKAS BIM + ARCHICAD Classification)
AR_Aken - 001_Nimetus: välisaken; 002_Tähis: A-05; 310_Materjal: puit-alumiinium; 315_Avanemine: sissepoole kald-pöördavatav; 320_Klaas: energiasäästu- ja päikesekaitseklaasiga pakett; 325_Helipidavus: 31 dB; 330_Tulekindlus: nõudeid ei esitata; 335_Välispiire: yes; 340_Soojusläbivus: 0.9; 350_Klaaspakett: SGG CLIMATOP ONE* 4PlthOne-12-4-12-4Plth-One (õhk täidisega); 355_Pindala: 2.8 m2; 375_Viimistlus_seest: MUDELIS: Wood - Pine Grained Horizontal; Wood - Pine Grained Horizontal; MÄRKUS: naturaalne puit lakitud; 376_Viimistlus_väljast: MUDELIS: RAL 7016; RAL 7016; MÄRKUS: pulbervärvitud RAL7016; 900_Tootja: Fenestra OÜ; 905_Mudel: Üheraaamiline puitalumiiniumaken Fenix; 910_Tooteinfo: https://fenestra.ee/toode/uheraamiline-puitalumiiniumaken-fenix/; 915_Kasutus-ja_hooldusjuhend: Undefined; 396_Aknalaud: Kõrgsurve lamineeritud mööblikilp. Toon: Abet Laminati 668 apple tree; 345_Päikesekiirgus_tegur: 0.38; 307_Ava_kõrgus: 2 000; 305_Ava_mõõt: 1 400x2 000; 306_Ava_laius: 1 400
Pset_WindowCommon - ThermalTransmittance: 0; GlazingAreaFraction: 1.8408; IsExternal: yes
AC_Pset_RenovationAndPhasing - Renovation Status: New

# IfcWindow: Double Window 23, A-05
In: Teine korrus
Type - OperationType: DOUBLE_PANEL_VERTICAL; ParameterTakesPrecedence: no; Sizeable: no
Type - Window Lining Properties - LiningDepth: 85 mm; LiningThickness: 100 mm; MullionThickness: 100 mm; FirstMullionOffset: 0.5
Type - Window Panel Properties - Panel 1 - OperationType: TILTANDTURNRIGHTHAND; PanelPosition: LEFT; FrameDepth: 50 mm; FrameThickness: 50 mm
Type - Window Panel Properties - Panel 2 - OperationType: TILTANDTURNLEFTHAND; PanelPosition: RIGHT; FrameDepth: 50 mm; FrameThickness: 50 mm
OverallHeight: 2000 mm; OverallWidth: 1400 mm; Classification: 1.25 IfcWindowStyle (aken) (RKAS BIM + ARCHICAD Classification)
AR_Aken - 001_Nimetus: välisaken; 002_Tähis: A-05; 310_Materjal: puit-alumiinium; 315_Avanemine: sissepoole kald-pöördavatav; 320_Klaas: energiasäästu- ja päikesekaitseklaasiga pakett; 325_Helipidavus: 31 dB; 330_Tulekindlus: nõudeid ei esitata; 335_Välispiire: yes; 340_Soojusläbivus: 0.9; 350_Klaaspakett: SGG CLIMATOP ONE* 4PlthOne-12-4-12-4Plth-One (õhk täidisega); 355_Pindala: 2.8 m2; 375_Viimistlus_seest: MUDELIS: Wood - Pine Grained Horizontal; Wood - Pine Grained Horizontal; MÄRKUS: naturaalne puit lakitud; 376_Viimistlus_väljast: MUDELIS: RAL 7016; RAL 7016; MÄRKUS: pulbervärvitud RAL7016; 900_Tootja: Fenestra OÜ; 905_Mudel: Üheraaamiline puitalumiiniumaken Fenix; 910_Tooteinfo: https://fenestra.ee/toode/uheraamiline-puitalumiiniumaken-fenix/; 915_Kasutus-ja_hooldusjuhend: Undefined; 396_Aknalaud: Kõrgsurve lamineeritud mööblikilp. Toon: Abet Laminati 668 apple tree; 345_Päikesekiirgus_tegur: 0.38; 307_Ava_kõrgus: 2 000; 305_Ava_mõõt: 1 400x2 000; 306_Ava_laius: 1 400
Pset_WindowCommon - ThermalTransmittance: 0; GlazingAreaFraction: 1.8408; IsExternal: yes
AC_Pset_RenovationAndPhasing - Renovation Status: New

# IfcWindow: Triple Window 23, A-01.1
In: Teine korrus
Type - OperationType: TRIPLE_PANEL_VERTICAL; ParameterTakesPrecedence: no; Sizeable: no
Type - Window Lining Properties - LiningDepth: 70 mm; LiningThickness: 100 mm; MullionThickness: 100 mm; FirstMullionOffset: 0.25; SecondMullionOffset: 0.75
Type - Window Panel Properties - Panel 1 - OperationType: TILTANDTURNRIGHTHAND; PanelPosition: LEFT; FrameDepth: 70 mm; FrameThickness: 60 mm
Type - Window Panel Properties - Panel 2 - OperationType: FIXEDCASEMENT; PanelPosition: MIDDLE
Type - Window Panel Properties - Panel 3 - OperationType: TILTANDTURNLEFTHAND; PanelPosition: RIGHT; FrameDepth: 70 mm; FrameThickness: 60 mm
OverallHeight: 1750 mm; OverallWidth: 2400 mm; Classification: 1.25 IfcWindowStyle (aken) (RKAS BIM + ARCHICAD Classification)
AR_Aken - 001_Nimetus: välisaken; 002_Tähis: A-01.1; 310_Materjal: puit-alumiimium; 315_Avanemine: sissepoole pöörd-kaldavatav; 320_Klaas: energiasäästu- ja päikesekaitseklaasiga pakett; 325_Helipidavus: 31 dB; 330_Tulekindlus: nõudeid ei esitata; 335_Välispiire: yes; 340_Soojusläbivus: 0.9; 350_Klaaspakett: SGG CLIMATOP ONE* 4PlthOne-12-4-12-4Plth-One (õhk täidisega); 355_Pindala: 4.2 m2; 375_Viimistlus_seest: MUDELIS: Wood - Pine Grained Horizontal; Wood - Pine Grained Horizontal; MÄRKUS: naturaalne puit lakitud; 376_Viimistlus_väljast: MUDELIS: RAL 7016; RAL 7016; MÄRKUS: pulbervärvitud RAL7016; 900_Tootja: Fenestra OÜ; 905_Mudel: Üheraaamiline puitalumiiniumaken Fenix; 910_Tooteinfo: https://fenestra.ee/toode/uheraamiline-puitalumiiniumaken-fenix/; 915_Kasutus-ja_hooldusjuhend: Undefined; 396_Aknalaud: Kõrgsurve lamineeritud mööblikilp. Toon: Abet Laminati 668 apple tree; 345_Päikesekiirgus_tegur: 0.38; 307_Ava_kõrgus: 1 750; 305_Ava_mõõt: 2 400x1 750; 306_Ava_laius: 2 400
Pset_WindowCommon - ThermalTransmittance: 0; GlazingAreaFraction: 2.8298; IsExternal: yes
AC_Pset_RenovationAndPhasing - Renovation Status: New

# IfcWindow: Triple Window 23, A-02
In: Teine korrus
Type - OperationType: TRIPLE_PANEL_VERTICAL; ParameterTakesPrecedence: no; Sizeable: no
Type - Window Lining Properties - LiningDepth: 80 mm; LiningThickness: 100 mm; MullionThickness: 100 mm; FirstMullionOffset: 0.25; SecondMullionOffset: 0.75
Type - Window Panel Properties - Panel 1 - OperationType: FIXEDCASEMENT; PanelPosition: LEFT
Type - Window Panel Properties - Panel 2 - OperationType: TOPHUNG; PanelPosition: MIDDLE; FrameDepth: 80 mm; FrameThickness: 50 mm
Type - Window Panel Properties - Panel 3 - OperationType: FIXEDCASEMENT; PanelPosition: RIGHT
OverallHeight: 1750 mm; OverallWidth: 2400 mm; Classification: 1.25 IfcWindowStyle (aken) (RKAS BIM + ARCHICAD Classification)
AR_Aken - 001_Nimetus: välisaken; 002_Tähis: A-02; 310_Materjal: Alumiinium; 315_Avanemine: elektriliselt avatav suitsuärastuseks, eenduv ülevalt riputatav aken; 320_Klaas: mürasummutus kolmekordne klaaspakett; 325_Helipidavus: 41 dB; 330_Tulekindlus: nõudeid ei esitata; 335_Välispiire: yes; 340_Soojusläbivus: 0.9; 350_Klaaspakett: SGG CLIMATOP ACOUSTIC 44.2-12Ar-4-15Ar-6PlthXN (argoon 90% täidisega); 355_Pindala: 4.2 m2; 375_Viimistlus_seest: MUDELIS: RAL 7016; RAL 7016; MÄRKUS: pulbervärvitud RAL7016; 376_Viimistlus_väljast: MUDELIS: RAL 7016; RAL 7016; MÄRKUS: pulbervärvitud RAL7016; 900_Tootja: Schüco; 905_Mudel: Schüco AWS 70.HI; 915_Kasutus-ja_hooldusjuhend: Undefined; 396_Aknalaud: Kõrgsurve lamineeritud mööblikilp. Toon: Abet Laminati 668 apple tree; 345_Päikesekiirgus_tegur: 0.64; 307_Ava_kõrgus: 1 750; 305_Ava_mõõt: 2 400x1 750; 306_Ava_laius: 2 400
Pset_WindowCommon - ThermalTransmittance: 0; GlazingAreaFraction: 2.97; IsExternal: yes
AC_Pset_RenovationAndPhasing - Renovation Status: New

# IfcWindow: Triple Window 23 (17)
Type - OperationType: TRIPLE_PANEL_VERTICAL; ParameterTakesPrecedence: no; Sizeable: no
Type - Window Lining Properties - LiningDepth: 80 mm; LiningThickness: 100 mm; MullionThickness: 100 mm; FirstMullionOffset: 0.25; SecondMullionOffset: 0.75
Type - Window Panel Properties - Panel 1 - OperationType: TILTANDTURNLEFTHAND; PanelPosition: RIGHT; FrameDepth: 80 mm; FrameThickness: 50 mm
Type - Window Panel Properties - Panel 2 - OperationType: FIXEDCASEMENT; PanelPosition: MIDDLE
Type - Window Panel Properties - Panel 3 - OperationType: TILTANDTURNRIGHTHAND; PanelPosition: LEFT; FrameDepth: 80 mm; FrameThickness: 50 mm
OverallHeight: 1750 mm; OverallWidth: 2400 mm; Classification: 1.25 IfcWindowStyle (aken) (RKAS BIM + ARCHICAD Classification)
AR_Aken - 001_Nimetus: välisaken; 002_Tähis: A-01; 310_Materjal: puit-alumiimium; 315_Avanemine: sissepoole pöörd-kaldavatav; 320_Klaas: mürasummutus kolmekordne klaaspakett; 325_Helipidavus: 41 dB; 330_Tulekindlus: nõudeid ei esitata; 335_Välispiire: yes; 340_Soojusläbivus: 0.9; 350_Klaaspakett: SGG CLIMATOP ACOUSTIC 44.2-12Ar-4-15Ar-6PlthXN (argoon 90% täidisega); 355_Pindala: 4.2 m2; 375_Viimistlus_seest: MUDELIS: Wood - Pine Grained Horizontal; Wood - Pine Grained Horizontal; MÄRKUS: naturaalne puit lakitud; 376_Viimistlus_väljast: MUDELIS: RAL 7016; RAL 7016; MÄRKUS: pulbervärvitud RAL7016; 900_Tootja: Fenestra OÜ; 905_Mudel: Üheraaamiline puitalumiiniumaken Fenix; 910_Tooteinfo: https://fenestra.ee/toode/uheraamiline-puitalumiiniumaken-fenix/; 915_Kasutus-ja_hooldusjuhend: Undefined; 396_Aknalaud: Kõrgsurve lamineeritud mööblikilp. Toon: Abet Laminati 668 apple tree; 345_Päikesekiirgus_tegur: 0.64; 307_Ava_kõrgus: 1 750; 305_Ava_mõõt: 2 400x1 750; 306_Ava_laius: 2 400
Pset_WindowCommon - ThermalTransmittance: 0; GlazingAreaFraction: 2.905; IsExternal: yes
AC_Pset_RenovationAndPhasing - Renovation Status: New
Name | In
8 x A-01 | Esimene korrus
9 x A-01 | Teine korrus

# IfcWindow: Triple Window 23 (14)
Type - OperationType: TRIPLE_PANEL_VERTICAL; ParameterTakesPrecedence: no; Sizeable: no
Type - Window Lining Properties - LiningDepth: 80 mm; LiningThickness: 100 mm; MullionThickness: 100 mm; FirstMullionOffset: 0.25; SecondMullionOffset: 0.75
Type - Window Panel Properties - Panel 1 - OperationType: TILTANDTURNRIGHTHAND; PanelPosition: LEFT; FrameDepth: 80 mm; FrameThickness: 50 mm
Type - Window Panel Properties - Panel 2 - OperationType: FIXEDCASEMENT; PanelPosition: MIDDLE
Type - Window Panel Properties - Panel 3 - OperationType: TILTANDTURNLEFTHAND; PanelPosition: RIGHT; FrameDepth: 80 mm; FrameThickness: 50 mm
OverallHeight: 1750 mm; OverallWidth: 2400 mm; Classification: 1.25 IfcWindowStyle (aken) (RKAS BIM + ARCHICAD Classification)
AR_Aken - 001_Nimetus: välisaken; 002_Tähis: A-01.1; 310_Materjal: puit-alumiimium; 315_Avanemine: sissepoole pöörd-kaldavatav; 320_Klaas: energiasäästu- ja päikesekaitseklaasiga pakett; 325_Helipidavus: 31 dB; 330_Tulekindlus: nõudeid ei esitata; 335_Välispiire: yes; 340_Soojusläbivus: 0.9; 350_Klaaspakett: SGG CLIMATOP ONE* 4PlthOne-12-4-12-4Plth-One (õhk täidisega); 355_Pindala: 4.2 m2; 375_Viimistlus_seest: MUDELIS: Wood - Pine Grained Horizontal; Wood - Pine Grained Horizontal; MÄRKUS: naturaalne puit lakitud; 376_Viimistlus_väljast: MUDELIS: RAL 7016; RAL 7016; MÄRKUS: pulbervärvitud RAL7016; 900_Tootja: Fenestra OÜ; 905_Mudel: Üheraaamiline puitalumiiniumaken Fenix; 910_Tooteinfo: https://fenestra.ee/toode/uheraamiline-puitalumiiniumaken-fenix/; 915_Kasutus-ja_hooldusjuhend: Undefined; 396_Aknalaud: Kõrgsurve lamineeritud mööblikilp. Toon: Abet Laminati 668 apple tree; 345_Päikesekiirgus_tegur: 0.38; 307_Ava_kõrgus: 1 750; 305_Ava_mõõt: 2 400x1 750; 306_Ava_laius: 2 400
Pset_WindowCommon - ThermalTransmittance: 0; GlazingAreaFraction: 2.905; IsExternal: yes
AC_Pset_RenovationAndPhasing - Renovation Status: New
Name | In
5 x A-01.1 | Esimene korrus
9 x A-01.1 | Teine korrus

# IfcWindow: Triple Window 23, A-04
In: Esimene korrus
Type - OperationType: TRIPLE_PANEL_VERTICAL; ParameterTakesPrecedence: no; Sizeable: no
Type - Window Lining Properties - LiningDepth: 80 mm; LiningThickness: 100 mm; MullionThickness: 100 mm; FirstMullionOffset: 0.263911; SecondMullionOffset: 0.71696
Type - Window Panel Properties - Panel 1 - OperationType: TILTANDTURNRIGHTHAND; PanelPosition: LEFT; FrameDepth: 80 mm; FrameThickness: 50 mm
Type - Window Panel Properties - Panel 2 - OperationType: FIXEDCASEMENT; PanelPosition: MIDDLE
Type - Window Panel Properties - Panel 3 - OperationType: TILTANDTURNLEFTHAND; PanelPosition: RIGHT; FrameDepth: 80 mm; FrameThickness: 50 mm
OverallHeight: 1750 mm; OverallWidth: 2119.84 mm; Classification: 1.25 IfcWindowStyle (aken) (RKAS BIM + ARCHICAD Classification)
AR_Aken - 001_Nimetus: välisaken; 002_Tähis: A-04; 310_Materjal: puit-alumiimium; 315_Avanemine: sissepoole pöörd-kaldavatav; 320_Klaas: energiasäästu- ja päikesekaitseklaasiga pakett; 325_Helipidavus: 31 dB; 330_Tulekindlus: nõudeid ei esitata; 335_Välispiire: yes; 340_Soojusläbivus: 0.9; 350_Klaaspakett: SGG CLIMATOP ONE* 4PlthOne-12-4-12-4Plth-One (õhk täidisega); 355_Pindala: 3.70972 m2; 375_Viimistlus_seest: MUDELIS: Wood - Pine Grained Horizontal; Wood - Pine Grained Horizontal; MÄRKUS: naturaalne puit lakitud; 376_Viimistlus_väljast: MUDELIS: RAL 7016; RAL 7016; MÄRKUS: pulbervärvitud RAL7016; 900_Tootja: Fenestra OÜ; 905_Mudel: Üheraaamiline puitalumiiniumaken Fenix; 910_Tooteinfo: https://fenestra.ee/toode/uheraamiline-puitalumiiniumaken-fenix/; 915_Kasutus-ja_hooldusjuhend: Undefined; 396_Aknalaud: Kõrgsurve lamineeritud mööblikilp. Toon: Abet Laminati 668 apple tree; 345_Päikesekiirgus_tegur: 0.38; 307_Ava_kõrgus: 1 750; 305_Ava_mõõt: 2 120x1 750; 306_Ava_laius: 2 120
Pset_WindowCommon - ThermalTransmittance: 0; GlazingAreaFraction: 2.47278; IsExternal: yes
AC_Pset_RenovationAndPhasing - Renovation Status: New

# IfcWindow: Window 23, TTA-01
In: Esimene korrus
Type - OperationType: SINGLE_PANEL; ParameterTakesPrecedence: no; Sizeable: no
Type - Window Lining Properties - LiningDepth: 50 mm; LiningThickness: 50 mm
Type - Window Panel Properties - Panel 1 - OperationType: FIXEDCASEMENT; PanelPosition: MIDDLE
OverallHeight: 870 mm; OverallWidth: 1450 mm; Classification: 1.25 IfcWindowStyle (aken) (RKAS BIM + ARCHICAD Classification)
AR_Aken - 001_Nimetus: tuletõkkeaken; 002_Tähis: TTA-01; 310_Materjal: alumiinium; 315_Avanemine: mitteavatav; 320_Klaas: tulekindel energiasäästu- ja päikesekaitseklaasiga pakett; 325_Helipidavus: nõudeid ei esitata; 330_Tulekindlus: EI30; 335_Välispiire: yes; 340_Soojusläbivus: 1.1; 350_Klaaspakett: CONTRAFLAM 30 EI30 6PlthUN-14Ar-16CF; 355_Pindala: 1.2615 m2; 375_Viimistlus_seest: MUDELIS: RAL 7016; RAL 7016; MÄRKUS: pulbervärvitud RAL7016; 376_Viimistlus_väljast: MUDELIS: RAL 7016; RAL 7016; MÄRKUS: pulbervärvitud RAL7016; 900_Tootja: Schüco; 905_Mudel: Schüco AWS 70 FR 30-CE; 910_Tooteinfo: https://www.schueco.com/nz/architects/products/windows/aluminium/aws-70-fr-30-ce; 915_Kasutus-ja_hooldusjuhend: Undefined; 396_Aknalaud: Kõrgsurve lamineeritud mööblikilp. Toon: Abet Laminati 668 apple tree; 345_Päikesekiirgus_tegur: 75; 307_Ava_kõrgus: 870; 305_Ava_mõõt: 1 450x870; 306_Ava_laius: 1 450
Pset_WindowCommon - ThermalTransmittance: 0; GlazingAreaFraction: 1.0395; IsExternal: yes
AC_Pset_RenovationAndPhasing - Renovation Status: New

# IfcWindow: Window 23, VR-01
In: Esimene korrus
Type - OperationType: SINGLE_PANEL; ParameterTakesPrecedence: no; Sizeable: no
Type - Window Lining Properties - LiningDepth: 50 mm; LiningThickness: 75 mm
Type - Window Panel Properties - Panel 1 - OperationType: TILTANDTURNLEFTHAND; PanelPosition: MIDDLE; FrameDepth: 50 mm; FrameThickness: 50 mm
OverallHeight: 1700 mm; OverallWidth: 1340 mm; Classification: 1.25 IfcWindowStyle (aken) (RKAS BIM + ARCHICAD Classification)
Pset_WindowCommon - ThermalTransmittance: 0; IsExternal: yes
AR_Aken - 001_Nimetus: Välisaken; 002_Tähis: VR-01; 310_Materjal: puit-alumiinium; 315_Avanemine: sissepoole kald-pöördavatav; 320_Klaas: energiasäästu- ja päikesekaitseklaasiga pakett; 325_Helipidavus: nõudeid ei esitata; 330_Tulekindlus: nõudeid ei esitata; 335_Välispiire: yes; 340_Soojusläbivus: 1.29; 350_Klaaspakett: SGG COOL-LITE SKN 176 (neutr) 6-16-6PLC; 355_Pindala: 2.278 m2; 375_Viimistlus_seest: MUDELIS: RAL 7016; RAL 7016; MÄRKUS: tsingitud teras, RAL7016; 376_Viimistlus_väljast: MUDELIS: RAL 7016; RAL 7016; MÄRKUS: tsingitud teras, RAL7016; 900_Tootja: ETS Nord; 905_Mudel: RV välisrest; 910_Tooteinfo: Undefined; 915_Kasutus-ja_hooldusjuhend: Undefined; 396_Aknalaud: Undefined; 345_Päikesekiirgus_tegur: 0.37; 307_Ava_kõrgus: 1 700; 305_Ava_mõõt: 1 340x1 700; 306_Ava_laius: 1 340
AC_Pset_RenovationAndPhasing - Renovation Status: New

# IfcWindow: Window 23 (8)
In: Esimene korrus
Type - OperationType: SINGLE_PANEL; ParameterTakesPrecedence: no; Sizeable: no
Type - Window Lining Properties - LiningDepth: 85 mm; LiningThickness: 100 mm
Type - Window Panel Properties - Panel 1 - OperationType: TILTANDTURNLEFTHAND; PanelPosition: MIDDLE; FrameDepth: 50 mm; FrameThickness: 50 mm
Classification: 1.25 IfcWindowStyle (aken) (RKAS BIM + ARCHICAD Classification)
AR_Aken - 310_Materjal: puit-alumiinium; 315_Avanemine: sissepoole kald-pöördavatav; 320_Klaas: energiasäästu- ja päikesekaitseklaasiga pakett; 325_Helipidavus: 31 dB; 335_Välispiire: yes; 340_Soojusläbivus: 0.9; 350_Klaaspakett: SGG CLIMATOP ONE* 4PlthOne-12-4-12-4Plth-One (õhk täidisega); 375_Viimistlus_seest: MUDELIS: Wood - Pine Grained Horizontal; Wood - Pine Grained Horizontal; MÄRKUS: naturaalne puit lakitud; 376_Viimistlus_väljast: MUDELIS: RAL 7016; RAL 7016; MÄRKUS: pulbervärvitud RAL7016; 900_Tootja: Fenestra OÜ; 905_Mudel: Üheraaamiline puitalumiiniumaken Fenix; 910_Tooteinfo: https://fenestra.ee/toode/uheraamiline-puitalumiiniumaken-fenix/; 915_Kasutus-ja_hooldusjuhend: Undefined; 396_Aknalaud: Kõrgsurve lamineeritud mööblikilp. Toon: Abet Laminati 668 apple tree; 345_Päikesekiirgus_tegur: 0.38
Pset_WindowCommon - ThermalTransmittance: 0; IsExternal: yes
AC_Pset_RenovationAndPhasing - Renovation Status: New
Name | OverallHeight (mm) | OverallWidth (mm) | 001_Nimetus | 002_Tähis | 330_Tulekindlus | 355_Pindala (m2) | 307_Ava_kõrgus | 305_Ava_mõõt | 306_Ava_laius | GlazingAreaFraction
5 x A-06 | 1700 | 1450 | välisaken | A-06 | nõudeid ei esitata | 2.465 | 1 700 | 1 450x1 700 | 1 450 | 1.7934
2 x A-03 | 1750 | 900 | välisaken | A-03 | nõudeid ei esitata | 1.575 | 1 750 | 900x1 750 | 900 | 1.0184
A-07 | 1700 | 1200 | Tuletõkkeaken | A-07 | EI30 | 2.04 | 1 700 | 1 200x1 700 | 1 200 | 1.4259
